VERSION 5.8 ;
BUSBITCHARS "[]" ;
DIVIDERCHAR "/" ;
UNITS
    DATABASE MICRONS 1000 ;
END UNITS

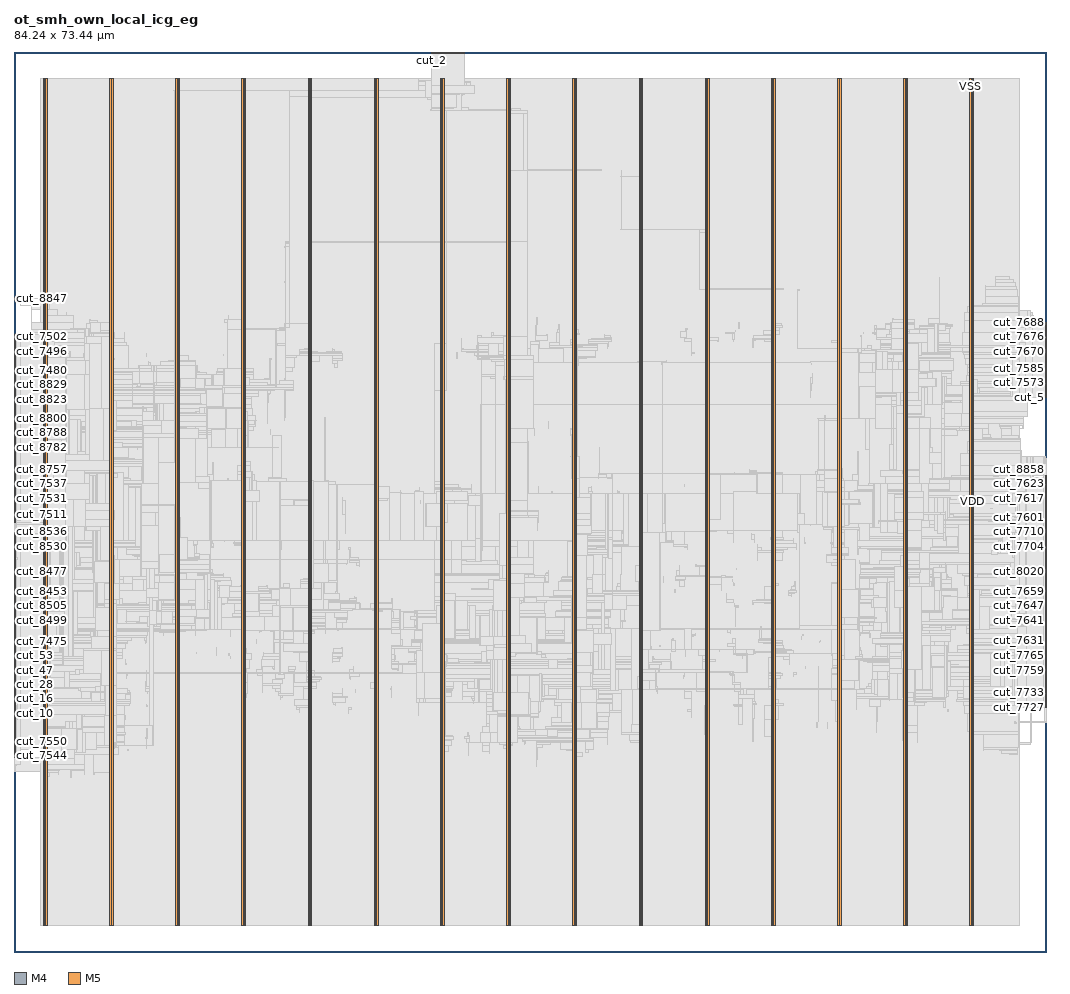
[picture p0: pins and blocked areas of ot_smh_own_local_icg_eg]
MACRO ot_smh_own_local_icg_eg
  FOREIGN ot_smh_own_local_icg_eg 0 0 ;
  CLASS BLOCK ;
  SIZE 84.24 BY 73.44 ;
  PIN cut_10
    DIRECTION INPUT ;
    USE SIGNAL ;
    PORT
      LAYER M4 ;
        RECT  0 19.44 0.084 19.464 ;
    END
  END cut_10
  PIN cut_11
    DIRECTION INPUT ;
    USE SIGNAL ;
    PORT
      LAYER M4 ;
        RECT  0 19.536 0.084 19.56 ;
    END
  END cut_11
  PIN cut_12
    DIRECTION INPUT ;
    USE SIGNAL ;
    PORT
      LAYER M4 ;
        RECT  0 19.632 0.084 19.656 ;
    END
  END cut_12
  PIN cut_13
    DIRECTION INPUT ;
    USE SIGNAL ;
    PORT
      LAYER M4 ;
        RECT  0 19.728 0.084 19.752 ;
    END
  END cut_13
  PIN cut_14
    DIRECTION INPUT ;
    USE SIGNAL ;
    PORT
      LAYER M4 ;
        RECT  0 19.824 0.084 19.848 ;
    END
  END cut_14
  PIN cut_15
    DIRECTION INPUT ;
    USE SIGNAL ;
    PORT
      LAYER M4 ;
        RECT  0 19.92 0.084 19.944 ;
    END
  END cut_15
  PIN cut_16
    DIRECTION INPUT ;
    USE SIGNAL ;
    PORT
      LAYER M4 ;
        RECT  0 20.016 0.084 20.04 ;
    END
  END cut_16
  PIN cut_17
    DIRECTION INPUT ;
    USE SIGNAL ;
    PORT
      LAYER M4 ;
        RECT  0 20.112 0.084 20.136 ;
    END
  END cut_17
  PIN cut_18
    DIRECTION INPUT ;
    USE SIGNAL ;
    PORT
      LAYER M4 ;
        RECT  0 20.208 0.084 20.232 ;
    END
  END cut_18
  PIN cut_19
    DIRECTION INPUT ;
    USE SIGNAL ;
    PORT
      LAYER M4 ;
        RECT  0 20.304 0.084 20.328 ;
    END
  END cut_19
  PIN cut_2
    DIRECTION INPUT ;
    USE SIGNAL ;
    PORT
      LAYER M5 ;
        RECT  34.032 73.356 34.056 73.44 ;
    END
  END cut_2
  PIN cut_20
    DIRECTION INPUT ;
    USE SIGNAL ;
    PORT
      LAYER M4 ;
        RECT  0 20.4 0.084 20.424 ;
    END
  END cut_20
  PIN cut_21
    DIRECTION INPUT ;
    USE SIGNAL ;
    PORT
      LAYER M4 ;
        RECT  0 20.496 0.084 20.52 ;
    END
  END cut_21
  PIN cut_22
    DIRECTION INPUT ;
    USE SIGNAL ;
    PORT
      LAYER M4 ;
        RECT  0 20.592 0.084 20.616 ;
    END
  END cut_22
  PIN cut_23
    DIRECTION INPUT ;
    USE SIGNAL ;
    PORT
      LAYER M4 ;
        RECT  0 20.688 0.084 20.712 ;
    END
  END cut_23
  PIN cut_24
    DIRECTION INPUT ;
    USE SIGNAL ;
    PORT
      LAYER M4 ;
        RECT  0 20.784 0.084 20.808 ;
    END
  END cut_24
  PIN cut_25
    DIRECTION INPUT ;
    USE SIGNAL ;
    PORT
      LAYER M4 ;
        RECT  0 20.88 0.084 20.904 ;
    END
  END cut_25
  PIN cut_26
    DIRECTION INPUT ;
    USE SIGNAL ;
    PORT
      LAYER M4 ;
        RECT  0 20.976 0.084 21 ;
    END
  END cut_26
  PIN cut_27
    DIRECTION INPUT ;
    USE SIGNAL ;
    PORT
      LAYER M4 ;
        RECT  0 21.072 0.084 21.096 ;
    END
  END cut_27
  PIN cut_28
    DIRECTION INPUT ;
    USE SIGNAL ;
    PORT
      LAYER M4 ;
        RECT  0 21.168 0.084 21.192 ;
    END
  END cut_28
  PIN cut_29
    DIRECTION INPUT ;
    USE SIGNAL ;
    PORT
      LAYER M4 ;
        RECT  0 21.264 0.084 21.288 ;
    END
  END cut_29
  PIN cut_3
    DIRECTION INPUT ;
    USE SIGNAL ;
    PORT
      LAYER M5 ;
        RECT  34.128 73.356 34.152 73.44 ;
    END
  END cut_3
  PIN cut_30
    DIRECTION INPUT ;
    USE SIGNAL ;
    PORT
      LAYER M4 ;
        RECT  0 21.36 0.084 21.384 ;
    END
  END cut_30
  PIN cut_31
    DIRECTION INPUT ;
    USE SIGNAL ;
    PORT
      LAYER M4 ;
        RECT  0 21.456 0.084 21.48 ;
    END
  END cut_31
  PIN cut_32
    DIRECTION INPUT ;
    USE SIGNAL ;
    PORT
      LAYER M4 ;
        RECT  0 21.552 0.084 21.576 ;
    END
  END cut_32
  PIN cut_33
    DIRECTION INPUT ;
    USE SIGNAL ;
    PORT
      LAYER M4 ;
        RECT  0 21.648 0.084 21.672 ;
    END
  END cut_33
  PIN cut_34
    DIRECTION INPUT ;
    USE SIGNAL ;
    PORT
      LAYER M4 ;
        RECT  0 21.744 0.084 21.768 ;
    END
  END cut_34
  PIN cut_35
    DIRECTION INPUT ;
    USE SIGNAL ;
    PORT
      LAYER M4 ;
        RECT  0 21.84 0.084 21.864 ;
    END
  END cut_35
  PIN cut_36
    DIRECTION INPUT ;
    USE SIGNAL ;
    PORT
      LAYER M4 ;
        RECT  0 21.936 0.084 21.96 ;
    END
  END cut_36
  PIN cut_37
    DIRECTION INPUT ;
    USE SIGNAL ;
    PORT
      LAYER M4 ;
        RECT  0 22.032 0.084 22.056 ;
    END
  END cut_37
  PIN cut_38
    DIRECTION INPUT ;
    USE SIGNAL ;
    PORT
      LAYER M4 ;
        RECT  0 22.128 0.084 22.152 ;
    END
  END cut_38
  PIN cut_39
    DIRECTION INPUT ;
    USE SIGNAL ;
    PORT
      LAYER M4 ;
        RECT  0 22.224 0.084 22.248 ;
    END
  END cut_39
  PIN cut_4
    DIRECTION INPUT ;
    USE SIGNAL ;
    PORT
      LAYER M4 ;
        RECT  0 18.96 0.084 18.984 ;
    END
  END cut_4
  PIN cut_40
    DIRECTION INPUT ;
    USE SIGNAL ;
    PORT
      LAYER M4 ;
        RECT  0 22.32 0.084 22.344 ;
    END
  END cut_40
  PIN cut_41
    DIRECTION INPUT ;
    USE SIGNAL ;
    PORT
      LAYER M4 ;
        RECT  0 22.416 0.084 22.44 ;
    END
  END cut_41
  PIN cut_42
    DIRECTION INPUT ;
    USE SIGNAL ;
    PORT
      LAYER M4 ;
        RECT  0 22.512 0.084 22.536 ;
    END
  END cut_42
  PIN cut_43
    DIRECTION INPUT ;
    USE SIGNAL ;
    PORT
      LAYER M4 ;
        RECT  0 22.608 0.084 22.632 ;
    END
  END cut_43
  PIN cut_44
    DIRECTION INPUT ;
    USE SIGNAL ;
    PORT
      LAYER M4 ;
        RECT  0 22.704 0.084 22.728 ;
    END
  END cut_44
  PIN cut_45
    DIRECTION INPUT ;
    USE SIGNAL ;
    PORT
      LAYER M4 ;
        RECT  0 22.8 0.084 22.824 ;
    END
  END cut_45
  PIN cut_46
    DIRECTION INPUT ;
    USE SIGNAL ;
    PORT
      LAYER M4 ;
        RECT  0 22.896 0.084 22.92 ;
    END
  END cut_46
  PIN cut_47
    DIRECTION INPUT ;
    USE SIGNAL ;
    PORT
      LAYER M4 ;
        RECT  0 22.992 0.084 23.016 ;
    END
  END cut_47
  PIN cut_48
    DIRECTION INPUT ;
    USE SIGNAL ;
    PORT
      LAYER M4 ;
        RECT  0 23.088 0.084 23.112 ;
    END
  END cut_48
  PIN cut_49
    DIRECTION INPUT ;
    USE SIGNAL ;
    PORT
      LAYER M4 ;
        RECT  0 23.184 0.084 23.208 ;
    END
  END cut_49
  PIN cut_5
    DIRECTION OUTPUT ;
    USE SIGNAL ;
    PORT
      LAYER M4 ;
        RECT  84.156 45.264 84.24 45.288 ;
    END
  END cut_5
  PIN cut_50
    DIRECTION INPUT ;
    USE SIGNAL ;
    PORT
      LAYER M4 ;
        RECT  0 23.28 0.084 23.304 ;
    END
  END cut_50
  PIN cut_51
    DIRECTION INPUT ;
    USE SIGNAL ;
    PORT
      LAYER M4 ;
        RECT  0 23.376 0.084 23.4 ;
    END
  END cut_51
  PIN cut_52
    DIRECTION INPUT ;
    USE SIGNAL ;
    PORT
      LAYER M4 ;
        RECT  0 23.472 0.084 23.496 ;
    END
  END cut_52
  PIN cut_53
    DIRECTION INPUT ;
    USE SIGNAL ;
    PORT
      LAYER M4 ;
        RECT  0 23.568 0.084 23.592 ;
    END
  END cut_53
  PIN cut_54
    DIRECTION INPUT ;
    USE SIGNAL ;
    PORT
      LAYER M4 ;
        RECT  0 23.664 0.084 23.688 ;
    END
  END cut_54
  PIN cut_55
    DIRECTION INPUT ;
    USE SIGNAL ;
    PORT
      LAYER M4 ;
        RECT  0 23.76 0.084 23.784 ;
    END
  END cut_55
  PIN cut_56
    DIRECTION INPUT ;
    USE SIGNAL ;
    PORT
      LAYER M4 ;
        RECT  0 23.856 0.084 23.88 ;
    END
  END cut_56
  PIN cut_57
    DIRECTION INPUT ;
    USE SIGNAL ;
    PORT
      LAYER M4 ;
        RECT  0 23.952 0.084 23.976 ;
    END
  END cut_57
  PIN cut_6
    DIRECTION INPUT ;
    USE SIGNAL ;
    PORT
      LAYER M4 ;
        RECT  0 19.056 0.084 19.08 ;
    END
  END cut_6
  PIN cut_7
    DIRECTION INPUT ;
    USE SIGNAL ;
    PORT
      LAYER M4 ;
        RECT  0 19.152 0.084 19.176 ;
    END
  END cut_7
  PIN cut_7468
    DIRECTION INPUT ;
    USE SIGNAL ;
    PORT
      LAYER M4 ;
        RECT  0 24.048 0.084 24.072 ;
    END
  END cut_7468
  PIN cut_7469
    DIRECTION INPUT ;
    USE SIGNAL ;
    PORT
      LAYER M4 ;
        RECT  0 24.144 0.084 24.168 ;
    END
  END cut_7469
  PIN cut_7470
    DIRECTION INPUT ;
    USE SIGNAL ;
    PORT
      LAYER M4 ;
        RECT  0 24.24 0.084 24.264 ;
    END
  END cut_7470
  PIN cut_7471
    DIRECTION INPUT ;
    USE SIGNAL ;
    PORT
      LAYER M4 ;
        RECT  0 24.336 0.084 24.36 ;
    END
  END cut_7471
  PIN cut_7472
    DIRECTION INPUT ;
    USE SIGNAL ;
    PORT
      LAYER M4 ;
        RECT  0 24.432 0.084 24.456 ;
    END
  END cut_7472
  PIN cut_7473
    DIRECTION INPUT ;
    USE SIGNAL ;
    PORT
      LAYER M4 ;
        RECT  0 24.528 0.084 24.552 ;
    END
  END cut_7473
  PIN cut_7474
    DIRECTION INPUT ;
    USE SIGNAL ;
    PORT
      LAYER M4 ;
        RECT  0 24.624 0.084 24.648 ;
    END
  END cut_7474
  PIN cut_7475
    DIRECTION INPUT ;
    USE SIGNAL ;
    PORT
      LAYER M4 ;
        RECT  0 24.72 0.084 24.744 ;
    END
  END cut_7475
  PIN cut_7476
    DIRECTION INPUT ;
    USE SIGNAL ;
    PORT
      LAYER M4 ;
        RECT  0 24.816 0.084 24.84 ;
    END
  END cut_7476
  PIN cut_7477
    DIRECTION INPUT ;
    USE SIGNAL ;
    PORT
      LAYER M4 ;
        RECT  0 24.912 0.084 24.936 ;
    END
  END cut_7477
  PIN cut_7478
    DIRECTION INPUT ;
    USE SIGNAL ;
    PORT
      LAYER M4 ;
        RECT  0 25.008 0.084 25.032 ;
    END
  END cut_7478
  PIN cut_7479
    DIRECTION INPUT ;
    USE SIGNAL ;
    PORT
      LAYER M4 ;
        RECT  0 47.376 0.084 47.4 ;
    END
  END cut_7479
  PIN cut_7480
    DIRECTION INPUT ;
    USE SIGNAL ;
    PORT
      LAYER M4 ;
        RECT  0 47.472 0.084 47.496 ;
    END
  END cut_7480
  PIN cut_7481
    DIRECTION INPUT ;
    USE SIGNAL ;
    PORT
      LAYER M4 ;
        RECT  0 47.568 0.084 47.592 ;
    END
  END cut_7481
  PIN cut_7482
    DIRECTION INPUT ;
    USE SIGNAL ;
    PORT
      LAYER M4 ;
        RECT  0 47.664 0.084 47.688 ;
    END
  END cut_7482
  PIN cut_7483
    DIRECTION INPUT ;
    USE SIGNAL ;
    PORT
      LAYER M4 ;
        RECT  0 47.76 0.084 47.784 ;
    END
  END cut_7483
  PIN cut_7484
    DIRECTION INPUT ;
    USE SIGNAL ;
    PORT
      LAYER M4 ;
        RECT  0 47.856 0.084 47.88 ;
    END
  END cut_7484
  PIN cut_7485
    DIRECTION INPUT ;
    USE SIGNAL ;
    PORT
      LAYER M4 ;
        RECT  0 47.952 0.084 47.976 ;
    END
  END cut_7485
  PIN cut_7486
    DIRECTION INPUT ;
    USE SIGNAL ;
    PORT
      LAYER M4 ;
        RECT  0 48.048 0.084 48.072 ;
    END
  END cut_7486
  PIN cut_7487
    DIRECTION INPUT ;
    USE SIGNAL ;
    PORT
      LAYER M4 ;
        RECT  0 48.144 0.084 48.168 ;
    END
  END cut_7487
  PIN cut_7488
    DIRECTION INPUT ;
    USE SIGNAL ;
    PORT
      LAYER M4 ;
        RECT  0 48.24 0.084 48.264 ;
    END
  END cut_7488
  PIN cut_7489
    DIRECTION INPUT ;
    USE SIGNAL ;
    PORT
      LAYER M4 ;
        RECT  0 48.336 0.084 48.36 ;
    END
  END cut_7489
  PIN cut_7490
    DIRECTION INPUT ;
    USE SIGNAL ;
    PORT
      LAYER M4 ;
        RECT  0 48.432 0.084 48.456 ;
    END
  END cut_7490
  PIN cut_7491
    DIRECTION INPUT ;
    USE SIGNAL ;
    PORT
      LAYER M4 ;
        RECT  0 48.528 0.084 48.552 ;
    END
  END cut_7491
  PIN cut_7492
    DIRECTION INPUT ;
    USE SIGNAL ;
    PORT
      LAYER M4 ;
        RECT  0 48.624 0.084 48.648 ;
    END
  END cut_7492
  PIN cut_7493
    DIRECTION INPUT ;
    USE SIGNAL ;
    PORT
      LAYER M4 ;
        RECT  0 48.72 0.084 48.744 ;
    END
  END cut_7493
  PIN cut_7494
    DIRECTION INPUT ;
    USE SIGNAL ;
    PORT
      LAYER M4 ;
        RECT  0 48.816 0.084 48.84 ;
    END
  END cut_7494
  PIN cut_7495
    DIRECTION INPUT ;
    USE SIGNAL ;
    PORT
      LAYER M4 ;
        RECT  0 48.912 0.084 48.936 ;
    END
  END cut_7495
  PIN cut_7496
    DIRECTION INPUT ;
    USE SIGNAL ;
    PORT
      LAYER M4 ;
        RECT  0 49.008 0.084 49.032 ;
    END
  END cut_7496
  PIN cut_7497
    DIRECTION INPUT ;
    USE SIGNAL ;
    PORT
      LAYER M4 ;
        RECT  0 49.104 0.084 49.128 ;
    END
  END cut_7497
  PIN cut_7498
    DIRECTION INPUT ;
    USE SIGNAL ;
    PORT
      LAYER M4 ;
        RECT  0 49.2 0.084 49.224 ;
    END
  END cut_7498
  PIN cut_7499
    DIRECTION INPUT ;
    USE SIGNAL ;
    PORT
      LAYER M4 ;
        RECT  0 49.296 0.084 49.32 ;
    END
  END cut_7499
  PIN cut_7500
    DIRECTION INPUT ;
    USE SIGNAL ;
    PORT
      LAYER M4 ;
        RECT  0 49.392 0.084 49.416 ;
    END
  END cut_7500
  PIN cut_7501
    DIRECTION INPUT ;
    USE SIGNAL ;
    PORT
      LAYER M4 ;
        RECT  0 49.488 0.084 49.512 ;
    END
  END cut_7501
  PIN cut_7502
    DIRECTION INPUT ;
    USE SIGNAL ;
    PORT
      LAYER M4 ;
        RECT  0 49.584 0.084 49.608 ;
    END
  END cut_7502
  PIN cut_7503
    DIRECTION INPUT ;
    USE SIGNAL ;
    PORT
      LAYER M4 ;
        RECT  0 49.68 0.084 49.704 ;
    END
  END cut_7503
  PIN cut_7504
    DIRECTION INPUT ;
    USE SIGNAL ;
    PORT
      LAYER M4 ;
        RECT  0 49.776 0.084 49.8 ;
    END
  END cut_7504
  PIN cut_7505
    DIRECTION INPUT ;
    USE SIGNAL ;
    PORT
      LAYER M4 ;
        RECT  0 49.872 0.084 49.896 ;
    END
  END cut_7505
  PIN cut_7506
    DIRECTION INPUT ;
    USE SIGNAL ;
    PORT
      LAYER M4 ;
        RECT  0 49.968 0.084 49.992 ;
    END
  END cut_7506
  PIN cut_7507
    DIRECTION INPUT ;
    USE SIGNAL ;
    PORT
      LAYER M4 ;
        RECT  0 50.064 0.084 50.088 ;
    END
  END cut_7507
  PIN cut_7508
    DIRECTION INPUT ;
    USE SIGNAL ;
    PORT
      LAYER M4 ;
        RECT  0 50.16 0.084 50.184 ;
    END
  END cut_7508
  PIN cut_7509
    DIRECTION INPUT ;
    USE SIGNAL ;
    PORT
      LAYER M4 ;
        RECT  0 50.256 0.084 50.28 ;
    END
  END cut_7509
  PIN cut_7510
    DIRECTION INPUT ;
    USE SIGNAL ;
    PORT
      LAYER M4 ;
        RECT  0 50.352 0.084 50.376 ;
    END
  END cut_7510
  PIN cut_7511
    DIRECTION INPUT ;
    USE SIGNAL ;
    PORT
      LAYER M4 ;
        RECT  0 35.088 0.084 35.112 ;
    END
  END cut_7511
  PIN cut_7512
    DIRECTION INPUT ;
    USE SIGNAL ;
    PORT
      LAYER M4 ;
        RECT  0 35.184 0.084 35.208 ;
    END
  END cut_7512
  PIN cut_7513
    DIRECTION INPUT ;
    USE SIGNAL ;
    PORT
      LAYER M4 ;
        RECT  0 35.28 0.084 35.304 ;
    END
  END cut_7513
  PIN cut_7514
    DIRECTION INPUT ;
    USE SIGNAL ;
    PORT
      LAYER M4 ;
        RECT  0 35.376 0.084 35.4 ;
    END
  END cut_7514
  PIN cut_7515
    DIRECTION INPUT ;
    USE SIGNAL ;
    PORT
      LAYER M4 ;
        RECT  0 35.472 0.084 35.496 ;
    END
  END cut_7515
  PIN cut_7516
    DIRECTION INPUT ;
    USE SIGNAL ;
    PORT
      LAYER M4 ;
        RECT  0 35.568 0.084 35.592 ;
    END
  END cut_7516
  PIN cut_7517
    DIRECTION INPUT ;
    USE SIGNAL ;
    PORT
      LAYER M4 ;
        RECT  0 35.664 0.084 35.688 ;
    END
  END cut_7517
  PIN cut_7518
    DIRECTION INPUT ;
    USE SIGNAL ;
    PORT
      LAYER M4 ;
        RECT  0 35.76 0.084 35.784 ;
    END
  END cut_7518
  PIN cut_7519
    DIRECTION INPUT ;
    USE SIGNAL ;
    PORT
      LAYER M4 ;
        RECT  0 35.856 0.084 35.88 ;
    END
  END cut_7519
  PIN cut_7520
    DIRECTION INPUT ;
    USE SIGNAL ;
    PORT
      LAYER M4 ;
        RECT  0 35.952 0.084 35.976 ;
    END
  END cut_7520
  PIN cut_7521
    DIRECTION INPUT ;
    USE SIGNAL ;
    PORT
      LAYER M4 ;
        RECT  0 36.048 0.084 36.072 ;
    END
  END cut_7521
  PIN cut_7522
    DIRECTION INPUT ;
    USE SIGNAL ;
    PORT
      LAYER M4 ;
        RECT  0 36.144 0.084 36.168 ;
    END
  END cut_7522
  PIN cut_7523
    DIRECTION INPUT ;
    USE SIGNAL ;
    PORT
      LAYER M4 ;
        RECT  0 36.24 0.084 36.264 ;
    END
  END cut_7523
  PIN cut_7524
    DIRECTION INPUT ;
    USE SIGNAL ;
    PORT
      LAYER M4 ;
        RECT  0 36.336 0.084 36.36 ;
    END
  END cut_7524
  PIN cut_7525
    DIRECTION INPUT ;
    USE SIGNAL ;
    PORT
      LAYER M4 ;
        RECT  0 36.432 0.084 36.456 ;
    END
  END cut_7525
  PIN cut_7526
    DIRECTION INPUT ;
    USE SIGNAL ;
    PORT
      LAYER M4 ;
        RECT  0 36.528 0.084 36.552 ;
    END
  END cut_7526
  PIN cut_7527
    DIRECTION INPUT ;
    USE SIGNAL ;
    PORT
      LAYER M4 ;
        RECT  0 36.624 0.084 36.648 ;
    END
  END cut_7527
  PIN cut_7528
    DIRECTION INPUT ;
    USE SIGNAL ;
    PORT
      LAYER M4 ;
        RECT  0 36.72 0.084 36.744 ;
    END
  END cut_7528
  PIN cut_7529
    DIRECTION INPUT ;
    USE SIGNAL ;
    PORT
      LAYER M4 ;
        RECT  0 36.816 0.084 36.84 ;
    END
  END cut_7529
  PIN cut_7530
    DIRECTION INPUT ;
    USE SIGNAL ;
    PORT
      LAYER M4 ;
        RECT  0 36.912 0.084 36.936 ;
    END
  END cut_7530
  PIN cut_7531
    DIRECTION INPUT ;
    USE SIGNAL ;
    PORT
      LAYER M4 ;
        RECT  0 37.008 0.084 37.032 ;
    END
  END cut_7531
  PIN cut_7532
    DIRECTION INPUT ;
    USE SIGNAL ;
    PORT
      LAYER M4 ;
        RECT  0 37.104 0.084 37.128 ;
    END
  END cut_7532
  PIN cut_7533
    DIRECTION INPUT ;
    USE SIGNAL ;
    PORT
      LAYER M4 ;
        RECT  0 37.2 0.084 37.224 ;
    END
  END cut_7533
  PIN cut_7534
    DIRECTION INPUT ;
    USE SIGNAL ;
    PORT
      LAYER M4 ;
        RECT  0 37.296 0.084 37.32 ;
    END
  END cut_7534
  PIN cut_7535
    DIRECTION INPUT ;
    USE SIGNAL ;
    PORT
      LAYER M4 ;
        RECT  0 37.392 0.084 37.416 ;
    END
  END cut_7535
  PIN cut_7536
    DIRECTION INPUT ;
    USE SIGNAL ;
    PORT
      LAYER M4 ;
        RECT  0 37.488 0.084 37.512 ;
    END
  END cut_7536
  PIN cut_7537
    DIRECTION INPUT ;
    USE SIGNAL ;
    PORT
      LAYER M4 ;
        RECT  0 37.584 0.084 37.608 ;
    END
  END cut_7537
  PIN cut_7538
    DIRECTION INPUT ;
    USE SIGNAL ;
    PORT
      LAYER M4 ;
        RECT  0 37.68 0.084 37.704 ;
    END
  END cut_7538
  PIN cut_7539
    DIRECTION INPUT ;
    USE SIGNAL ;
    PORT
      LAYER M4 ;
        RECT  0 37.776 0.084 37.8 ;
    END
  END cut_7539
  PIN cut_7540
    DIRECTION INPUT ;
    USE SIGNAL ;
    PORT
      LAYER M4 ;
        RECT  0 37.872 0.084 37.896 ;
    END
  END cut_7540
  PIN cut_7541
    DIRECTION INPUT ;
    USE SIGNAL ;
    PORT
      LAYER M4 ;
        RECT  0 37.968 0.084 37.992 ;
    END
  END cut_7541
  PIN cut_7542
    DIRECTION INPUT ;
    USE SIGNAL ;
    PORT
      LAYER M4 ;
        RECT  0 38.064 0.084 38.088 ;
    END
  END cut_7542
  PIN cut_7543
    DIRECTION INPUT ;
    USE SIGNAL ;
    PORT
      LAYER M4 ;
        RECT  0 15.888 0.084 15.912 ;
    END
  END cut_7543
  PIN cut_7544
    DIRECTION INPUT ;
    USE SIGNAL ;
    PORT
      LAYER M4 ;
        RECT  0 15.984 0.084 16.008 ;
    END
  END cut_7544
  PIN cut_7545
    DIRECTION INPUT ;
    USE SIGNAL ;
    PORT
      LAYER M4 ;
        RECT  0 16.08 0.084 16.104 ;
    END
  END cut_7545
  PIN cut_7546
    DIRECTION INPUT ;
    USE SIGNAL ;
    PORT
      LAYER M4 ;
        RECT  0 16.176 0.084 16.2 ;
    END
  END cut_7546
  PIN cut_7547
    DIRECTION INPUT ;
    USE SIGNAL ;
    PORT
      LAYER M4 ;
        RECT  0 16.272 0.084 16.296 ;
    END
  END cut_7547
  PIN cut_7548
    DIRECTION INPUT ;
    USE SIGNAL ;
    PORT
      LAYER M4 ;
        RECT  0 16.368 0.084 16.392 ;
    END
  END cut_7548
  PIN cut_7549
    DIRECTION INPUT ;
    USE SIGNAL ;
    PORT
      LAYER M4 ;
        RECT  0 16.464 0.084 16.488 ;
    END
  END cut_7549
  PIN cut_7550
    DIRECTION INPUT ;
    USE SIGNAL ;
    PORT
      LAYER M4 ;
        RECT  0 16.56 0.084 16.584 ;
    END
  END cut_7550
  PIN cut_7551
    DIRECTION INPUT ;
    USE SIGNAL ;
    PORT
      LAYER M4 ;
        RECT  0 16.656 0.084 16.68 ;
    END
  END cut_7551
  PIN cut_7552
    DIRECTION INPUT ;
    USE SIGNAL ;
    PORT
      LAYER M4 ;
        RECT  0 16.752 0.084 16.776 ;
    END
  END cut_7552
  PIN cut_7553
    DIRECTION INPUT ;
    USE SIGNAL ;
    PORT
      LAYER M4 ;
        RECT  0 16.848 0.084 16.872 ;
    END
  END cut_7553
  PIN cut_7554
    DIRECTION INPUT ;
    USE SIGNAL ;
    PORT
      LAYER M4 ;
        RECT  0 16.944 0.084 16.968 ;
    END
  END cut_7554
  PIN cut_7555
    DIRECTION INPUT ;
    USE SIGNAL ;
    PORT
      LAYER M4 ;
        RECT  0 17.04 0.084 17.064 ;
    END
  END cut_7555
  PIN cut_7556
    DIRECTION INPUT ;
    USE SIGNAL ;
    PORT
      LAYER M4 ;
        RECT  0 17.136 0.084 17.16 ;
    END
  END cut_7556
  PIN cut_7557
    DIRECTION INPUT ;
    USE SIGNAL ;
    PORT
      LAYER M4 ;
        RECT  0 17.232 0.084 17.256 ;
    END
  END cut_7557
  PIN cut_7558
    DIRECTION INPUT ;
    USE SIGNAL ;
    PORT
      LAYER M4 ;
        RECT  0 17.328 0.084 17.352 ;
    END
  END cut_7558
  PIN cut_7559
    DIRECTION INPUT ;
    USE SIGNAL ;
    PORT
      LAYER M4 ;
        RECT  0 17.424 0.084 17.448 ;
    END
  END cut_7559
  PIN cut_7560
    DIRECTION INPUT ;
    USE SIGNAL ;
    PORT
      LAYER M4 ;
        RECT  0 17.52 0.084 17.544 ;
    END
  END cut_7560
  PIN cut_7561
    DIRECTION INPUT ;
    USE SIGNAL ;
    PORT
      LAYER M4 ;
        RECT  0 17.616 0.084 17.64 ;
    END
  END cut_7561
  PIN cut_7562
    DIRECTION INPUT ;
    USE SIGNAL ;
    PORT
      LAYER M4 ;
        RECT  0 17.712 0.084 17.736 ;
    END
  END cut_7562
  PIN cut_7563
    DIRECTION INPUT ;
    USE SIGNAL ;
    PORT
      LAYER M4 ;
        RECT  0 17.808 0.084 17.832 ;
    END
  END cut_7563
  PIN cut_7564
    DIRECTION INPUT ;
    USE SIGNAL ;
    PORT
      LAYER M4 ;
        RECT  0 17.904 0.084 17.928 ;
    END
  END cut_7564
  PIN cut_7565
    DIRECTION INPUT ;
    USE SIGNAL ;
    PORT
      LAYER M4 ;
        RECT  0 18 0.084 18.024 ;
    END
  END cut_7565
  PIN cut_7566
    DIRECTION INPUT ;
    USE SIGNAL ;
    PORT
      LAYER M4 ;
        RECT  0 18.096 0.084 18.12 ;
    END
  END cut_7566
  PIN cut_7567
    DIRECTION INPUT ;
    USE SIGNAL ;
    PORT
      LAYER M4 ;
        RECT  0 18.192 0.084 18.216 ;
    END
  END cut_7567
  PIN cut_7568
    DIRECTION OUTPUT ;
    USE SIGNAL ;
    PORT
      LAYER M4 ;
        RECT  84.156 45.36 84.24 45.384 ;
    END
  END cut_7568
  PIN cut_7569
    DIRECTION OUTPUT ;
    USE SIGNAL ;
    PORT
      LAYER M4 ;
        RECT  84.156 45.456 84.24 45.48 ;
    END
  END cut_7569
  PIN cut_7570
    DIRECTION OUTPUT ;
    USE SIGNAL ;
    PORT
      LAYER M4 ;
        RECT  84.156 45.552 84.24 45.576 ;
    END
  END cut_7570
  PIN cut_7571
    DIRECTION OUTPUT ;
    USE SIGNAL ;
    PORT
      LAYER M4 ;
        RECT  84.156 45.648 84.24 45.672 ;
    END
  END cut_7571
  PIN cut_7572
    DIRECTION OUTPUT ;
    USE SIGNAL ;
    PORT
      LAYER M4 ;
        RECT  84.156 45.744 84.24 45.768 ;
    END
  END cut_7572
  PIN cut_7573
    DIRECTION OUTPUT ;
    USE SIGNAL ;
    PORT
      LAYER M4 ;
        RECT  84.156 45.84 84.24 45.864 ;
    END
  END cut_7573
  PIN cut_7574
    DIRECTION OUTPUT ;
    USE SIGNAL ;
    PORT
      LAYER M4 ;
        RECT  84.156 45.936 84.24 45.96 ;
    END
  END cut_7574
  PIN cut_7575
    DIRECTION OUTPUT ;
    USE SIGNAL ;
    PORT
      LAYER M4 ;
        RECT  84.156 46.032 84.24 46.056 ;
    END
  END cut_7575
  PIN cut_7576
    DIRECTION OUTPUT ;
    USE SIGNAL ;
    PORT
      LAYER M4 ;
        RECT  84.156 46.128 84.24 46.152 ;
    END
  END cut_7576
  PIN cut_7577
    DIRECTION OUTPUT ;
    USE SIGNAL ;
    PORT
      LAYER M4 ;
        RECT  84.156 46.224 84.24 46.248 ;
    END
  END cut_7577
  PIN cut_7578
    DIRECTION OUTPUT ;
    USE SIGNAL ;
    PORT
      LAYER M4 ;
        RECT  84.156 46.32 84.24 46.344 ;
    END
  END cut_7578
  PIN cut_7579
    DIRECTION OUTPUT ;
    USE SIGNAL ;
    PORT
      LAYER M4 ;
        RECT  84.156 46.416 84.24 46.44 ;
    END
  END cut_7579
  PIN cut_7580
    DIRECTION OUTPUT ;
    USE SIGNAL ;
    PORT
      LAYER M4 ;
        RECT  84.156 46.512 84.24 46.536 ;
    END
  END cut_7580
  PIN cut_7581
    DIRECTION OUTPUT ;
    USE SIGNAL ;
    PORT
      LAYER M4 ;
        RECT  84.156 46.608 84.24 46.632 ;
    END
  END cut_7581
  PIN cut_7582
    DIRECTION OUTPUT ;
    USE SIGNAL ;
    PORT
      LAYER M4 ;
        RECT  84.156 46.704 84.24 46.728 ;
    END
  END cut_7582
  PIN cut_7583
    DIRECTION OUTPUT ;
    USE SIGNAL ;
    PORT
      LAYER M4 ;
        RECT  84.156 46.8 84.24 46.824 ;
    END
  END cut_7583
  PIN cut_7584
    DIRECTION OUTPUT ;
    USE SIGNAL ;
    PORT
      LAYER M4 ;
        RECT  84.156 46.896 84.24 46.92 ;
    END
  END cut_7584
  PIN cut_7585
    DIRECTION OUTPUT ;
    USE SIGNAL ;
    PORT
      LAYER M4 ;
        RECT  84.156 46.992 84.24 47.016 ;
    END
  END cut_7585
  PIN cut_7586
    DIRECTION OUTPUT ;
    USE SIGNAL ;
    PORT
      LAYER M4 ;
        RECT  84.156 47.088 84.24 47.112 ;
    END
  END cut_7586
  PIN cut_7587
    DIRECTION OUTPUT ;
    USE SIGNAL ;
    PORT
      LAYER M4 ;
        RECT  84.156 47.184 84.24 47.208 ;
    END
  END cut_7587
  PIN cut_7588
    DIRECTION OUTPUT ;
    USE SIGNAL ;
    PORT
      LAYER M4 ;
        RECT  84.156 47.28 84.24 47.304 ;
    END
  END cut_7588
  PIN cut_7589
    DIRECTION OUTPUT ;
    USE SIGNAL ;
    PORT
      LAYER M4 ;
        RECT  84.156 47.376 84.24 47.4 ;
    END
  END cut_7589
  PIN cut_7590
    DIRECTION OUTPUT ;
    USE SIGNAL ;
    PORT
      LAYER M4 ;
        RECT  84.156 47.472 84.24 47.496 ;
    END
  END cut_7590
  PIN cut_7591
    DIRECTION OUTPUT ;
    USE SIGNAL ;
    PORT
      LAYER M4 ;
        RECT  84.156 47.568 84.24 47.592 ;
    END
  END cut_7591
  PIN cut_7592
    DIRECTION OUTPUT ;
    USE SIGNAL ;
    PORT
      LAYER M4 ;
        RECT  84.156 47.664 84.24 47.688 ;
    END
  END cut_7592
  PIN cut_7593
    DIRECTION OUTPUT ;
    USE SIGNAL ;
    PORT
      LAYER M4 ;
        RECT  84.156 47.76 84.24 47.784 ;
    END
  END cut_7593
  PIN cut_7594
    DIRECTION OUTPUT ;
    USE SIGNAL ;
    PORT
      LAYER M4 ;
        RECT  84.156 47.856 84.24 47.88 ;
    END
  END cut_7594
  PIN cut_7595
    DIRECTION OUTPUT ;
    USE SIGNAL ;
    PORT
      LAYER M4 ;
        RECT  84.156 47.952 84.24 47.976 ;
    END
  END cut_7595
  PIN cut_7596
    DIRECTION OUTPUT ;
    USE SIGNAL ;
    PORT
      LAYER M4 ;
        RECT  84.156 48.048 84.24 48.072 ;
    END
  END cut_7596
  PIN cut_7597
    DIRECTION OUTPUT ;
    USE SIGNAL ;
    PORT
      LAYER M4 ;
        RECT  84.156 48.144 84.24 48.168 ;
    END
  END cut_7597
  PIN cut_7598
    DIRECTION OUTPUT ;
    USE SIGNAL ;
    PORT
      LAYER M4 ;
        RECT  84.156 48.24 84.24 48.264 ;
    END
  END cut_7598
  PIN cut_7599
    DIRECTION OUTPUT ;
    USE SIGNAL ;
    PORT
      LAYER M4 ;
        RECT  84.156 35.28 84.24 35.304 ;
    END
  END cut_7599
  PIN cut_7600
    DIRECTION OUTPUT ;
    USE SIGNAL ;
    PORT
      LAYER M4 ;
        RECT  84.156 35.376 84.24 35.4 ;
    END
  END cut_7600
  PIN cut_7601
    DIRECTION OUTPUT ;
    USE SIGNAL ;
    PORT
      LAYER M4 ;
        RECT  84.156 35.472 84.24 35.496 ;
    END
  END cut_7601
  PIN cut_7602
    DIRECTION OUTPUT ;
    USE SIGNAL ;
    PORT
      LAYER M4 ;
        RECT  84.156 35.568 84.24 35.592 ;
    END
  END cut_7602
  PIN cut_7603
    DIRECTION OUTPUT ;
    USE SIGNAL ;
    PORT
      LAYER M4 ;
        RECT  84.156 35.664 84.24 35.688 ;
    END
  END cut_7603
  PIN cut_7604
    DIRECTION OUTPUT ;
    USE SIGNAL ;
    PORT
      LAYER M4 ;
        RECT  84.156 35.76 84.24 35.784 ;
    END
  END cut_7604
  PIN cut_7605
    DIRECTION OUTPUT ;
    USE SIGNAL ;
    PORT
      LAYER M4 ;
        RECT  84.156 35.856 84.24 35.88 ;
    END
  END cut_7605
  PIN cut_7606
    DIRECTION OUTPUT ;
    USE SIGNAL ;
    PORT
      LAYER M4 ;
        RECT  84.156 35.952 84.24 35.976 ;
    END
  END cut_7606
  PIN cut_7607
    DIRECTION OUTPUT ;
    USE SIGNAL ;
    PORT
      LAYER M4 ;
        RECT  84.156 36.048 84.24 36.072 ;
    END
  END cut_7607
  PIN cut_7608
    DIRECTION OUTPUT ;
    USE SIGNAL ;
    PORT
      LAYER M4 ;
        RECT  84.156 36.144 84.24 36.168 ;
    END
  END cut_7608
  PIN cut_7609
    DIRECTION OUTPUT ;
    USE SIGNAL ;
    PORT
      LAYER M4 ;
        RECT  84.156 36.24 84.24 36.264 ;
    END
  END cut_7609
  PIN cut_7610
    DIRECTION OUTPUT ;
    USE SIGNAL ;
    PORT
      LAYER M4 ;
        RECT  84.156 36.336 84.24 36.36 ;
    END
  END cut_7610
  PIN cut_7611
    DIRECTION OUTPUT ;
    USE SIGNAL ;
    PORT
      LAYER M4 ;
        RECT  84.156 36.432 84.24 36.456 ;
    END
  END cut_7611
  PIN cut_7612
    DIRECTION OUTPUT ;
    USE SIGNAL ;
    PORT
      LAYER M4 ;
        RECT  84.156 36.528 84.24 36.552 ;
    END
  END cut_7612
  PIN cut_7613
    DIRECTION OUTPUT ;
    USE SIGNAL ;
    PORT
      LAYER M4 ;
        RECT  84.156 36.624 84.24 36.648 ;
    END
  END cut_7613
  PIN cut_7614
    DIRECTION OUTPUT ;
    USE SIGNAL ;
    PORT
      LAYER M4 ;
        RECT  84.156 36.72 84.24 36.744 ;
    END
  END cut_7614
  PIN cut_7615
    DIRECTION OUTPUT ;
    USE SIGNAL ;
    PORT
      LAYER M4 ;
        RECT  84.156 36.816 84.24 36.84 ;
    END
  END cut_7615
  PIN cut_7616
    DIRECTION OUTPUT ;
    USE SIGNAL ;
    PORT
      LAYER M4 ;
        RECT  84.156 36.912 84.24 36.936 ;
    END
  END cut_7616
  PIN cut_7617
    DIRECTION OUTPUT ;
    USE SIGNAL ;
    PORT
      LAYER M4 ;
        RECT  84.156 37.008 84.24 37.032 ;
    END
  END cut_7617
  PIN cut_7618
    DIRECTION OUTPUT ;
    USE SIGNAL ;
    PORT
      LAYER M4 ;
        RECT  84.156 37.104 84.24 37.128 ;
    END
  END cut_7618
  PIN cut_7619
    DIRECTION OUTPUT ;
    USE SIGNAL ;
    PORT
      LAYER M4 ;
        RECT  84.156 37.2 84.24 37.224 ;
    END
  END cut_7619
  PIN cut_7620
    DIRECTION OUTPUT ;
    USE SIGNAL ;
    PORT
      LAYER M4 ;
        RECT  84.156 37.296 84.24 37.32 ;
    END
  END cut_7620
  PIN cut_7621
    DIRECTION OUTPUT ;
    USE SIGNAL ;
    PORT
      LAYER M4 ;
        RECT  84.156 37.392 84.24 37.416 ;
    END
  END cut_7621
  PIN cut_7622
    DIRECTION OUTPUT ;
    USE SIGNAL ;
    PORT
      LAYER M4 ;
        RECT  84.156 37.488 84.24 37.512 ;
    END
  END cut_7622
  PIN cut_7623
    DIRECTION OUTPUT ;
    USE SIGNAL ;
    PORT
      LAYER M4 ;
        RECT  84.156 37.584 84.24 37.608 ;
    END
  END cut_7623
  PIN cut_7624
    DIRECTION OUTPUT ;
    USE SIGNAL ;
    PORT
      LAYER M4 ;
        RECT  84.156 37.68 84.24 37.704 ;
    END
  END cut_7624
  PIN cut_7625
    DIRECTION OUTPUT ;
    USE SIGNAL ;
    PORT
      LAYER M4 ;
        RECT  84.156 37.776 84.24 37.8 ;
    END
  END cut_7625
  PIN cut_7626
    DIRECTION OUTPUT ;
    USE SIGNAL ;
    PORT
      LAYER M4 ;
        RECT  84.156 37.872 84.24 37.896 ;
    END
  END cut_7626
  PIN cut_7627
    DIRECTION OUTPUT ;
    USE SIGNAL ;
    PORT
      LAYER M4 ;
        RECT  84.156 37.968 84.24 37.992 ;
    END
  END cut_7627
  PIN cut_7628
    DIRECTION OUTPUT ;
    USE SIGNAL ;
    PORT
      LAYER M4 ;
        RECT  84.156 38.064 84.24 38.088 ;
    END
  END cut_7628
  PIN cut_7629
    DIRECTION OUTPUT ;
    USE SIGNAL ;
    PORT
      LAYER M4 ;
        RECT  84.156 38.16 84.24 38.184 ;
    END
  END cut_7629
  PIN cut_7630
    DIRECTION OUTPUT ;
    USE SIGNAL ;
    PORT
      LAYER M4 ;
        RECT  84.156 38.256 84.24 38.28 ;
    END
  END cut_7630
  PIN cut_7631
    DIRECTION OUTPUT ;
    USE SIGNAL ;
    PORT
      LAYER M4 ;
        RECT  84.156 26.064 84.24 26.088 ;
    END
  END cut_7631
  PIN cut_7632
    DIRECTION OUTPUT ;
    USE SIGNAL ;
    PORT
      LAYER M4 ;
        RECT  84.156 26.16 84.24 26.184 ;
    END
  END cut_7632
  PIN cut_7633
    DIRECTION OUTPUT ;
    USE SIGNAL ;
    PORT
      LAYER M4 ;
        RECT  84.156 26.256 84.24 26.28 ;
    END
  END cut_7633
  PIN cut_7634
    DIRECTION OUTPUT ;
    USE SIGNAL ;
    PORT
      LAYER M4 ;
        RECT  84.156 26.352 84.24 26.376 ;
    END
  END cut_7634
  PIN cut_7635
    DIRECTION OUTPUT ;
    USE SIGNAL ;
    PORT
      LAYER M4 ;
        RECT  84.156 26.448 84.24 26.472 ;
    END
  END cut_7635
  PIN cut_7636
    DIRECTION OUTPUT ;
    USE SIGNAL ;
    PORT
      LAYER M4 ;
        RECT  84.156 26.544 84.24 26.568 ;
    END
  END cut_7636
  PIN cut_7637
    DIRECTION OUTPUT ;
    USE SIGNAL ;
    PORT
      LAYER M4 ;
        RECT  84.156 26.64 84.24 26.664 ;
    END
  END cut_7637
  PIN cut_7638
    DIRECTION OUTPUT ;
    USE SIGNAL ;
    PORT
      LAYER M4 ;
        RECT  84.156 26.736 84.24 26.76 ;
    END
  END cut_7638
  PIN cut_7639
    DIRECTION OUTPUT ;
    USE SIGNAL ;
    PORT
      LAYER M4 ;
        RECT  84.156 26.832 84.24 26.856 ;
    END
  END cut_7639
  PIN cut_7640
    DIRECTION OUTPUT ;
    USE SIGNAL ;
    PORT
      LAYER M4 ;
        RECT  84.156 26.928 84.24 26.952 ;
    END
  END cut_7640
  PIN cut_7641
    DIRECTION OUTPUT ;
    USE SIGNAL ;
    PORT
      LAYER M4 ;
        RECT  84.156 27.024 84.24 27.048 ;
    END
  END cut_7641
  PIN cut_7642
    DIRECTION OUTPUT ;
    USE SIGNAL ;
    PORT
      LAYER M4 ;
        RECT  84.156 27.12 84.24 27.144 ;
    END
  END cut_7642
  PIN cut_7643
    DIRECTION OUTPUT ;
    USE SIGNAL ;
    PORT
      LAYER M4 ;
        RECT  84.156 27.216 84.24 27.24 ;
    END
  END cut_7643
  PIN cut_7644
    DIRECTION OUTPUT ;
    USE SIGNAL ;
    PORT
      LAYER M4 ;
        RECT  84.156 27.312 84.24 27.336 ;
    END
  END cut_7644
  PIN cut_7645
    DIRECTION OUTPUT ;
    USE SIGNAL ;
    PORT
      LAYER M4 ;
        RECT  84.156 27.408 84.24 27.432 ;
    END
  END cut_7645
  PIN cut_7646
    DIRECTION OUTPUT ;
    USE SIGNAL ;
    PORT
      LAYER M4 ;
        RECT  84.156 27.504 84.24 27.528 ;
    END
  END cut_7646
  PIN cut_7647
    DIRECTION OUTPUT ;
    USE SIGNAL ;
    PORT
      LAYER M4 ;
        RECT  84.156 27.6 84.24 27.624 ;
    END
  END cut_7647
  PIN cut_7648
    DIRECTION OUTPUT ;
    USE SIGNAL ;
    PORT
      LAYER M4 ;
        RECT  84.156 27.696 84.24 27.72 ;
    END
  END cut_7648
  PIN cut_7649
    DIRECTION OUTPUT ;
    USE SIGNAL ;
    PORT
      LAYER M4 ;
        RECT  84.156 27.792 84.24 27.816 ;
    END
  END cut_7649
  PIN cut_7650
    DIRECTION OUTPUT ;
    USE SIGNAL ;
    PORT
      LAYER M4 ;
        RECT  84.156 27.888 84.24 27.912 ;
    END
  END cut_7650
  PIN cut_7651
    DIRECTION OUTPUT ;
    USE SIGNAL ;
    PORT
      LAYER M4 ;
        RECT  84.156 27.984 84.24 28.008 ;
    END
  END cut_7651
  PIN cut_7652
    DIRECTION OUTPUT ;
    USE SIGNAL ;
    PORT
      LAYER M4 ;
        RECT  84.156 28.08 84.24 28.104 ;
    END
  END cut_7652
  PIN cut_7653
    DIRECTION OUTPUT ;
    USE SIGNAL ;
    PORT
      LAYER M4 ;
        RECT  84.156 28.176 84.24 28.2 ;
    END
  END cut_7653
  PIN cut_7654
    DIRECTION OUTPUT ;
    USE SIGNAL ;
    PORT
      LAYER M4 ;
        RECT  84.156 28.272 84.24 28.296 ;
    END
  END cut_7654
  PIN cut_7655
    DIRECTION OUTPUT ;
    USE SIGNAL ;
    PORT
      LAYER M4 ;
        RECT  84.156 28.368 84.24 28.392 ;
    END
  END cut_7655
  PIN cut_7656
    DIRECTION OUTPUT ;
    USE SIGNAL ;
    PORT
      LAYER M4 ;
        RECT  84.156 28.464 84.24 28.488 ;
    END
  END cut_7656
  PIN cut_7657
    DIRECTION OUTPUT ;
    USE SIGNAL ;
    PORT
      LAYER M4 ;
        RECT  84.156 28.56 84.24 28.584 ;
    END
  END cut_7657
  PIN cut_7658
    DIRECTION OUTPUT ;
    USE SIGNAL ;
    PORT
      LAYER M4 ;
        RECT  84.156 28.656 84.24 28.68 ;
    END
  END cut_7658
  PIN cut_7659
    DIRECTION OUTPUT ;
    USE SIGNAL ;
    PORT
      LAYER M4 ;
        RECT  84.156 28.752 84.24 28.776 ;
    END
  END cut_7659
  PIN cut_7660
    DIRECTION OUTPUT ;
    USE SIGNAL ;
    PORT
      LAYER M4 ;
        RECT  84.156 28.848 84.24 28.872 ;
    END
  END cut_7660
  PIN cut_7661
    DIRECTION OUTPUT ;
    USE SIGNAL ;
    PORT
      LAYER M4 ;
        RECT  84.156 28.944 84.24 28.968 ;
    END
  END cut_7661
  PIN cut_7662
    DIRECTION OUTPUT ;
    USE SIGNAL ;
    PORT
      LAYER M4 ;
        RECT  84.156 29.04 84.24 29.064 ;
    END
  END cut_7662
  PIN cut_7663
    DIRECTION OUTPUT ;
    USE SIGNAL ;
    PORT
      LAYER M4 ;
        RECT  84.156 48.336 84.24 48.36 ;
    END
  END cut_7663
  PIN cut_7664
    DIRECTION OUTPUT ;
    USE SIGNAL ;
    PORT
      LAYER M4 ;
        RECT  84.156 48.432 84.24 48.456 ;
    END
  END cut_7664
  PIN cut_7665
    DIRECTION OUTPUT ;
    USE SIGNAL ;
    PORT
      LAYER M4 ;
        RECT  84.156 48.528 84.24 48.552 ;
    END
  END cut_7665
  PIN cut_7666
    DIRECTION OUTPUT ;
    USE SIGNAL ;
    PORT
      LAYER M4 ;
        RECT  84.156 48.624 84.24 48.648 ;
    END
  END cut_7666
  PIN cut_7667
    DIRECTION OUTPUT ;
    USE SIGNAL ;
    PORT
      LAYER M4 ;
        RECT  84.156 48.72 84.24 48.744 ;
    END
  END cut_7667
  PIN cut_7668
    DIRECTION OUTPUT ;
    USE SIGNAL ;
    PORT
      LAYER M4 ;
        RECT  84.156 48.816 84.24 48.84 ;
    END
  END cut_7668
  PIN cut_7669
    DIRECTION OUTPUT ;
    USE SIGNAL ;
    PORT
      LAYER M4 ;
        RECT  84.156 48.912 84.24 48.936 ;
    END
  END cut_7669
  PIN cut_7670
    DIRECTION OUTPUT ;
    USE SIGNAL ;
    PORT
      LAYER M4 ;
        RECT  84.156 49.008 84.24 49.032 ;
    END
  END cut_7670
  PIN cut_7671
    DIRECTION OUTPUT ;
    USE SIGNAL ;
    PORT
      LAYER M4 ;
        RECT  84.156 49.104 84.24 49.128 ;
    END
  END cut_7671
  PIN cut_7672
    DIRECTION OUTPUT ;
    USE SIGNAL ;
    PORT
      LAYER M4 ;
        RECT  84.156 49.2 84.24 49.224 ;
    END
  END cut_7672
  PIN cut_7673
    DIRECTION OUTPUT ;
    USE SIGNAL ;
    PORT
      LAYER M4 ;
        RECT  84.156 49.296 84.24 49.32 ;
    END
  END cut_7673
  PIN cut_7674
    DIRECTION OUTPUT ;
    USE SIGNAL ;
    PORT
      LAYER M4 ;
        RECT  84.156 49.392 84.24 49.416 ;
    END
  END cut_7674
  PIN cut_7675
    DIRECTION OUTPUT ;
    USE SIGNAL ;
    PORT
      LAYER M4 ;
        RECT  84.156 49.488 84.24 49.512 ;
    END
  END cut_7675
  PIN cut_7676
    DIRECTION OUTPUT ;
    USE SIGNAL ;
    PORT
      LAYER M4 ;
        RECT  84.156 49.584 84.24 49.608 ;
    END
  END cut_7676
  PIN cut_7677
    DIRECTION OUTPUT ;
    USE SIGNAL ;
    PORT
      LAYER M4 ;
        RECT  84.156 49.68 84.24 49.704 ;
    END
  END cut_7677
  PIN cut_7678
    DIRECTION OUTPUT ;
    USE SIGNAL ;
    PORT
      LAYER M4 ;
        RECT  84.156 49.776 84.24 49.8 ;
    END
  END cut_7678
  PIN cut_7679
    DIRECTION OUTPUT ;
    USE SIGNAL ;
    PORT
      LAYER M4 ;
        RECT  84.156 49.872 84.24 49.896 ;
    END
  END cut_7679
  PIN cut_7680
    DIRECTION OUTPUT ;
    USE SIGNAL ;
    PORT
      LAYER M4 ;
        RECT  84.156 49.968 84.24 49.992 ;
    END
  END cut_7680
  PIN cut_7681
    DIRECTION OUTPUT ;
    USE SIGNAL ;
    PORT
      LAYER M4 ;
        RECT  84.156 50.064 84.24 50.088 ;
    END
  END cut_7681
  PIN cut_7682
    DIRECTION OUTPUT ;
    USE SIGNAL ;
    PORT
      LAYER M4 ;
        RECT  84.156 50.16 84.24 50.184 ;
    END
  END cut_7682
  PIN cut_7683
    DIRECTION OUTPUT ;
    USE SIGNAL ;
    PORT
      LAYER M4 ;
        RECT  84.156 50.256 84.24 50.28 ;
    END
  END cut_7683
  PIN cut_7684
    DIRECTION OUTPUT ;
    USE SIGNAL ;
    PORT
      LAYER M4 ;
        RECT  84.156 50.352 84.24 50.376 ;
    END
  END cut_7684
  PIN cut_7685
    DIRECTION OUTPUT ;
    USE SIGNAL ;
    PORT
      LAYER M4 ;
        RECT  84.156 50.448 84.24 50.472 ;
    END
  END cut_7685
  PIN cut_7686
    DIRECTION OUTPUT ;
    USE SIGNAL ;
    PORT
      LAYER M4 ;
        RECT  84.156 50.544 84.24 50.568 ;
    END
  END cut_7686
  PIN cut_7687
    DIRECTION OUTPUT ;
    USE SIGNAL ;
    PORT
      LAYER M4 ;
        RECT  84.156 50.64 84.24 50.664 ;
    END
  END cut_7687
  PIN cut_7688
    DIRECTION OUTPUT ;
    USE SIGNAL ;
    PORT
      LAYER M4 ;
        RECT  84.156 50.736 84.24 50.76 ;
    END
  END cut_7688
  PIN cut_7689
    DIRECTION OUTPUT ;
    USE SIGNAL ;
    PORT
      LAYER M4 ;
        RECT  84.156 50.832 84.24 50.856 ;
    END
  END cut_7689
  PIN cut_7690
    DIRECTION OUTPUT ;
    USE SIGNAL ;
    PORT
      LAYER M4 ;
        RECT  84.156 50.928 84.24 50.952 ;
    END
  END cut_7690
  PIN cut_7691
    DIRECTION OUTPUT ;
    USE SIGNAL ;
    PORT
      LAYER M4 ;
        RECT  84.156 51.024 84.24 51.048 ;
    END
  END cut_7691
  PIN cut_7692
    DIRECTION OUTPUT ;
    USE SIGNAL ;
    PORT
      LAYER M4 ;
        RECT  84.156 51.12 84.24 51.144 ;
    END
  END cut_7692
  PIN cut_7693
    DIRECTION OUTPUT ;
    USE SIGNAL ;
    PORT
      LAYER M4 ;
        RECT  84.156 51.216 84.24 51.24 ;
    END
  END cut_7693
  PIN cut_7694
    DIRECTION OUTPUT ;
    USE SIGNAL ;
    PORT
      LAYER M4 ;
        RECT  84.156 51.312 84.24 51.336 ;
    END
  END cut_7694
  PIN cut_7695
    DIRECTION OUTPUT ;
    USE SIGNAL ;
    PORT
      LAYER M4 ;
        RECT  84.156 32.208 84.24 32.232 ;
    END
  END cut_7695
  PIN cut_7696
    DIRECTION OUTPUT ;
    USE SIGNAL ;
    PORT
      LAYER M4 ;
        RECT  84.156 32.304 84.24 32.328 ;
    END
  END cut_7696
  PIN cut_7697
    DIRECTION OUTPUT ;
    USE SIGNAL ;
    PORT
      LAYER M4 ;
        RECT  84.156 32.4 84.24 32.424 ;
    END
  END cut_7697
  PIN cut_7698
    DIRECTION OUTPUT ;
    USE SIGNAL ;
    PORT
      LAYER M4 ;
        RECT  84.156 32.496 84.24 32.52 ;
    END
  END cut_7698
  PIN cut_7699
    DIRECTION OUTPUT ;
    USE SIGNAL ;
    PORT
      LAYER M4 ;
        RECT  84.156 32.592 84.24 32.616 ;
    END
  END cut_7699
  PIN cut_7700
    DIRECTION OUTPUT ;
    USE SIGNAL ;
    PORT
      LAYER M4 ;
        RECT  84.156 32.688 84.24 32.712 ;
    END
  END cut_7700
  PIN cut_7701
    DIRECTION OUTPUT ;
    USE SIGNAL ;
    PORT
      LAYER M4 ;
        RECT  84.156 32.784 84.24 32.808 ;
    END
  END cut_7701
  PIN cut_7702
    DIRECTION OUTPUT ;
    USE SIGNAL ;
    PORT
      LAYER M4 ;
        RECT  84.156 32.88 84.24 32.904 ;
    END
  END cut_7702
  PIN cut_7703
    DIRECTION OUTPUT ;
    USE SIGNAL ;
    PORT
      LAYER M4 ;
        RECT  84.156 32.976 84.24 33 ;
    END
  END cut_7703
  PIN cut_7704
    DIRECTION OUTPUT ;
    USE SIGNAL ;
    PORT
      LAYER M4 ;
        RECT  84.156 33.072 84.24 33.096 ;
    END
  END cut_7704
  PIN cut_7705
    DIRECTION OUTPUT ;
    USE SIGNAL ;
    PORT
      LAYER M4 ;
        RECT  84.156 33.168 84.24 33.192 ;
    END
  END cut_7705
  PIN cut_7706
    DIRECTION OUTPUT ;
    USE SIGNAL ;
    PORT
      LAYER M4 ;
        RECT  84.156 33.264 84.24 33.288 ;
    END
  END cut_7706
  PIN cut_7707
    DIRECTION OUTPUT ;
    USE SIGNAL ;
    PORT
      LAYER M4 ;
        RECT  84.156 33.36 84.24 33.384 ;
    END
  END cut_7707
  PIN cut_7708
    DIRECTION OUTPUT ;
    USE SIGNAL ;
    PORT
      LAYER M4 ;
        RECT  84.156 33.456 84.24 33.48 ;
    END
  END cut_7708
  PIN cut_7709
    DIRECTION OUTPUT ;
    USE SIGNAL ;
    PORT
      LAYER M4 ;
        RECT  84.156 33.552 84.24 33.576 ;
    END
  END cut_7709
  PIN cut_7710
    DIRECTION OUTPUT ;
    USE SIGNAL ;
    PORT
      LAYER M4 ;
        RECT  84.156 33.648 84.24 33.672 ;
    END
  END cut_7710
  PIN cut_7711
    DIRECTION OUTPUT ;
    USE SIGNAL ;
    PORT
      LAYER M4 ;
        RECT  84.156 33.744 84.24 33.768 ;
    END
  END cut_7711
  PIN cut_7712
    DIRECTION OUTPUT ;
    USE SIGNAL ;
    PORT
      LAYER M4 ;
        RECT  84.156 33.84 84.24 33.864 ;
    END
  END cut_7712
  PIN cut_7713
    DIRECTION OUTPUT ;
    USE SIGNAL ;
    PORT
      LAYER M4 ;
        RECT  84.156 33.936 84.24 33.96 ;
    END
  END cut_7713
  PIN cut_7714
    DIRECTION OUTPUT ;
    USE SIGNAL ;
    PORT
      LAYER M4 ;
        RECT  84.156 34.032 84.24 34.056 ;
    END
  END cut_7714
  PIN cut_7715
    DIRECTION OUTPUT ;
    USE SIGNAL ;
    PORT
      LAYER M4 ;
        RECT  84.156 34.128 84.24 34.152 ;
    END
  END cut_7715
  PIN cut_7716
    DIRECTION OUTPUT ;
    USE SIGNAL ;
    PORT
      LAYER M4 ;
        RECT  84.156 34.224 84.24 34.248 ;
    END
  END cut_7716
  PIN cut_7717
    DIRECTION OUTPUT ;
    USE SIGNAL ;
    PORT
      LAYER M4 ;
        RECT  84.156 34.32 84.24 34.344 ;
    END
  END cut_7717
  PIN cut_7718
    DIRECTION OUTPUT ;
    USE SIGNAL ;
    PORT
      LAYER M4 ;
        RECT  84.156 34.416 84.24 34.44 ;
    END
  END cut_7718
  PIN cut_7719
    DIRECTION OUTPUT ;
    USE SIGNAL ;
    PORT
      LAYER M4 ;
        RECT  84.156 34.512 84.24 34.536 ;
    END
  END cut_7719
  PIN cut_7720
    DIRECTION OUTPUT ;
    USE SIGNAL ;
    PORT
      LAYER M4 ;
        RECT  84.156 34.608 84.24 34.632 ;
    END
  END cut_7720
  PIN cut_7721
    DIRECTION OUTPUT ;
    USE SIGNAL ;
    PORT
      LAYER M4 ;
        RECT  84.156 34.704 84.24 34.728 ;
    END
  END cut_7721
  PIN cut_7722
    DIRECTION OUTPUT ;
    USE SIGNAL ;
    PORT
      LAYER M4 ;
        RECT  84.156 34.8 84.24 34.824 ;
    END
  END cut_7722
  PIN cut_7723
    DIRECTION OUTPUT ;
    USE SIGNAL ;
    PORT
      LAYER M4 ;
        RECT  84.156 34.896 84.24 34.92 ;
    END
  END cut_7723
  PIN cut_7724
    DIRECTION OUTPUT ;
    USE SIGNAL ;
    PORT
      LAYER M4 ;
        RECT  84.156 34.992 84.24 35.016 ;
    END
  END cut_7724
  PIN cut_7725
    DIRECTION OUTPUT ;
    USE SIGNAL ;
    PORT
      LAYER M4 ;
        RECT  84.156 35.088 84.24 35.112 ;
    END
  END cut_7725
  PIN cut_7726
    DIRECTION OUTPUT ;
    USE SIGNAL ;
    PORT
      LAYER M4 ;
        RECT  84.156 35.184 84.24 35.208 ;
    END
  END cut_7726
  PIN cut_7727
    DIRECTION OUTPUT ;
    USE SIGNAL ;
    PORT
      LAYER M4 ;
        RECT  84.156 19.92 84.24 19.944 ;
    END
  END cut_7727
  PIN cut_7728
    DIRECTION OUTPUT ;
    USE SIGNAL ;
    PORT
      LAYER M4 ;
        RECT  84.156 20.016 84.24 20.04 ;
    END
  END cut_7728
  PIN cut_7729
    DIRECTION OUTPUT ;
    USE SIGNAL ;
    PORT
      LAYER M4 ;
        RECT  84.156 20.112 84.24 20.136 ;
    END
  END cut_7729
  PIN cut_7730
    DIRECTION OUTPUT ;
    USE SIGNAL ;
    PORT
      LAYER M4 ;
        RECT  84.156 20.208 84.24 20.232 ;
    END
  END cut_7730
  PIN cut_7731
    DIRECTION OUTPUT ;
    USE SIGNAL ;
    PORT
      LAYER M4 ;
        RECT  84.156 20.304 84.24 20.328 ;
    END
  END cut_7731
  PIN cut_7732
    DIRECTION OUTPUT ;
    USE SIGNAL ;
    PORT
      LAYER M4 ;
        RECT  84.156 20.4 84.24 20.424 ;
    END
  END cut_7732
  PIN cut_7733
    DIRECTION OUTPUT ;
    USE SIGNAL ;
    PORT
      LAYER M4 ;
        RECT  84.156 20.496 84.24 20.52 ;
    END
  END cut_7733
  PIN cut_7734
    DIRECTION OUTPUT ;
    USE SIGNAL ;
    PORT
      LAYER M4 ;
        RECT  84.156 20.592 84.24 20.616 ;
    END
  END cut_7734
  PIN cut_7735
    DIRECTION OUTPUT ;
    USE SIGNAL ;
    PORT
      LAYER M4 ;
        RECT  84.156 20.688 84.24 20.712 ;
    END
  END cut_7735
  PIN cut_7736
    DIRECTION OUTPUT ;
    USE SIGNAL ;
    PORT
      LAYER M4 ;
        RECT  84.156 20.784 84.24 20.808 ;
    END
  END cut_7736
  PIN cut_7737
    DIRECTION OUTPUT ;
    USE SIGNAL ;
    PORT
      LAYER M4 ;
        RECT  84.156 20.88 84.24 20.904 ;
    END
  END cut_7737
  PIN cut_7738
    DIRECTION OUTPUT ;
    USE SIGNAL ;
    PORT
      LAYER M4 ;
        RECT  84.156 20.976 84.24 21 ;
    END
  END cut_7738
  PIN cut_7739
    DIRECTION OUTPUT ;
    USE SIGNAL ;
    PORT
      LAYER M4 ;
        RECT  84.156 21.072 84.24 21.096 ;
    END
  END cut_7739
  PIN cut_7740
    DIRECTION OUTPUT ;
    USE SIGNAL ;
    PORT
      LAYER M4 ;
        RECT  84.156 21.168 84.24 21.192 ;
    END
  END cut_7740
  PIN cut_7741
    DIRECTION OUTPUT ;
    USE SIGNAL ;
    PORT
      LAYER M4 ;
        RECT  84.156 21.264 84.24 21.288 ;
    END
  END cut_7741
  PIN cut_7742
    DIRECTION OUTPUT ;
    USE SIGNAL ;
    PORT
      LAYER M4 ;
        RECT  84.156 21.36 84.24 21.384 ;
    END
  END cut_7742
  PIN cut_7743
    DIRECTION OUTPUT ;
    USE SIGNAL ;
    PORT
      LAYER M4 ;
        RECT  84.156 21.456 84.24 21.48 ;
    END
  END cut_7743
  PIN cut_7744
    DIRECTION OUTPUT ;
    USE SIGNAL ;
    PORT
      LAYER M4 ;
        RECT  84.156 21.552 84.24 21.576 ;
    END
  END cut_7744
  PIN cut_7745
    DIRECTION OUTPUT ;
    USE SIGNAL ;
    PORT
      LAYER M4 ;
        RECT  84.156 21.648 84.24 21.672 ;
    END
  END cut_7745
  PIN cut_7746
    DIRECTION OUTPUT ;
    USE SIGNAL ;
    PORT
      LAYER M4 ;
        RECT  84.156 21.744 84.24 21.768 ;
    END
  END cut_7746
  PIN cut_7747
    DIRECTION OUTPUT ;
    USE SIGNAL ;
    PORT
      LAYER M4 ;
        RECT  84.156 21.84 84.24 21.864 ;
    END
  END cut_7747
  PIN cut_7748
    DIRECTION OUTPUT ;
    USE SIGNAL ;
    PORT
      LAYER M4 ;
        RECT  84.156 21.936 84.24 21.96 ;
    END
  END cut_7748
  PIN cut_7749
    DIRECTION OUTPUT ;
    USE SIGNAL ;
    PORT
      LAYER M4 ;
        RECT  84.156 22.032 84.24 22.056 ;
    END
  END cut_7749
  PIN cut_7750
    DIRECTION OUTPUT ;
    USE SIGNAL ;
    PORT
      LAYER M4 ;
        RECT  84.156 22.128 84.24 22.152 ;
    END
  END cut_7750
  PIN cut_7751
    DIRECTION OUTPUT ;
    USE SIGNAL ;
    PORT
      LAYER M4 ;
        RECT  84.156 22.224 84.24 22.248 ;
    END
  END cut_7751
  PIN cut_7752
    DIRECTION OUTPUT ;
    USE SIGNAL ;
    PORT
      LAYER M4 ;
        RECT  84.156 22.32 84.24 22.344 ;
    END
  END cut_7752
  PIN cut_7753
    DIRECTION OUTPUT ;
    USE SIGNAL ;
    PORT
      LAYER M4 ;
        RECT  84.156 22.416 84.24 22.44 ;
    END
  END cut_7753
  PIN cut_7754
    DIRECTION OUTPUT ;
    USE SIGNAL ;
    PORT
      LAYER M4 ;
        RECT  84.156 22.512 84.24 22.536 ;
    END
  END cut_7754
  PIN cut_7755
    DIRECTION OUTPUT ;
    USE SIGNAL ;
    PORT
      LAYER M4 ;
        RECT  84.156 22.608 84.24 22.632 ;
    END
  END cut_7755
  PIN cut_7756
    DIRECTION OUTPUT ;
    USE SIGNAL ;
    PORT
      LAYER M4 ;
        RECT  84.156 22.704 84.24 22.728 ;
    END
  END cut_7756
  PIN cut_7757
    DIRECTION OUTPUT ;
    USE SIGNAL ;
    PORT
      LAYER M4 ;
        RECT  84.156 22.8 84.24 22.824 ;
    END
  END cut_7757
  PIN cut_7758
    DIRECTION OUTPUT ;
    USE SIGNAL ;
    PORT
      LAYER M4 ;
        RECT  84.156 22.896 84.24 22.92 ;
    END
  END cut_7758
  PIN cut_7759
    DIRECTION OUTPUT ;
    USE SIGNAL ;
    PORT
      LAYER M4 ;
        RECT  84.156 22.992 84.24 23.016 ;
    END
  END cut_7759
  PIN cut_7760
    DIRECTION OUTPUT ;
    USE SIGNAL ;
    PORT
      LAYER M4 ;
        RECT  84.156 23.088 84.24 23.112 ;
    END
  END cut_7760
  PIN cut_7761
    DIRECTION OUTPUT ;
    USE SIGNAL ;
    PORT
      LAYER M4 ;
        RECT  84.156 23.184 84.24 23.208 ;
    END
  END cut_7761
  PIN cut_7762
    DIRECTION OUTPUT ;
    USE SIGNAL ;
    PORT
      LAYER M4 ;
        RECT  84.156 23.28 84.24 23.304 ;
    END
  END cut_7762
  PIN cut_7763
    DIRECTION OUTPUT ;
    USE SIGNAL ;
    PORT
      LAYER M4 ;
        RECT  84.156 23.376 84.24 23.4 ;
    END
  END cut_7763
  PIN cut_7764
    DIRECTION OUTPUT ;
    USE SIGNAL ;
    PORT
      LAYER M4 ;
        RECT  84.156 23.472 84.24 23.496 ;
    END
  END cut_7764
  PIN cut_7765
    DIRECTION OUTPUT ;
    USE SIGNAL ;
    PORT
      LAYER M4 ;
        RECT  84.156 23.568 84.24 23.592 ;
    END
  END cut_7765
  PIN cut_7766
    DIRECTION OUTPUT ;
    USE SIGNAL ;
    PORT
      LAYER M4 ;
        RECT  84.156 23.664 84.24 23.688 ;
    END
  END cut_7766
  PIN cut_7767
    DIRECTION OUTPUT ;
    USE SIGNAL ;
    PORT
      LAYER M4 ;
        RECT  84.156 23.76 84.24 23.784 ;
    END
  END cut_7767
  PIN cut_7768
    DIRECTION OUTPUT ;
    USE SIGNAL ;
    PORT
      LAYER M5 ;
        RECT  34.224 73.356 34.248 73.44 ;
    END
  END cut_7768
  PIN cut_7873
    DIRECTION OUTPUT ;
    USE SIGNAL ;
    PORT
      LAYER M4 ;
        RECT  84.156 23.856 84.24 23.88 ;
    END
  END cut_7873
  PIN cut_7874
    DIRECTION OUTPUT ;
    USE SIGNAL ;
    PORT
      LAYER M4 ;
        RECT  84.156 23.952 84.24 23.976 ;
    END
  END cut_7874
  PIN cut_7875
    DIRECTION OUTPUT ;
    USE SIGNAL ;
    PORT
      LAYER M4 ;
        RECT  84.156 24.048 84.24 24.072 ;
    END
  END cut_7875
  PIN cut_7876
    DIRECTION OUTPUT ;
    USE SIGNAL ;
    PORT
      LAYER M4 ;
        RECT  84.156 24.144 84.24 24.168 ;
    END
  END cut_7876
  PIN cut_7877
    DIRECTION OUTPUT ;
    USE SIGNAL ;
    PORT
      LAYER M4 ;
        RECT  84.156 24.24 84.24 24.264 ;
    END
  END cut_7877
  PIN cut_7878
    DIRECTION OUTPUT ;
    USE SIGNAL ;
    PORT
      LAYER M4 ;
        RECT  84.156 24.336 84.24 24.36 ;
    END
  END cut_7878
  PIN cut_7879
    DIRECTION OUTPUT ;
    USE SIGNAL ;
    PORT
      LAYER M4 ;
        RECT  84.156 24.432 84.24 24.456 ;
    END
  END cut_7879
  PIN cut_7880
    DIRECTION OUTPUT ;
    USE SIGNAL ;
    PORT
      LAYER M4 ;
        RECT  84.156 24.528 84.24 24.552 ;
    END
  END cut_7880
  PIN cut_7881
    DIRECTION OUTPUT ;
    USE SIGNAL ;
    PORT
      LAYER M4 ;
        RECT  84.156 24.624 84.24 24.648 ;
    END
  END cut_7881
  PIN cut_7882
    DIRECTION OUTPUT ;
    USE SIGNAL ;
    PORT
      LAYER M4 ;
        RECT  84.156 24.72 84.24 24.744 ;
    END
  END cut_7882
  PIN cut_7883
    DIRECTION OUTPUT ;
    USE SIGNAL ;
    PORT
      LAYER M4 ;
        RECT  84.156 24.816 84.24 24.84 ;
    END
  END cut_7883
  PIN cut_7884
    DIRECTION OUTPUT ;
    USE SIGNAL ;
    PORT
      LAYER M4 ;
        RECT  84.156 24.912 84.24 24.936 ;
    END
  END cut_7884
  PIN cut_7885
    DIRECTION OUTPUT ;
    USE SIGNAL ;
    PORT
      LAYER M4 ;
        RECT  84.156 25.008 84.24 25.032 ;
    END
  END cut_7885
  PIN cut_7886
    DIRECTION OUTPUT ;
    USE SIGNAL ;
    PORT
      LAYER M4 ;
        RECT  84.156 25.104 84.24 25.128 ;
    END
  END cut_7886
  PIN cut_7887
    DIRECTION OUTPUT ;
    USE SIGNAL ;
    PORT
      LAYER M4 ;
        RECT  84.156 25.2 84.24 25.224 ;
    END
  END cut_7887
  PIN cut_7888
    DIRECTION OUTPUT ;
    USE SIGNAL ;
    PORT
      LAYER M4 ;
        RECT  84.156 25.296 84.24 25.32 ;
    END
  END cut_7888
  PIN cut_7889
    DIRECTION OUTPUT ;
    USE SIGNAL ;
    PORT
      LAYER M4 ;
        RECT  84.156 25.392 84.24 25.416 ;
    END
  END cut_7889
  PIN cut_7890
    DIRECTION OUTPUT ;
    USE SIGNAL ;
    PORT
      LAYER M4 ;
        RECT  84.156 25.488 84.24 25.512 ;
    END
  END cut_7890
  PIN cut_7891
    DIRECTION OUTPUT ;
    USE SIGNAL ;
    PORT
      LAYER M4 ;
        RECT  84.156 25.584 84.24 25.608 ;
    END
  END cut_7891
  PIN cut_7892
    DIRECTION OUTPUT ;
    USE SIGNAL ;
    PORT
      LAYER M4 ;
        RECT  84.156 25.68 84.24 25.704 ;
    END
  END cut_7892
  PIN cut_7893
    DIRECTION OUTPUT ;
    USE SIGNAL ;
    PORT
      LAYER M4 ;
        RECT  84.156 25.776 84.24 25.8 ;
    END
  END cut_7893
  PIN cut_7894
    DIRECTION OUTPUT ;
    USE SIGNAL ;
    PORT
      LAYER M4 ;
        RECT  84.156 25.872 84.24 25.896 ;
    END
  END cut_7894
  PIN cut_7895
    DIRECTION OUTPUT ;
    USE SIGNAL ;
    PORT
      LAYER M4 ;
        RECT  84.156 25.968 84.24 25.992 ;
    END
  END cut_7895
  PIN cut_7896
    DIRECTION OUTPUT ;
    USE SIGNAL ;
    PORT
      LAYER M4 ;
        RECT  84.156 29.136 84.24 29.16 ;
    END
  END cut_7896
  PIN cut_7897
    DIRECTION OUTPUT ;
    USE SIGNAL ;
    PORT
      LAYER M4 ;
        RECT  84.156 29.232 84.24 29.256 ;
    END
  END cut_7897
  PIN cut_7898
    DIRECTION OUTPUT ;
    USE SIGNAL ;
    PORT
      LAYER M4 ;
        RECT  84.156 29.328 84.24 29.352 ;
    END
  END cut_7898
  PIN cut_8
    DIRECTION INPUT ;
    USE SIGNAL ;
    PORT
      LAYER M4 ;
        RECT  0 19.248 0.084 19.272 ;
    END
  END cut_8
  PIN cut_8003
    DIRECTION OUTPUT ;
    USE SIGNAL ;
    PORT
      LAYER M4 ;
        RECT  84.156 29.424 84.24 29.448 ;
    END
  END cut_8003
  PIN cut_8004
    DIRECTION OUTPUT ;
    USE SIGNAL ;
    PORT
      LAYER M4 ;
        RECT  84.156 29.52 84.24 29.544 ;
    END
  END cut_8004
  PIN cut_8005
    DIRECTION OUTPUT ;
    USE SIGNAL ;
    PORT
      LAYER M4 ;
        RECT  84.156 29.616 84.24 29.64 ;
    END
  END cut_8005
  PIN cut_8006
    DIRECTION OUTPUT ;
    USE SIGNAL ;
    PORT
      LAYER M4 ;
        RECT  84.156 29.712 84.24 29.736 ;
    END
  END cut_8006
  PIN cut_8007
    DIRECTION OUTPUT ;
    USE SIGNAL ;
    PORT
      LAYER M4 ;
        RECT  84.156 29.808 84.24 29.832 ;
    END
  END cut_8007
  PIN cut_8008
    DIRECTION OUTPUT ;
    USE SIGNAL ;
    PORT
      LAYER M4 ;
        RECT  84.156 29.904 84.24 29.928 ;
    END
  END cut_8008
  PIN cut_8009
    DIRECTION OUTPUT ;
    USE SIGNAL ;
    PORT
      LAYER M4 ;
        RECT  84.156 30 84.24 30.024 ;
    END
  END cut_8009
  PIN cut_8010
    DIRECTION OUTPUT ;
    USE SIGNAL ;
    PORT
      LAYER M4 ;
        RECT  84.156 30.096 84.24 30.12 ;
    END
  END cut_8010
  PIN cut_8011
    DIRECTION OUTPUT ;
    USE SIGNAL ;
    PORT
      LAYER M4 ;
        RECT  84.156 30.192 84.24 30.216 ;
    END
  END cut_8011
  PIN cut_8012
    DIRECTION OUTPUT ;
    USE SIGNAL ;
    PORT
      LAYER M4 ;
        RECT  84.156 30.288 84.24 30.312 ;
    END
  END cut_8012
  PIN cut_8013
    DIRECTION OUTPUT ;
    USE SIGNAL ;
    PORT
      LAYER M4 ;
        RECT  84.156 30.384 84.24 30.408 ;
    END
  END cut_8013
  PIN cut_8014
    DIRECTION OUTPUT ;
    USE SIGNAL ;
    PORT
      LAYER M4 ;
        RECT  84.156 30.48 84.24 30.504 ;
    END
  END cut_8014
  PIN cut_8015
    DIRECTION OUTPUT ;
    USE SIGNAL ;
    PORT
      LAYER M4 ;
        RECT  84.156 30.576 84.24 30.6 ;
    END
  END cut_8015
  PIN cut_8016
    DIRECTION OUTPUT ;
    USE SIGNAL ;
    PORT
      LAYER M4 ;
        RECT  84.156 30.672 84.24 30.696 ;
    END
  END cut_8016
  PIN cut_8017
    DIRECTION OUTPUT ;
    USE SIGNAL ;
    PORT
      LAYER M4 ;
        RECT  84.156 30.768 84.24 30.792 ;
    END
  END cut_8017
  PIN cut_8018
    DIRECTION OUTPUT ;
    USE SIGNAL ;
    PORT
      LAYER M4 ;
        RECT  84.156 30.864 84.24 30.888 ;
    END
  END cut_8018
  PIN cut_8019
    DIRECTION OUTPUT ;
    USE SIGNAL ;
    PORT
      LAYER M4 ;
        RECT  84.156 30.96 84.24 30.984 ;
    END
  END cut_8019
  PIN cut_8020
    DIRECTION OUTPUT ;
    USE SIGNAL ;
    PORT
      LAYER M4 ;
        RECT  84.156 31.056 84.24 31.08 ;
    END
  END cut_8020
  PIN cut_8021
    DIRECTION OUTPUT ;
    USE SIGNAL ;
    PORT
      LAYER M4 ;
        RECT  84.156 31.152 84.24 31.176 ;
    END
  END cut_8021
  PIN cut_8022
    DIRECTION OUTPUT ;
    USE SIGNAL ;
    PORT
      LAYER M4 ;
        RECT  84.156 31.248 84.24 31.272 ;
    END
  END cut_8022
  PIN cut_8023
    DIRECTION OUTPUT ;
    USE SIGNAL ;
    PORT
      LAYER M4 ;
        RECT  84.156 31.344 84.24 31.368 ;
    END
  END cut_8023
  PIN cut_8024
    DIRECTION OUTPUT ;
    USE SIGNAL ;
    PORT
      LAYER M4 ;
        RECT  84.156 31.44 84.24 31.464 ;
    END
  END cut_8024
  PIN cut_8025
    DIRECTION OUTPUT ;
    USE SIGNAL ;
    PORT
      LAYER M4 ;
        RECT  84.156 31.536 84.24 31.56 ;
    END
  END cut_8025
  PIN cut_8026
    DIRECTION OUTPUT ;
    USE SIGNAL ;
    PORT
      LAYER M4 ;
        RECT  84.156 31.632 84.24 31.656 ;
    END
  END cut_8026
  PIN cut_8027
    DIRECTION OUTPUT ;
    USE SIGNAL ;
    PORT
      LAYER M4 ;
        RECT  84.156 31.728 84.24 31.752 ;
    END
  END cut_8027
  PIN cut_8028
    DIRECTION OUTPUT ;
    USE SIGNAL ;
    PORT
      LAYER M4 ;
        RECT  84.156 31.824 84.24 31.848 ;
    END
  END cut_8028
  PIN cut_8382
    DIRECTION INPUT ;
    USE SIGNAL ;
    PORT
      LAYER M4 ;
        RECT  0 18.288 0.084 18.312 ;
    END
  END cut_8382
  PIN cut_8383
    DIRECTION INPUT ;
    USE SIGNAL ;
    PORT
      LAYER M4 ;
        RECT  0 18.384 0.084 18.408 ;
    END
  END cut_8383
  PIN cut_8386
    DIRECTION INPUT ;
    USE SIGNAL ;
    PORT
      LAYER M4 ;
        RECT  0 18.48 0.084 18.504 ;
    END
  END cut_8386
  PIN cut_8387
    DIRECTION INPUT ;
    USE SIGNAL ;
    PORT
      LAYER M4 ;
        RECT  0 18.576 0.084 18.6 ;
    END
  END cut_8387
  PIN cut_8440
    DIRECTION OUTPUT ;
    USE SIGNAL ;
    PORT
      LAYER M4 ;
        RECT  84.156 31.92 84.24 31.944 ;
    END
  END cut_8440
  PIN cut_8441
    DIRECTION OUTPUT ;
    USE SIGNAL ;
    PORT
      LAYER M4 ;
        RECT  84.156 32.016 84.24 32.04 ;
    END
  END cut_8441
  PIN cut_8442
    DIRECTION OUTPUT ;
    USE SIGNAL ;
    PORT
      LAYER M4 ;
        RECT  84.156 32.112 84.24 32.136 ;
    END
  END cut_8442
  PIN cut_8444
    DIRECTION INPUT ;
    USE SIGNAL ;
    PORT
      LAYER M4 ;
        RECT  0 18.672 0.084 18.696 ;
    END
  END cut_8444
  PIN cut_8445
    DIRECTION INPUT ;
    USE SIGNAL ;
    PORT
      LAYER M4 ;
        RECT  0 18.768 0.084 18.792 ;
    END
  END cut_8445
  PIN cut_8446
    DIRECTION INPUT ;
    USE SIGNAL ;
    PORT
      LAYER M4 ;
        RECT  0 18.864 0.084 18.888 ;
    END
  END cut_8446
  PIN cut_8447
    DIRECTION INPUT ;
    USE SIGNAL ;
    PORT
      LAYER M4 ;
        RECT  0 28.176 0.084 28.2 ;
    END
  END cut_8447
  PIN cut_8448
    DIRECTION INPUT ;
    USE SIGNAL ;
    PORT
      LAYER M4 ;
        RECT  0 28.272 0.084 28.296 ;
    END
  END cut_8448
  PIN cut_8449
    DIRECTION INPUT ;
    USE SIGNAL ;
    PORT
      LAYER M4 ;
        RECT  0 28.368 0.084 28.392 ;
    END
  END cut_8449
  PIN cut_8450
    DIRECTION INPUT ;
    USE SIGNAL ;
    PORT
      LAYER M4 ;
        RECT  0 28.464 0.084 28.488 ;
    END
  END cut_8450
  PIN cut_8451
    DIRECTION INPUT ;
    USE SIGNAL ;
    PORT
      LAYER M4 ;
        RECT  0 28.56 0.084 28.584 ;
    END
  END cut_8451
  PIN cut_8452
    DIRECTION INPUT ;
    USE SIGNAL ;
    PORT
      LAYER M4 ;
        RECT  0 28.656 0.084 28.68 ;
    END
  END cut_8452
  PIN cut_8453
    DIRECTION INPUT ;
    USE SIGNAL ;
    PORT
      LAYER M4 ;
        RECT  0 28.752 0.084 28.776 ;
    END
  END cut_8453
  PIN cut_8454
    DIRECTION INPUT ;
    USE SIGNAL ;
    PORT
      LAYER M4 ;
        RECT  0 28.848 0.084 28.872 ;
    END
  END cut_8454
  PIN cut_8455
    DIRECTION INPUT ;
    USE SIGNAL ;
    PORT
      LAYER M4 ;
        RECT  0 28.944 0.084 28.968 ;
    END
  END cut_8455
  PIN cut_8456
    DIRECTION INPUT ;
    USE SIGNAL ;
    PORT
      LAYER M4 ;
        RECT  0 29.04 0.084 29.064 ;
    END
  END cut_8456
  PIN cut_8457
    DIRECTION INPUT ;
    USE SIGNAL ;
    PORT
      LAYER M4 ;
        RECT  0 29.136 0.084 29.16 ;
    END
  END cut_8457
  PIN cut_8458
    DIRECTION INPUT ;
    USE SIGNAL ;
    PORT
      LAYER M4 ;
        RECT  0 29.232 0.084 29.256 ;
    END
  END cut_8458
  PIN cut_8459
    DIRECTION INPUT ;
    USE SIGNAL ;
    PORT
      LAYER M4 ;
        RECT  0 29.328 0.084 29.352 ;
    END
  END cut_8459
  PIN cut_8460
    DIRECTION INPUT ;
    USE SIGNAL ;
    PORT
      LAYER M4 ;
        RECT  0 29.424 0.084 29.448 ;
    END
  END cut_8460
  PIN cut_8461
    DIRECTION INPUT ;
    USE SIGNAL ;
    PORT
      LAYER M4 ;
        RECT  0 29.52 0.084 29.544 ;
    END
  END cut_8461
  PIN cut_8462
    DIRECTION INPUT ;
    USE SIGNAL ;
    PORT
      LAYER M4 ;
        RECT  0 29.616 0.084 29.64 ;
    END
  END cut_8462
  PIN cut_8463
    DIRECTION INPUT ;
    USE SIGNAL ;
    PORT
      LAYER M4 ;
        RECT  0 29.712 0.084 29.736 ;
    END
  END cut_8463
  PIN cut_8464
    DIRECTION INPUT ;
    USE SIGNAL ;
    PORT
      LAYER M4 ;
        RECT  0 29.808 0.084 29.832 ;
    END
  END cut_8464
  PIN cut_8465
    DIRECTION INPUT ;
    USE SIGNAL ;
    PORT
      LAYER M4 ;
        RECT  0 29.904 0.084 29.928 ;
    END
  END cut_8465
  PIN cut_8466
    DIRECTION INPUT ;
    USE SIGNAL ;
    PORT
      LAYER M4 ;
        RECT  0 30 0.084 30.024 ;
    END
  END cut_8466
  PIN cut_8467
    DIRECTION INPUT ;
    USE SIGNAL ;
    PORT
      LAYER M4 ;
        RECT  0 30.096 0.084 30.12 ;
    END
  END cut_8467
  PIN cut_8468
    DIRECTION INPUT ;
    USE SIGNAL ;
    PORT
      LAYER M4 ;
        RECT  0 30.192 0.084 30.216 ;
    END
  END cut_8468
  PIN cut_8469
    DIRECTION INPUT ;
    USE SIGNAL ;
    PORT
      LAYER M4 ;
        RECT  0 30.288 0.084 30.312 ;
    END
  END cut_8469
  PIN cut_8470
    DIRECTION INPUT ;
    USE SIGNAL ;
    PORT
      LAYER M4 ;
        RECT  0 30.384 0.084 30.408 ;
    END
  END cut_8470
  PIN cut_8471
    DIRECTION INPUT ;
    USE SIGNAL ;
    PORT
      LAYER M4 ;
        RECT  0 30.48 0.084 30.504 ;
    END
  END cut_8471
  PIN cut_8472
    DIRECTION INPUT ;
    USE SIGNAL ;
    PORT
      LAYER M4 ;
        RECT  0 30.576 0.084 30.6 ;
    END
  END cut_8472
  PIN cut_8473
    DIRECTION INPUT ;
    USE SIGNAL ;
    PORT
      LAYER M4 ;
        RECT  0 30.672 0.084 30.696 ;
    END
  END cut_8473
  PIN cut_8474
    DIRECTION INPUT ;
    USE SIGNAL ;
    PORT
      LAYER M4 ;
        RECT  0 30.768 0.084 30.792 ;
    END
  END cut_8474
  PIN cut_8475
    DIRECTION INPUT ;
    USE SIGNAL ;
    PORT
      LAYER M4 ;
        RECT  0 30.864 0.084 30.888 ;
    END
  END cut_8475
  PIN cut_8476
    DIRECTION INPUT ;
    USE SIGNAL ;
    PORT
      LAYER M4 ;
        RECT  0 30.96 0.084 30.984 ;
    END
  END cut_8476
  PIN cut_8477
    DIRECTION INPUT ;
    USE SIGNAL ;
    PORT
      LAYER M4 ;
        RECT  0 31.056 0.084 31.08 ;
    END
  END cut_8477
  PIN cut_8478
    DIRECTION INPUT ;
    USE SIGNAL ;
    PORT
      LAYER M4 ;
        RECT  0 31.152 0.084 31.176 ;
    END
  END cut_8478
  PIN cut_8479
    DIRECTION INPUT ;
    USE SIGNAL ;
    PORT
      LAYER M4 ;
        RECT  0 25.104 0.084 25.128 ;
    END
  END cut_8479
  PIN cut_8480
    DIRECTION INPUT ;
    USE SIGNAL ;
    PORT
      LAYER M4 ;
        RECT  0 25.2 0.084 25.224 ;
    END
  END cut_8480
  PIN cut_8481
    DIRECTION INPUT ;
    USE SIGNAL ;
    PORT
      LAYER M4 ;
        RECT  0 25.296 0.084 25.32 ;
    END
  END cut_8481
  PIN cut_8482
    DIRECTION INPUT ;
    USE SIGNAL ;
    PORT
      LAYER M4 ;
        RECT  0 25.392 0.084 25.416 ;
    END
  END cut_8482
  PIN cut_8483
    DIRECTION INPUT ;
    USE SIGNAL ;
    PORT
      LAYER M4 ;
        RECT  0 25.488 0.084 25.512 ;
    END
  END cut_8483
  PIN cut_8484
    DIRECTION INPUT ;
    USE SIGNAL ;
    PORT
      LAYER M4 ;
        RECT  0 25.584 0.084 25.608 ;
    END
  END cut_8484
  PIN cut_8485
    DIRECTION INPUT ;
    USE SIGNAL ;
    PORT
      LAYER M4 ;
        RECT  0 25.68 0.084 25.704 ;
    END
  END cut_8485
  PIN cut_8486
    DIRECTION INPUT ;
    USE SIGNAL ;
    PORT
      LAYER M4 ;
        RECT  0 25.776 0.084 25.8 ;
    END
  END cut_8486
  PIN cut_8487
    DIRECTION INPUT ;
    USE SIGNAL ;
    PORT
      LAYER M4 ;
        RECT  0 25.872 0.084 25.896 ;
    END
  END cut_8487
  PIN cut_8488
    DIRECTION INPUT ;
    USE SIGNAL ;
    PORT
      LAYER M4 ;
        RECT  0 25.968 0.084 25.992 ;
    END
  END cut_8488
  PIN cut_8489
    DIRECTION INPUT ;
    USE SIGNAL ;
    PORT
      LAYER M4 ;
        RECT  0 26.064 0.084 26.088 ;
    END
  END cut_8489
  PIN cut_8490
    DIRECTION INPUT ;
    USE SIGNAL ;
    PORT
      LAYER M4 ;
        RECT  0 26.16 0.084 26.184 ;
    END
  END cut_8490
  PIN cut_8491
    DIRECTION INPUT ;
    USE SIGNAL ;
    PORT
      LAYER M4 ;
        RECT  0 26.256 0.084 26.28 ;
    END
  END cut_8491
  PIN cut_8492
    DIRECTION INPUT ;
    USE SIGNAL ;
    PORT
      LAYER M4 ;
        RECT  0 26.352 0.084 26.376 ;
    END
  END cut_8492
  PIN cut_8493
    DIRECTION INPUT ;
    USE SIGNAL ;
    PORT
      LAYER M4 ;
        RECT  0 26.448 0.084 26.472 ;
    END
  END cut_8493
  PIN cut_8494
    DIRECTION INPUT ;
    USE SIGNAL ;
    PORT
      LAYER M4 ;
        RECT  0 26.544 0.084 26.568 ;
    END
  END cut_8494
  PIN cut_8495
    DIRECTION INPUT ;
    USE SIGNAL ;
    PORT
      LAYER M4 ;
        RECT  0 26.64 0.084 26.664 ;
    END
  END cut_8495
  PIN cut_8496
    DIRECTION INPUT ;
    USE SIGNAL ;
    PORT
      LAYER M4 ;
        RECT  0 26.736 0.084 26.76 ;
    END
  END cut_8496
  PIN cut_8497
    DIRECTION INPUT ;
    USE SIGNAL ;
    PORT
      LAYER M4 ;
        RECT  0 26.832 0.084 26.856 ;
    END
  END cut_8497
  PIN cut_8498
    DIRECTION INPUT ;
    USE SIGNAL ;
    PORT
      LAYER M4 ;
        RECT  0 26.928 0.084 26.952 ;
    END
  END cut_8498
  PIN cut_8499
    DIRECTION INPUT ;
    USE SIGNAL ;
    PORT
      LAYER M4 ;
        RECT  0 27.024 0.084 27.048 ;
    END
  END cut_8499
  PIN cut_8500
    DIRECTION INPUT ;
    USE SIGNAL ;
    PORT
      LAYER M4 ;
        RECT  0 27.12 0.084 27.144 ;
    END
  END cut_8500
  PIN cut_8501
    DIRECTION INPUT ;
    USE SIGNAL ;
    PORT
      LAYER M4 ;
        RECT  0 27.216 0.084 27.24 ;
    END
  END cut_8501
  PIN cut_8502
    DIRECTION INPUT ;
    USE SIGNAL ;
    PORT
      LAYER M4 ;
        RECT  0 27.312 0.084 27.336 ;
    END
  END cut_8502
  PIN cut_8503
    DIRECTION INPUT ;
    USE SIGNAL ;
    PORT
      LAYER M4 ;
        RECT  0 27.408 0.084 27.432 ;
    END
  END cut_8503
  PIN cut_8504
    DIRECTION INPUT ;
    USE SIGNAL ;
    PORT
      LAYER M4 ;
        RECT  0 27.504 0.084 27.528 ;
    END
  END cut_8504
  PIN cut_8505
    DIRECTION INPUT ;
    USE SIGNAL ;
    PORT
      LAYER M4 ;
        RECT  0 27.6 0.084 27.624 ;
    END
  END cut_8505
  PIN cut_8506
    DIRECTION INPUT ;
    USE SIGNAL ;
    PORT
      LAYER M4 ;
        RECT  0 27.696 0.084 27.72 ;
    END
  END cut_8506
  PIN cut_8507
    DIRECTION INPUT ;
    USE SIGNAL ;
    PORT
      LAYER M4 ;
        RECT  0 27.792 0.084 27.816 ;
    END
  END cut_8507
  PIN cut_8508
    DIRECTION INPUT ;
    USE SIGNAL ;
    PORT
      LAYER M4 ;
        RECT  0 27.888 0.084 27.912 ;
    END
  END cut_8508
  PIN cut_8509
    DIRECTION INPUT ;
    USE SIGNAL ;
    PORT
      LAYER M4 ;
        RECT  0 27.984 0.084 28.008 ;
    END
  END cut_8509
  PIN cut_8510
    DIRECTION INPUT ;
    USE SIGNAL ;
    PORT
      LAYER M4 ;
        RECT  0 28.08 0.084 28.104 ;
    END
  END cut_8510
  PIN cut_8511
    DIRECTION INPUT ;
    USE SIGNAL ;
    PORT
      LAYER M4 ;
        RECT  0 31.248 0.084 31.272 ;
    END
  END cut_8511
  PIN cut_8512
    DIRECTION INPUT ;
    USE SIGNAL ;
    PORT
      LAYER M4 ;
        RECT  0 31.344 0.084 31.368 ;
    END
  END cut_8512
  PIN cut_8513
    DIRECTION INPUT ;
    USE SIGNAL ;
    PORT
      LAYER M4 ;
        RECT  0 31.44 0.084 31.464 ;
    END
  END cut_8513
  PIN cut_8514
    DIRECTION INPUT ;
    USE SIGNAL ;
    PORT
      LAYER M4 ;
        RECT  0 31.536 0.084 31.56 ;
    END
  END cut_8514
  PIN cut_8515
    DIRECTION INPUT ;
    USE SIGNAL ;
    PORT
      LAYER M4 ;
        RECT  0 31.632 0.084 31.656 ;
    END
  END cut_8515
  PIN cut_8516
    DIRECTION INPUT ;
    USE SIGNAL ;
    PORT
      LAYER M4 ;
        RECT  0 31.728 0.084 31.752 ;
    END
  END cut_8516
  PIN cut_8517
    DIRECTION INPUT ;
    USE SIGNAL ;
    PORT
      LAYER M4 ;
        RECT  0 31.824 0.084 31.848 ;
    END
  END cut_8517
  PIN cut_8518
    DIRECTION INPUT ;
    USE SIGNAL ;
    PORT
      LAYER M4 ;
        RECT  0 31.92 0.084 31.944 ;
    END
  END cut_8518
  PIN cut_8519
    DIRECTION INPUT ;
    USE SIGNAL ;
    PORT
      LAYER M4 ;
        RECT  0 32.016 0.084 32.04 ;
    END
  END cut_8519
  PIN cut_8520
    DIRECTION INPUT ;
    USE SIGNAL ;
    PORT
      LAYER M4 ;
        RECT  0 32.112 0.084 32.136 ;
    END
  END cut_8520
  PIN cut_8521
    DIRECTION INPUT ;
    USE SIGNAL ;
    PORT
      LAYER M4 ;
        RECT  0 32.208 0.084 32.232 ;
    END
  END cut_8521
  PIN cut_8522
    DIRECTION INPUT ;
    USE SIGNAL ;
    PORT
      LAYER M4 ;
        RECT  0 32.304 0.084 32.328 ;
    END
  END cut_8522
  PIN cut_8523
    DIRECTION INPUT ;
    USE SIGNAL ;
    PORT
      LAYER M4 ;
        RECT  0 32.4 0.084 32.424 ;
    END
  END cut_8523
  PIN cut_8524
    DIRECTION INPUT ;
    USE SIGNAL ;
    PORT
      LAYER M4 ;
        RECT  0 32.496 0.084 32.52 ;
    END
  END cut_8524
  PIN cut_8525
    DIRECTION INPUT ;
    USE SIGNAL ;
    PORT
      LAYER M4 ;
        RECT  0 32.592 0.084 32.616 ;
    END
  END cut_8525
  PIN cut_8526
    DIRECTION INPUT ;
    USE SIGNAL ;
    PORT
      LAYER M4 ;
        RECT  0 32.688 0.084 32.712 ;
    END
  END cut_8526
  PIN cut_8527
    DIRECTION INPUT ;
    USE SIGNAL ;
    PORT
      LAYER M4 ;
        RECT  0 32.784 0.084 32.808 ;
    END
  END cut_8527
  PIN cut_8528
    DIRECTION INPUT ;
    USE SIGNAL ;
    PORT
      LAYER M4 ;
        RECT  0 32.88 0.084 32.904 ;
    END
  END cut_8528
  PIN cut_8529
    DIRECTION INPUT ;
    USE SIGNAL ;
    PORT
      LAYER M4 ;
        RECT  0 32.976 0.084 33 ;
    END
  END cut_8529
  PIN cut_8530
    DIRECTION INPUT ;
    USE SIGNAL ;
    PORT
      LAYER M4 ;
        RECT  0 33.072 0.084 33.096 ;
    END
  END cut_8530
  PIN cut_8531
    DIRECTION INPUT ;
    USE SIGNAL ;
    PORT
      LAYER M4 ;
        RECT  0 33.168 0.084 33.192 ;
    END
  END cut_8531
  PIN cut_8532
    DIRECTION INPUT ;
    USE SIGNAL ;
    PORT
      LAYER M4 ;
        RECT  0 33.264 0.084 33.288 ;
    END
  END cut_8532
  PIN cut_8533
    DIRECTION INPUT ;
    USE SIGNAL ;
    PORT
      LAYER M4 ;
        RECT  0 33.36 0.084 33.384 ;
    END
  END cut_8533
  PIN cut_8534
    DIRECTION INPUT ;
    USE SIGNAL ;
    PORT
      LAYER M4 ;
        RECT  0 33.456 0.084 33.48 ;
    END
  END cut_8534
  PIN cut_8535
    DIRECTION INPUT ;
    USE SIGNAL ;
    PORT
      LAYER M4 ;
        RECT  0 33.552 0.084 33.576 ;
    END
  END cut_8535
  PIN cut_8536
    DIRECTION INPUT ;
    USE SIGNAL ;
    PORT
      LAYER M4 ;
        RECT  0 33.648 0.084 33.672 ;
    END
  END cut_8536
  PIN cut_8537
    DIRECTION INPUT ;
    USE SIGNAL ;
    PORT
      LAYER M4 ;
        RECT  0 33.744 0.084 33.768 ;
    END
  END cut_8537
  PIN cut_8538
    DIRECTION INPUT ;
    USE SIGNAL ;
    PORT
      LAYER M4 ;
        RECT  0 33.84 0.084 33.864 ;
    END
  END cut_8538
  PIN cut_8539
    DIRECTION INPUT ;
    USE SIGNAL ;
    PORT
      LAYER M4 ;
        RECT  0 33.936 0.084 33.96 ;
    END
  END cut_8539
  PIN cut_8690
    DIRECTION INPUT ;
    USE SIGNAL ;
    PORT
      LAYER M4 ;
        RECT  0 34.032 0.084 34.056 ;
    END
  END cut_8690
  PIN cut_8691
    DIRECTION INPUT ;
    USE SIGNAL ;
    PORT
      LAYER M4 ;
        RECT  0 34.128 0.084 34.152 ;
    END
  END cut_8691
  PIN cut_8694
    DIRECTION INPUT ;
    USE SIGNAL ;
    PORT
      LAYER M4 ;
        RECT  0 34.224 0.084 34.248 ;
    END
  END cut_8694
  PIN cut_8695
    DIRECTION INPUT ;
    USE SIGNAL ;
    PORT
      LAYER M4 ;
        RECT  0 38.16 0.084 38.184 ;
    END
  END cut_8695
  PIN cut_8748
    DIRECTION OUTPUT ;
    USE SIGNAL ;
    PORT
      LAYER M4 ;
        RECT  84.156 38.352 84.24 38.376 ;
    END
  END cut_8748
  PIN cut_8749
    DIRECTION OUTPUT ;
    USE SIGNAL ;
    PORT
      LAYER M4 ;
        RECT  84.156 38.448 84.24 38.472 ;
    END
  END cut_8749
  PIN cut_8750
    DIRECTION OUTPUT ;
    USE SIGNAL ;
    PORT
      LAYER M4 ;
        RECT  84.156 38.544 84.24 38.568 ;
    END
  END cut_8750
  PIN cut_8752
    DIRECTION INPUT ;
    USE SIGNAL ;
    PORT
      LAYER M4 ;
        RECT  0 38.256 0.084 38.28 ;
    END
  END cut_8752
  PIN cut_8753
    DIRECTION INPUT ;
    USE SIGNAL ;
    PORT
      LAYER M4 ;
        RECT  0 38.352 0.084 38.376 ;
    END
  END cut_8753
  PIN cut_8754
    DIRECTION INPUT ;
    USE SIGNAL ;
    PORT
      LAYER M4 ;
        RECT  0 38.448 0.084 38.472 ;
    END
  END cut_8754
  PIN cut_8755
    DIRECTION INPUT ;
    USE SIGNAL ;
    PORT
      LAYER M4 ;
        RECT  0 38.544 0.084 38.568 ;
    END
  END cut_8755
  PIN cut_8756
    DIRECTION INPUT ;
    USE SIGNAL ;
    PORT
      LAYER M4 ;
        RECT  0 38.64 0.084 38.664 ;
    END
  END cut_8756
  PIN cut_8757
    DIRECTION INPUT ;
    USE SIGNAL ;
    PORT
      LAYER M4 ;
        RECT  0 38.736 0.084 38.76 ;
    END
  END cut_8757
  PIN cut_8758
    DIRECTION INPUT ;
    USE SIGNAL ;
    PORT
      LAYER M4 ;
        RECT  0 38.832 0.084 38.856 ;
    END
  END cut_8758
  PIN cut_8759
    DIRECTION INPUT ;
    USE SIGNAL ;
    PORT
      LAYER M4 ;
        RECT  0 38.928 0.084 38.952 ;
    END
  END cut_8759
  PIN cut_8760
    DIRECTION INPUT ;
    USE SIGNAL ;
    PORT
      LAYER M4 ;
        RECT  0 39.024 0.084 39.048 ;
    END
  END cut_8760
  PIN cut_8761
    DIRECTION INPUT ;
    USE SIGNAL ;
    PORT
      LAYER M4 ;
        RECT  0 39.12 0.084 39.144 ;
    END
  END cut_8761
  PIN cut_8762
    DIRECTION INPUT ;
    USE SIGNAL ;
    PORT
      LAYER M4 ;
        RECT  0 39.216 0.084 39.24 ;
    END
  END cut_8762
  PIN cut_8763
    DIRECTION INPUT ;
    USE SIGNAL ;
    PORT
      LAYER M4 ;
        RECT  0 39.312 0.084 39.336 ;
    END
  END cut_8763
  PIN cut_8764
    DIRECTION INPUT ;
    USE SIGNAL ;
    PORT
      LAYER M4 ;
        RECT  0 39.408 0.084 39.432 ;
    END
  END cut_8764
  PIN cut_8765
    DIRECTION INPUT ;
    USE SIGNAL ;
    PORT
      LAYER M4 ;
        RECT  0 39.504 0.084 39.528 ;
    END
  END cut_8765
  PIN cut_8766
    DIRECTION INPUT ;
    USE SIGNAL ;
    PORT
      LAYER M4 ;
        RECT  0 39.6 0.084 39.624 ;
    END
  END cut_8766
  PIN cut_8767
    DIRECTION INPUT ;
    USE SIGNAL ;
    PORT
      LAYER M4 ;
        RECT  0 39.696 0.084 39.72 ;
    END
  END cut_8767
  PIN cut_8768
    DIRECTION INPUT ;
    USE SIGNAL ;
    PORT
      LAYER M4 ;
        RECT  0 39.792 0.084 39.816 ;
    END
  END cut_8768
  PIN cut_8769
    DIRECTION INPUT ;
    USE SIGNAL ;
    PORT
      LAYER M4 ;
        RECT  0 39.888 0.084 39.912 ;
    END
  END cut_8769
  PIN cut_8770
    DIRECTION INPUT ;
    USE SIGNAL ;
    PORT
      LAYER M4 ;
        RECT  0 39.984 0.084 40.008 ;
    END
  END cut_8770
  PIN cut_8771
    DIRECTION INPUT ;
    USE SIGNAL ;
    PORT
      LAYER M4 ;
        RECT  0 40.08 0.084 40.104 ;
    END
  END cut_8771
  PIN cut_8772
    DIRECTION INPUT ;
    USE SIGNAL ;
    PORT
      LAYER M4 ;
        RECT  0 40.176 0.084 40.2 ;
    END
  END cut_8772
  PIN cut_8773
    DIRECTION INPUT ;
    USE SIGNAL ;
    PORT
      LAYER M4 ;
        RECT  0 40.272 0.084 40.296 ;
    END
  END cut_8773
  PIN cut_8774
    DIRECTION INPUT ;
    USE SIGNAL ;
    PORT
      LAYER M4 ;
        RECT  0 40.368 0.084 40.392 ;
    END
  END cut_8774
  PIN cut_8775
    DIRECTION INPUT ;
    USE SIGNAL ;
    PORT
      LAYER M4 ;
        RECT  0 40.464 0.084 40.488 ;
    END
  END cut_8775
  PIN cut_8776
    DIRECTION INPUT ;
    USE SIGNAL ;
    PORT
      LAYER M4 ;
        RECT  0 40.56 0.084 40.584 ;
    END
  END cut_8776
  PIN cut_8777
    DIRECTION INPUT ;
    USE SIGNAL ;
    PORT
      LAYER M4 ;
        RECT  0 40.656 0.084 40.68 ;
    END
  END cut_8777
  PIN cut_8778
    DIRECTION INPUT ;
    USE SIGNAL ;
    PORT
      LAYER M4 ;
        RECT  0 40.752 0.084 40.776 ;
    END
  END cut_8778
  PIN cut_8779
    DIRECTION INPUT ;
    USE SIGNAL ;
    PORT
      LAYER M4 ;
        RECT  0 40.848 0.084 40.872 ;
    END
  END cut_8779
  PIN cut_8780
    DIRECTION INPUT ;
    USE SIGNAL ;
    PORT
      LAYER M4 ;
        RECT  0 40.944 0.084 40.968 ;
    END
  END cut_8780
  PIN cut_8781
    DIRECTION INPUT ;
    USE SIGNAL ;
    PORT
      LAYER M4 ;
        RECT  0 41.04 0.084 41.064 ;
    END
  END cut_8781
  PIN cut_8782
    DIRECTION INPUT ;
    USE SIGNAL ;
    PORT
      LAYER M4 ;
        RECT  0 41.136 0.084 41.16 ;
    END
  END cut_8782
  PIN cut_8783
    DIRECTION INPUT ;
    USE SIGNAL ;
    PORT
      LAYER M4 ;
        RECT  0 41.232 0.084 41.256 ;
    END
  END cut_8783
  PIN cut_8784
    DIRECTION INPUT ;
    USE SIGNAL ;
    PORT
      LAYER M4 ;
        RECT  0 41.328 0.084 41.352 ;
    END
  END cut_8784
  PIN cut_8785
    DIRECTION INPUT ;
    USE SIGNAL ;
    PORT
      LAYER M4 ;
        RECT  0 41.424 0.084 41.448 ;
    END
  END cut_8785
  PIN cut_8786
    DIRECTION INPUT ;
    USE SIGNAL ;
    PORT
      LAYER M4 ;
        RECT  0 41.52 0.084 41.544 ;
    END
  END cut_8786
  PIN cut_8787
    DIRECTION INPUT ;
    USE SIGNAL ;
    PORT
      LAYER M4 ;
        RECT  0 41.616 0.084 41.64 ;
    END
  END cut_8787
  PIN cut_8788
    DIRECTION INPUT ;
    USE SIGNAL ;
    PORT
      LAYER M4 ;
        RECT  0 41.712 0.084 41.736 ;
    END
  END cut_8788
  PIN cut_8789
    DIRECTION INPUT ;
    USE SIGNAL ;
    PORT
      LAYER M4 ;
        RECT  0 41.808 0.084 41.832 ;
    END
  END cut_8789
  PIN cut_8790
    DIRECTION INPUT ;
    USE SIGNAL ;
    PORT
      LAYER M4 ;
        RECT  0 41.904 0.084 41.928 ;
    END
  END cut_8790
  PIN cut_8791
    DIRECTION INPUT ;
    USE SIGNAL ;
    PORT
      LAYER M4 ;
        RECT  0 42 0.084 42.024 ;
    END
  END cut_8791
  PIN cut_8792
    DIRECTION INPUT ;
    USE SIGNAL ;
    PORT
      LAYER M4 ;
        RECT  0 42.096 0.084 42.12 ;
    END
  END cut_8792
  PIN cut_8793
    DIRECTION INPUT ;
    USE SIGNAL ;
    PORT
      LAYER M4 ;
        RECT  0 42.192 0.084 42.216 ;
    END
  END cut_8793
  PIN cut_8794
    DIRECTION INPUT ;
    USE SIGNAL ;
    PORT
      LAYER M4 ;
        RECT  0 42.288 0.084 42.312 ;
    END
  END cut_8794
  PIN cut_8795
    DIRECTION INPUT ;
    USE SIGNAL ;
    PORT
      LAYER M4 ;
        RECT  0 42.384 0.084 42.408 ;
    END
  END cut_8795
  PIN cut_8796
    DIRECTION INPUT ;
    USE SIGNAL ;
    PORT
      LAYER M4 ;
        RECT  0 42.48 0.084 42.504 ;
    END
  END cut_8796
  PIN cut_8797
    DIRECTION INPUT ;
    USE SIGNAL ;
    PORT
      LAYER M4 ;
        RECT  0 42.576 0.084 42.6 ;
    END
  END cut_8797
  PIN cut_8798
    DIRECTION INPUT ;
    USE SIGNAL ;
    PORT
      LAYER M4 ;
        RECT  0 42.672 0.084 42.696 ;
    END
  END cut_8798
  PIN cut_8799
    DIRECTION INPUT ;
    USE SIGNAL ;
    PORT
      LAYER M4 ;
        RECT  0 42.768 0.084 42.792 ;
    END
  END cut_8799
  PIN cut_8800
    DIRECTION INPUT ;
    USE SIGNAL ;
    PORT
      LAYER M4 ;
        RECT  0 42.864 0.084 42.888 ;
    END
  END cut_8800
  PIN cut_8801
    DIRECTION INPUT ;
    USE SIGNAL ;
    PORT
      LAYER M4 ;
        RECT  0 42.96 0.084 42.984 ;
    END
  END cut_8801
  PIN cut_8802
    DIRECTION INPUT ;
    USE SIGNAL ;
    PORT
      LAYER M4 ;
        RECT  0 43.056 0.084 43.08 ;
    END
  END cut_8802
  PIN cut_8803
    DIRECTION INPUT ;
    USE SIGNAL ;
    PORT
      LAYER M4 ;
        RECT  0 43.152 0.084 43.176 ;
    END
  END cut_8803
  PIN cut_8804
    DIRECTION INPUT ;
    USE SIGNAL ;
    PORT
      LAYER M4 ;
        RECT  0 43.248 0.084 43.272 ;
    END
  END cut_8804
  PIN cut_8805
    DIRECTION INPUT ;
    USE SIGNAL ;
    PORT
      LAYER M4 ;
        RECT  0 43.344 0.084 43.368 ;
    END
  END cut_8805
  PIN cut_8806
    DIRECTION INPUT ;
    USE SIGNAL ;
    PORT
      LAYER M4 ;
        RECT  0 43.44 0.084 43.464 ;
    END
  END cut_8806
  PIN cut_8807
    DIRECTION INPUT ;
    USE SIGNAL ;
    PORT
      LAYER M4 ;
        RECT  0 43.536 0.084 43.56 ;
    END
  END cut_8807
  PIN cut_8808
    DIRECTION INPUT ;
    USE SIGNAL ;
    PORT
      LAYER M4 ;
        RECT  0 43.632 0.084 43.656 ;
    END
  END cut_8808
  PIN cut_8809
    DIRECTION INPUT ;
    USE SIGNAL ;
    PORT
      LAYER M4 ;
        RECT  0 43.728 0.084 43.752 ;
    END
  END cut_8809
  PIN cut_8810
    DIRECTION INPUT ;
    USE SIGNAL ;
    PORT
      LAYER M4 ;
        RECT  0 43.824 0.084 43.848 ;
    END
  END cut_8810
  PIN cut_8811
    DIRECTION INPUT ;
    USE SIGNAL ;
    PORT
      LAYER M4 ;
        RECT  0 43.92 0.084 43.944 ;
    END
  END cut_8811
  PIN cut_8812
    DIRECTION INPUT ;
    USE SIGNAL ;
    PORT
      LAYER M4 ;
        RECT  0 44.016 0.084 44.04 ;
    END
  END cut_8812
  PIN cut_8813
    DIRECTION INPUT ;
    USE SIGNAL ;
    PORT
      LAYER M4 ;
        RECT  0 44.112 0.084 44.136 ;
    END
  END cut_8813
  PIN cut_8814
    DIRECTION INPUT ;
    USE SIGNAL ;
    PORT
      LAYER M4 ;
        RECT  0 44.208 0.084 44.232 ;
    END
  END cut_8814
  PIN cut_8815
    DIRECTION INPUT ;
    USE SIGNAL ;
    PORT
      LAYER M4 ;
        RECT  0 44.304 0.084 44.328 ;
    END
  END cut_8815
  PIN cut_8816
    DIRECTION INPUT ;
    USE SIGNAL ;
    PORT
      LAYER M4 ;
        RECT  0 44.4 0.084 44.424 ;
    END
  END cut_8816
  PIN cut_8817
    DIRECTION INPUT ;
    USE SIGNAL ;
    PORT
      LAYER M4 ;
        RECT  0 44.496 0.084 44.52 ;
    END
  END cut_8817
  PIN cut_8818
    DIRECTION INPUT ;
    USE SIGNAL ;
    PORT
      LAYER M4 ;
        RECT  0 44.592 0.084 44.616 ;
    END
  END cut_8818
  PIN cut_8819
    DIRECTION INPUT ;
    USE SIGNAL ;
    PORT
      LAYER M4 ;
        RECT  0 44.688 0.084 44.712 ;
    END
  END cut_8819
  PIN cut_8820
    DIRECTION INPUT ;
    USE SIGNAL ;
    PORT
      LAYER M4 ;
        RECT  0 44.784 0.084 44.808 ;
    END
  END cut_8820
  PIN cut_8821
    DIRECTION INPUT ;
    USE SIGNAL ;
    PORT
      LAYER M4 ;
        RECT  0 44.88 0.084 44.904 ;
    END
  END cut_8821
  PIN cut_8822
    DIRECTION INPUT ;
    USE SIGNAL ;
    PORT
      LAYER M4 ;
        RECT  0 44.976 0.084 45 ;
    END
  END cut_8822
  PIN cut_8823
    DIRECTION INPUT ;
    USE SIGNAL ;
    PORT
      LAYER M4 ;
        RECT  0 45.072 0.084 45.096 ;
    END
  END cut_8823
  PIN cut_8824
    DIRECTION INPUT ;
    USE SIGNAL ;
    PORT
      LAYER M4 ;
        RECT  0 45.168 0.084 45.192 ;
    END
  END cut_8824
  PIN cut_8825
    DIRECTION INPUT ;
    USE SIGNAL ;
    PORT
      LAYER M4 ;
        RECT  0 45.264 0.084 45.288 ;
    END
  END cut_8825
  PIN cut_8826
    DIRECTION INPUT ;
    USE SIGNAL ;
    PORT
      LAYER M4 ;
        RECT  0 45.36 0.084 45.384 ;
    END
  END cut_8826
  PIN cut_8827
    DIRECTION INPUT ;
    USE SIGNAL ;
    PORT
      LAYER M4 ;
        RECT  0 45.456 0.084 45.48 ;
    END
  END cut_8827
  PIN cut_8828
    DIRECTION INPUT ;
    USE SIGNAL ;
    PORT
      LAYER M4 ;
        RECT  0 45.552 0.084 45.576 ;
    END
  END cut_8828
  PIN cut_8829
    DIRECTION INPUT ;
    USE SIGNAL ;
    PORT
      LAYER M4 ;
        RECT  0 45.648 0.084 45.672 ;
    END
  END cut_8829
  PIN cut_8830
    DIRECTION INPUT ;
    USE SIGNAL ;
    PORT
      LAYER M4 ;
        RECT  0 45.744 0.084 45.768 ;
    END
  END cut_8830
  PIN cut_8831
    DIRECTION INPUT ;
    USE SIGNAL ;
    PORT
      LAYER M4 ;
        RECT  0 45.84 0.084 45.864 ;
    END
  END cut_8831
  PIN cut_8832
    DIRECTION INPUT ;
    USE SIGNAL ;
    PORT
      LAYER M4 ;
        RECT  0 45.936 0.084 45.96 ;
    END
  END cut_8832
  PIN cut_8833
    DIRECTION INPUT ;
    USE SIGNAL ;
    PORT
      LAYER M4 ;
        RECT  0 46.032 0.084 46.056 ;
    END
  END cut_8833
  PIN cut_8834
    DIRECTION INPUT ;
    USE SIGNAL ;
    PORT
      LAYER M4 ;
        RECT  0 46.128 0.084 46.152 ;
    END
  END cut_8834
  PIN cut_8835
    DIRECTION INPUT ;
    USE SIGNAL ;
    PORT
      LAYER M4 ;
        RECT  0 46.224 0.084 46.248 ;
    END
  END cut_8835
  PIN cut_8836
    DIRECTION INPUT ;
    USE SIGNAL ;
    PORT
      LAYER M4 ;
        RECT  0 46.32 0.084 46.344 ;
    END
  END cut_8836
  PIN cut_8837
    DIRECTION INPUT ;
    USE SIGNAL ;
    PORT
      LAYER M4 ;
        RECT  0 46.416 0.084 46.44 ;
    END
  END cut_8837
  PIN cut_8838
    DIRECTION INPUT ;
    USE SIGNAL ;
    PORT
      LAYER M4 ;
        RECT  0 46.512 0.084 46.536 ;
    END
  END cut_8838
  PIN cut_8839
    DIRECTION INPUT ;
    USE SIGNAL ;
    PORT
      LAYER M4 ;
        RECT  0 46.608 0.084 46.632 ;
    END
  END cut_8839
  PIN cut_8840
    DIRECTION INPUT ;
    USE SIGNAL ;
    PORT
      LAYER M4 ;
        RECT  0 46.704 0.084 46.728 ;
    END
  END cut_8840
  PIN cut_8841
    DIRECTION INPUT ;
    USE SIGNAL ;
    PORT
      LAYER M4 ;
        RECT  0 46.8 0.084 46.824 ;
    END
  END cut_8841
  PIN cut_8842
    DIRECTION INPUT ;
    USE SIGNAL ;
    PORT
      LAYER M4 ;
        RECT  0 46.896 0.084 46.92 ;
    END
  END cut_8842
  PIN cut_8843
    DIRECTION INPUT ;
    USE SIGNAL ;
    PORT
      LAYER M4 ;
        RECT  0 46.992 0.084 47.016 ;
    END
  END cut_8843
  PIN cut_8844
    DIRECTION INPUT ;
    USE SIGNAL ;
    PORT
      LAYER M4 ;
        RECT  0 47.088 0.084 47.112 ;
    END
  END cut_8844
  PIN cut_8845
    DIRECTION INPUT ;
    USE SIGNAL ;
    PORT
      LAYER M4 ;
        RECT  0 47.184 0.084 47.208 ;
    END
  END cut_8845
  PIN cut_8846
    DIRECTION INPUT ;
    USE SIGNAL ;
    PORT
      LAYER M4 ;
        RECT  0 47.28 0.084 47.304 ;
    END
  END cut_8846
  PIN cut_8847
    DIRECTION INPUT ;
    USE SIGNAL ;
    PORT
      LAYER M4 ;
        RECT  0 53.328 0.084 53.352 ;
    END
  END cut_8847
  PIN cut_8857
    DIRECTION OUTPUT ;
    USE SIGNAL ;
    PORT
      LAYER M4 ;
        RECT  84.156 38.64 84.24 38.664 ;
    END
  END cut_8857
  PIN cut_8858
    DIRECTION OUTPUT ;
    USE SIGNAL ;
    PORT
      LAYER M4 ;
        RECT  84.156 38.736 84.24 38.76 ;
    END
  END cut_8858
  PIN cut_8870
    DIRECTION OUTPUT ;
    USE SIGNAL ;
    PORT
      LAYER M4 ;
        RECT  84.156 38.832 84.24 38.856 ;
    END
  END cut_8870
  PIN cut_9
    DIRECTION INPUT ;
    USE SIGNAL ;
    PORT
      LAYER M4 ;
        RECT  0 19.344 0.084 19.368 ;
    END
  END cut_9
  PIN local_cgi
    DIRECTION INPUT ;
    USE SIGNAL ;
    PORT
      LAYER M4 ;
        RECT  0 53.424 0.084 53.448 ;
    END
  END local_cgi
  PIN local_enable_commit
    DIRECTION INPUT ;
    USE SIGNAL ;
    PORT
      LAYER M5 ;
        RECT  34.32 73.356 34.344 73.44 ;
    END
  END local_enable_commit
  PIN local_enable_commit_aux
    DIRECTION INPUT ;
    USE SIGNAL ;
    PORT
      LAYER M5 ;
        RECT  34.416 73.356 34.44 73.44 ;
    END
  END local_enable_commit_aux
  PIN local_gclk_0
    DIRECTION OUTPUT ;
    USE SIGNAL ;
    PORT
      LAYER M5 ;
        RECT  34.512 73.356 34.536 73.44 ;
    END
  END local_gclk_0
  PIN local_gclk_1
    DIRECTION OUTPUT ;
    USE SIGNAL ;
    PORT
      LAYER M5 ;
        RECT  34.608 73.356 34.632 73.44 ;
    END
  END local_gclk_1
  PIN local_gclk_10
    DIRECTION OUTPUT ;
    USE SIGNAL ;
    PORT
      LAYER M5 ;
        RECT  35.472 73.356 35.496 73.44 ;
    END
  END local_gclk_10
  PIN local_gclk_11
    DIRECTION OUTPUT ;
    USE SIGNAL ;
    PORT
      LAYER M5 ;
        RECT  35.568 73.356 35.592 73.44 ;
    END
  END local_gclk_11
  PIN local_gclk_2
    DIRECTION OUTPUT ;
    USE SIGNAL ;
    PORT
      LAYER M5 ;
        RECT  34.704 73.356 34.728 73.44 ;
    END
  END local_gclk_2
  PIN local_gclk_3
    DIRECTION OUTPUT ;
    USE SIGNAL ;
    PORT
      LAYER M5 ;
        RECT  34.8 73.356 34.824 73.44 ;
    END
  END local_gclk_3
  PIN local_gclk_4
    DIRECTION OUTPUT ;
    USE SIGNAL ;
    PORT
      LAYER M5 ;
        RECT  34.896 73.356 34.92 73.44 ;
    END
  END local_gclk_4
  PIN local_gclk_5
    DIRECTION OUTPUT ;
    USE SIGNAL ;
    PORT
      LAYER M5 ;
        RECT  34.992 73.356 35.016 73.44 ;
    END
  END local_gclk_5
  PIN local_gclk_6
    DIRECTION OUTPUT ;
    USE SIGNAL ;
    PORT
      LAYER M5 ;
        RECT  35.088 73.356 35.112 73.44 ;
    END
  END local_gclk_6
  PIN local_gclk_7
    DIRECTION OUTPUT ;
    USE SIGNAL ;
    PORT
      LAYER M5 ;
        RECT  35.184 73.356 35.208 73.44 ;
    END
  END local_gclk_7
  PIN local_gclk_8
    DIRECTION OUTPUT ;
    USE SIGNAL ;
    PORT
      LAYER M5 ;
        RECT  35.28 73.356 35.304 73.44 ;
    END
  END local_gclk_8
  PIN local_gclk_9
    DIRECTION OUTPUT ;
    USE SIGNAL ;
    PORT
      LAYER M5 ;
        RECT  35.376 73.356 35.4 73.44 ;
    END
  END local_gclk_9
  PIN local_raw_0
    DIRECTION INPUT ;
    USE SIGNAL ;
    PORT
      LAYER M5 ;
        RECT  35.664 73.356 35.688 73.44 ;
    END
  END local_raw_0
  PIN local_raw_1
    DIRECTION INPUT ;
    USE SIGNAL ;
    PORT
      LAYER M5 ;
        RECT  35.76 73.356 35.784 73.44 ;
    END
  END local_raw_1
  PIN local_raw_10
    DIRECTION INPUT ;
    USE SIGNAL ;
    PORT
      LAYER M5 ;
        RECT  36.624 73.356 36.648 73.44 ;
    END
  END local_raw_10
  PIN local_raw_11
    DIRECTION INPUT ;
    USE SIGNAL ;
    PORT
      LAYER M5 ;
        RECT  36.72 73.356 36.744 73.44 ;
    END
  END local_raw_11
  PIN local_raw_2
    DIRECTION INPUT ;
    USE SIGNAL ;
    PORT
      LAYER M5 ;
        RECT  35.856 73.356 35.88 73.44 ;
    END
  END local_raw_2
  PIN local_raw_3
    DIRECTION INPUT ;
    USE SIGNAL ;
    PORT
      LAYER M5 ;
        RECT  35.952 73.356 35.976 73.44 ;
    END
  END local_raw_3
  PIN local_raw_4
    DIRECTION INPUT ;
    USE SIGNAL ;
    PORT
      LAYER M5 ;
        RECT  36.048 73.356 36.072 73.44 ;
    END
  END local_raw_4
  PIN local_raw_5
    DIRECTION INPUT ;
    USE SIGNAL ;
    PORT
      LAYER M5 ;
        RECT  36.144 73.356 36.168 73.44 ;
    END
  END local_raw_5
  PIN local_raw_6
    DIRECTION INPUT ;
    USE SIGNAL ;
    PORT
      LAYER M5 ;
        RECT  36.24 73.356 36.264 73.44 ;
    END
  END local_raw_6
  PIN local_raw_7
    DIRECTION INPUT ;
    USE SIGNAL ;
    PORT
      LAYER M5 ;
        RECT  36.336 73.356 36.36 73.44 ;
    END
  END local_raw_7
  PIN local_raw_8
    DIRECTION INPUT ;
    USE SIGNAL ;
    PORT
      LAYER M5 ;
        RECT  36.432 73.356 36.456 73.44 ;
    END
  END local_raw_8
  PIN local_raw_9
    DIRECTION INPUT ;
    USE SIGNAL ;
    PORT
      LAYER M5 ;
        RECT  36.528 73.356 36.552 73.44 ;
    END
  END local_raw_9
  PIN VDD
    DIRECTION INOUT ;
    USE POWER ;
    PORT
      LAYER M5 ;
        RECT  78.192 2.151 78.312 71.289 ;
        RECT  72.792 2.151 72.912 71.289 ;
        RECT  67.392 2.151 67.512 71.289 ;
        RECT  61.992 2.151 62.112 71.289 ;
        RECT  56.592 2.151 56.712 71.289 ;
        RECT  51.192 2.151 51.312 71.289 ;
        RECT  45.792 2.151 45.912 71.289 ;
        RECT  40.392 2.151 40.512 71.289 ;
        RECT  34.992 2.151 35.112 71.289 ;
        RECT  29.592 2.151 29.712 71.289 ;
        RECT  24.192 2.151 24.312 71.289 ;
        RECT  18.792 2.151 18.912 71.289 ;
        RECT  13.392 2.151 13.512 71.289 ;
        RECT  7.992 2.151 8.112 71.289 ;
        RECT  2.592 2.151 2.712 71.289 ;
    END
  END VDD
  PIN VSS
    DIRECTION INOUT ;
    USE GROUND ;
    PORT
      LAYER M5 ;
        RECT  78 2.137 78.12 71.303 ;
        RECT  72.6 2.137 72.72 71.303 ;
        RECT  67.2 2.137 67.32 71.303 ;
        RECT  61.8 2.137 61.92 71.303 ;
        RECT  56.4 2.137 56.52 71.303 ;
        RECT  51 2.137 51.12 71.303 ;
        RECT  45.6 2.137 45.72 71.303 ;
        RECT  40.2 2.137 40.32 71.303 ;
        RECT  34.8 2.137 34.92 71.303 ;
        RECT  29.4 2.137 29.52 71.303 ;
        RECT  24 2.137 24.12 71.303 ;
        RECT  18.6 2.137 18.72 71.303 ;
        RECT  13.2 2.137 13.32 71.303 ;
        RECT  7.8 2.137 7.92 71.303 ;
        RECT  2.4 2.137 2.52 71.303 ;
    END
  END VSS
  # OT_OBS_CLOSED layer=M5 d_um=1.536 added=158
  OBS
    LAYER RVTN ;
     RECT  2.16 2.16 82.08 2.295 ;
     RECT  2.16 2.565 82.08 2.835 ;
     RECT  2.16 3.105 82.08 3.375 ;
     RECT  2.16 3.645 82.08 3.915 ;
     RECT  2.16 4.185 82.08 4.455 ;
     RECT  2.16 4.725 82.08 4.995 ;
     RECT  2.16 5.265 82.08 5.535 ;
     RECT  2.16 5.805 82.08 6.075 ;
     RECT  2.16 6.345 82.08 6.615 ;
     RECT  2.16 6.885 82.08 7.155 ;
     RECT  2.16 7.425 82.08 7.695 ;
     RECT  2.16 7.965 82.08 8.235 ;
     RECT  2.16 8.505 82.08 8.775 ;
     RECT  2.16 9.045 82.08 9.315 ;
     RECT  2.16 9.585 82.08 9.855 ;
     RECT  2.16 10.125 82.08 10.395 ;
     RECT  2.16 10.665 82.08 10.935 ;
     RECT  2.16 11.205 82.08 11.475 ;
     RECT  2.16 11.745 82.08 12.015 ;
     RECT  2.16 12.285 82.08 12.555 ;
     RECT  2.16 12.825 82.08 13.095 ;
     RECT  2.16 13.365 82.08 13.635 ;
     RECT  2.16 13.905 82.08 14.175 ;
     RECT  2.16 14.445 82.08 14.715 ;
     RECT  2.16 14.985 82.08 15.255 ;
     RECT  2.16 15.525 82.08 15.795 ;
     RECT  2.16 16.065 82.08 16.335 ;
     RECT  2.16 16.605 82.08 16.875 ;
     RECT  2.16 17.145 82.08 17.415 ;
     RECT  2.16 17.685 82.08 17.955 ;
     RECT  2.16 18.225 82.08 18.495 ;
     RECT  2.16 18.765 82.08 19.035 ;
     RECT  2.16 19.305 82.08 19.575 ;
     RECT  2.16 19.845 82.08 20.115 ;
     RECT  2.16 20.385 82.08 20.655 ;
     RECT  2.16 20.925 82.08 21.195 ;
     RECT  2.16 21.465 82.08 21.735 ;
     RECT  2.16 22.005 82.08 22.275 ;
     RECT  2.16 22.545 82.08 22.815 ;
     RECT  2.16 23.085 82.08 23.355 ;
     RECT  2.16 23.625 82.08 23.895 ;
     RECT  2.16 24.165 82.08 24.435 ;
     RECT  2.16 24.705 82.08 24.975 ;
     RECT  2.16 25.245 82.08 25.515 ;
     RECT  2.16 25.785 82.08 26.055 ;
     RECT  2.16 26.325 82.08 26.595 ;
     RECT  2.16 26.865 82.08 27.135 ;
     RECT  2.16 27.405 82.08 27.675 ;
     RECT  2.16 27.945 82.08 28.215 ;
     RECT  2.16 28.485 82.08 28.755 ;
     RECT  2.16 29.025 82.08 29.295 ;
     RECT  2.16 29.565 82.08 29.835 ;
     RECT  2.16 30.105 82.08 30.375 ;
     RECT  2.16 30.645 82.08 30.915 ;
     RECT  2.16 31.185 82.08 31.455 ;
     RECT  2.16 31.725 82.08 31.995 ;
     RECT  2.16 32.265 82.08 32.535 ;
     RECT  2.16 32.805 82.08 33.075 ;
     RECT  2.16 33.345 82.08 33.615 ;
     RECT  2.16 33.885 82.08 34.155 ;
     RECT  2.16 34.425 82.08 34.695 ;
     RECT  2.16 34.965 82.08 35.235 ;
     RECT  2.16 35.505 82.08 35.775 ;
     RECT  2.16 36.045 82.08 36.315 ;
     RECT  2.16 36.585 82.08 36.855 ;
     RECT  2.16 37.125 82.08 37.395 ;
     RECT  2.16 37.665 82.08 37.935 ;
     RECT  2.16 38.205 82.08 38.475 ;
     RECT  2.16 38.745 82.08 39.015 ;
     RECT  2.16 39.285 82.08 39.555 ;
     RECT  2.16 39.825 82.08 40.095 ;
     RECT  2.16 40.365 82.08 40.635 ;
     RECT  2.16 40.905 82.08 41.175 ;
     RECT  2.16 41.445 82.08 41.715 ;
     RECT  2.16 41.985 82.08 42.255 ;
     RECT  2.16 42.525 82.08 42.795 ;
     RECT  2.16 43.065 82.08 43.335 ;
     RECT  2.16 43.605 82.08 43.875 ;
     RECT  2.16 44.145 82.08 44.415 ;
     RECT  2.16 44.685 82.08 44.955 ;
     RECT  2.16 45.225 82.08 45.495 ;
     RECT  2.16 45.765 82.08 46.035 ;
     RECT  2.16 46.305 82.08 46.575 ;
     RECT  2.16 46.845 82.08 47.115 ;
     RECT  2.16 47.385 82.08 47.655 ;
     RECT  2.16 47.925 82.08 48.195 ;
     RECT  2.16 48.465 82.08 48.735 ;
     RECT  2.16 49.005 82.08 49.275 ;
     RECT  2.16 49.545 82.08 49.815 ;
     RECT  2.16 50.085 82.08 50.355 ;
     RECT  2.16 50.625 82.08 50.895 ;
     RECT  2.16 51.165 82.08 51.435 ;
     RECT  2.16 51.705 82.08 51.975 ;
     RECT  2.16 52.245 82.08 52.515 ;
     RECT  2.16 52.785 82.08 53.055 ;
     RECT  2.16 53.325 82.08 53.595 ;
     RECT  2.16 53.865 82.08 54.135 ;
     RECT  2.16 54.405 82.08 54.675 ;
     RECT  2.16 54.945 82.08 55.215 ;
     RECT  2.16 55.485 82.08 55.755 ;
     RECT  2.16 56.025 82.08 56.295 ;
     RECT  2.16 56.565 82.08 56.835 ;
     RECT  2.16 57.105 82.08 57.375 ;
     RECT  2.16 57.645 82.08 57.915 ;
     RECT  2.16 58.185 82.08 58.455 ;
     RECT  2.16 58.725 82.08 58.995 ;
     RECT  2.16 59.265 82.08 59.535 ;
     RECT  2.16 59.805 82.08 60.075 ;
     RECT  2.16 60.345 82.08 60.615 ;
     RECT  2.16 60.885 82.08 61.155 ;
     RECT  2.16 61.425 82.08 61.695 ;
     RECT  2.16 61.965 82.08 62.235 ;
     RECT  2.16 62.505 82.08 62.775 ;
     RECT  2.16 63.045 82.08 63.315 ;
     RECT  2.16 63.585 82.08 63.855 ;
     RECT  2.16 64.125 82.08 64.395 ;
     RECT  2.16 64.665 82.08 64.935 ;
     RECT  2.16 65.205 82.08 65.475 ;
     RECT  2.16 65.745 82.08 66.015 ;
     RECT  2.16 66.285 82.08 66.555 ;
     RECT  2.16 66.825 82.08 67.095 ;
     RECT  2.16 67.365 82.08 67.635 ;
     RECT  2.16 67.905 82.08 68.175 ;
     RECT  2.16 68.445 82.08 68.715 ;
     RECT  2.16 68.985 82.08 69.255 ;
     RECT  2.16 69.525 82.08 69.795 ;
     RECT  2.16 70.065 82.08 70.335 ;
     RECT  2.16 70.605 82.08 70.875 ;
     RECT  2.16 71.145 82.08 71.28 ;
    LAYER RVTP ;
     RECT  2.16 2.295 82.08 2.565 ;
     RECT  2.16 2.835 82.08 3.105 ;
     RECT  2.16 3.375 82.08 3.645 ;
     RECT  2.16 3.915 82.08 4.185 ;
     RECT  2.16 4.455 82.08 4.725 ;
     RECT  2.16 4.995 82.08 5.265 ;
     RECT  2.16 5.535 82.08 5.805 ;
     RECT  2.16 6.075 82.08 6.345 ;
     RECT  2.16 6.615 82.08 6.885 ;
     RECT  2.16 7.155 82.08 7.425 ;
     RECT  2.16 7.695 82.08 7.965 ;
     RECT  2.16 8.235 82.08 8.505 ;
     RECT  2.16 8.775 82.08 9.045 ;
     RECT  2.16 9.315 82.08 9.585 ;
     RECT  2.16 9.855 82.08 10.125 ;
     RECT  2.16 10.395 82.08 10.665 ;
     RECT  2.16 10.935 82.08 11.205 ;
     RECT  2.16 11.475 82.08 11.745 ;
     RECT  2.16 12.015 82.08 12.285 ;
     RECT  2.16 12.555 82.08 12.825 ;
     RECT  2.16 13.095 82.08 13.365 ;
     RECT  2.16 13.635 82.08 13.905 ;
     RECT  2.16 14.175 82.08 14.445 ;
     RECT  2.16 14.715 82.08 14.985 ;
     RECT  2.16 15.255 82.08 15.525 ;
     RECT  2.16 15.795 82.08 16.065 ;
     RECT  2.16 16.335 82.08 16.605 ;
     RECT  2.16 16.875 82.08 17.145 ;
     RECT  2.16 17.415 82.08 17.685 ;
     RECT  2.16 17.955 82.08 18.225 ;
     RECT  2.16 18.495 82.08 18.765 ;
     RECT  2.16 19.035 82.08 19.305 ;
     RECT  2.16 19.575 82.08 19.845 ;
     RECT  2.16 20.115 82.08 20.385 ;
     RECT  2.16 20.655 82.08 20.925 ;
     RECT  2.16 21.195 82.08 21.465 ;
     RECT  2.16 21.735 82.08 22.005 ;
     RECT  2.16 22.275 82.08 22.545 ;
     RECT  2.16 22.815 82.08 23.085 ;
     RECT  2.16 23.355 82.08 23.625 ;
     RECT  2.16 23.895 82.08 24.165 ;
     RECT  2.16 24.435 82.08 24.705 ;
     RECT  2.16 24.975 82.08 25.245 ;
     RECT  2.16 25.515 82.08 25.785 ;
     RECT  2.16 26.055 82.08 26.325 ;
     RECT  2.16 26.595 82.08 26.865 ;
     RECT  2.16 27.135 82.08 27.405 ;
     RECT  2.16 27.675 82.08 27.945 ;
     RECT  2.16 28.215 82.08 28.485 ;
     RECT  2.16 28.755 82.08 29.025 ;
     RECT  2.16 29.295 82.08 29.565 ;
     RECT  2.16 29.835 82.08 30.105 ;
     RECT  2.16 30.375 82.08 30.645 ;
     RECT  2.16 30.915 82.08 31.185 ;
     RECT  2.16 31.455 82.08 31.725 ;
     RECT  2.16 31.995 82.08 32.265 ;
     RECT  2.16 32.535 82.08 32.805 ;
     RECT  2.16 33.075 82.08 33.345 ;
     RECT  2.16 33.615 82.08 33.885 ;
     RECT  2.16 34.155 82.08 34.425 ;
     RECT  2.16 34.695 82.08 34.965 ;
     RECT  2.16 35.235 82.08 35.505 ;
     RECT  2.16 35.775 82.08 36.045 ;
     RECT  2.16 36.315 82.08 36.585 ;
     RECT  2.16 36.855 82.08 37.125 ;
     RECT  2.16 37.395 82.08 37.665 ;
     RECT  2.16 37.935 82.08 38.205 ;
     RECT  2.16 38.475 82.08 38.745 ;
     RECT  2.16 39.015 82.08 39.285 ;
     RECT  2.16 39.555 82.08 39.825 ;
     RECT  2.16 40.095 82.08 40.365 ;
     RECT  2.16 40.635 82.08 40.905 ;
     RECT  2.16 41.175 82.08 41.445 ;
     RECT  2.16 41.715 82.08 41.985 ;
     RECT  2.16 42.255 82.08 42.525 ;
     RECT  2.16 42.795 82.08 43.065 ;
     RECT  2.16 43.335 82.08 43.605 ;
     RECT  2.16 43.875 82.08 44.145 ;
     RECT  2.16 44.415 82.08 44.685 ;
     RECT  2.16 44.955 82.08 45.225 ;
     RECT  2.16 45.495 82.08 45.765 ;
     RECT  2.16 46.035 82.08 46.305 ;
     RECT  2.16 46.575 82.08 46.845 ;
     RECT  2.16 47.115 82.08 47.385 ;
     RECT  2.16 47.655 82.08 47.925 ;
     RECT  2.16 48.195 82.08 48.465 ;
     RECT  2.16 48.735 82.08 49.005 ;
     RECT  2.16 49.275 82.08 49.545 ;
     RECT  2.16 49.815 82.08 50.085 ;
     RECT  2.16 50.355 82.08 50.625 ;
     RECT  2.16 50.895 82.08 51.165 ;
     RECT  2.16 51.435 82.08 51.705 ;
     RECT  2.16 51.975 82.08 52.245 ;
     RECT  2.16 52.515 82.08 52.785 ;
     RECT  2.16 53.055 82.08 53.325 ;
     RECT  2.16 53.595 82.08 53.865 ;
     RECT  2.16 54.135 82.08 54.405 ;
     RECT  2.16 54.675 82.08 54.945 ;
     RECT  2.16 55.215 82.08 55.485 ;
     RECT  2.16 55.755 82.08 56.025 ;
     RECT  2.16 56.295 82.08 56.565 ;
     RECT  2.16 56.835 82.08 57.105 ;
     RECT  2.16 57.375 82.08 57.645 ;
     RECT  2.16 57.915 82.08 58.185 ;
     RECT  2.16 58.455 82.08 58.725 ;
     RECT  2.16 58.995 82.08 59.265 ;
     RECT  2.16 59.535 82.08 59.805 ;
     RECT  2.16 60.075 82.08 60.345 ;
     RECT  2.16 60.615 82.08 60.885 ;
     RECT  2.16 61.155 82.08 61.425 ;
     RECT  2.16 61.695 82.08 61.965 ;
     RECT  2.16 62.235 82.08 62.505 ;
     RECT  2.16 62.775 82.08 63.045 ;
     RECT  2.16 63.315 82.08 63.585 ;
     RECT  2.16 63.855 82.08 64.125 ;
     RECT  2.16 64.395 82.08 64.665 ;
     RECT  2.16 64.935 82.08 65.205 ;
     RECT  2.16 65.475 82.08 65.745 ;
     RECT  2.16 66.015 82.08 66.285 ;
     RECT  2.16 66.555 82.08 66.825 ;
     RECT  2.16 67.095 82.08 67.365 ;
     RECT  2.16 67.635 82.08 67.905 ;
     RECT  2.16 68.175 82.08 68.445 ;
     RECT  2.16 68.715 82.08 68.985 ;
     RECT  2.16 69.255 82.08 69.525 ;
     RECT  2.16 69.795 82.08 70.065 ;
     RECT  2.16 70.335 82.08 70.605 ;
     RECT  2.16 70.875 82.08 71.145 ;
    LAYER M1 ;
     RECT  2.16 2.151 82.08 71.289 ;
    LAYER M2 ;
     RECT  0.031 14.76 0.103 14.778 ;
     RECT  0.031 15.966 0.131 15.984 ;
     RECT  0.103 14.76 0.139 15.048 ;
     RECT  0.103 17.622 0.139 17.64 ;
     RECT  0.103 18.774 0.139 18.792 ;
     RECT  0.103 31.536 0.139 31.554 ;
     RECT  0.103 33.93 0.139 33.948 ;
     RECT  0.103 43.812 0.139 44.37 ;
     RECT  0.103 45.81 0.139 45.828 ;
     RECT  0.103 46.818 0.139 47.88 ;
     RECT  0.139 18.774 0.175 19.098 ;
     RECT  0.103 20.322 0.175 20.988 ;
     RECT  0.139 17.082 0.211 17.64 ;
     RECT  0.175 18.54 0.211 19.098 ;
     RECT  0.175 20.052 0.211 20.988 ;
     RECT  0.139 31.23 0.211 31.554 ;
     RECT  0.139 43.812 0.211 44.982 ;
     RECT  0.211 43.308 0.247 44.982 ;
     RECT  0.175 49.086 0.247 49.104 ;
     RECT  0.139 45.81 0.275 47.88 ;
     RECT  0.103 23.832 0.347 25.002 ;
     RECT  0.211 17.082 0.499 20.988 ;
     RECT  0.347 23.904 0.499 25.002 ;
     RECT  0.139 33.93 0.499 34.488 ;
     RECT  0.103 35.28 0.499 38.736 ;
     RECT  0.499 16.686 0.535 20.988 ;
     RECT  0.103 22.05 0.535 22.068 ;
     RECT  0.103 28.458 0.535 28.476 ;
     RECT  0.499 40.14 0.535 40.158 ;
     RECT  0.103 42.3 0.535 42.318 ;
     RECT  0.247 43.272 0.535 44.982 ;
     RECT  0.103 26.37 1.147 26.928 ;
     RECT  0.211 30.69 1.147 31.554 ;
     RECT  0.247 49.086 1.147 49.23 ;
     RECT  1.147 25.992 1.175 26.928 ;
     RECT  0.499 23.904 1.183 25.236 ;
     RECT  1.183 23.706 1.219 25.236 ;
     RECT  1.219 23.328 1.283 25.236 ;
     RECT  1.283 24.48 1.291 25.236 ;
     RECT  1.175 25.992 1.291 26.856 ;
     RECT  0.535 52.722 1.399 52.74 ;
     RECT  1.147 30.456 1.723 31.554 ;
     RECT  0.275 47.16 1.723 47.88 ;
     RECT  1.147 49.086 1.723 49.5 ;
     RECT  0.535 27.684 1.759 28.476 ;
     RECT  0.103 29.502 1.759 29.52 ;
     RECT  1.723 47.088 1.759 47.88 ;
     RECT  1.723 48.672 1.759 49.5 ;
     RECT  0.535 16.686 1.975 22.068 ;
     RECT  1.759 47.088 1.975 49.5 ;
     RECT  0.139 14.76 2.16 15.858 ;
     RECT  1.975 16.686 2.16 22.104 ;
     RECT  1.283 23.328 2.16 23.724 ;
     RECT  1.291 24.48 2.16 26.856 ;
     RECT  1.759 27.684 2.16 29.52 ;
     RECT  1.723 30.348 2.16 31.554 ;
     RECT  0.103 32.472 2.16 32.49 ;
     RECT  0.499 33.426 2.16 38.736 ;
     RECT  0.535 39.6 2.16 40.158 ;
     RECT  0.103 41.49 2.16 41.508 ;
     RECT  0.535 42.3 2.16 42.354 ;
     RECT  0.535 43.236 2.16 44.982 ;
     RECT  0.275 45.81 2.16 46.098 ;
     RECT  1.975 47.088 2.16 49.842 ;
     RECT  1.723 51.372 2.16 51.39 ;
     RECT  1.399 52.452 2.16 52.74 ;
     RECT  2.16 2.151 82.08 71.289 ;
     RECT  82.08 41.886 82.103 41.904 ;
     RECT  82.08 20.196 82.175 40.896 ;
     RECT  82.08 42.696 82.355 42.714 ;
     RECT  82.175 20.196 82.643 40.464 ;
     RECT  82.643 21.51 82.679 40.464 ;
     RECT  82.08 45.702 82.679 52.344 ;
     RECT  82.679 21.546 82.715 30.87 ;
     RECT  82.08 43.686 82.715 43.704 ;
     RECT  82.715 28.656 82.787 30.87 ;
     RECT  82.08 16.956 82.931 17.1 ;
     RECT  82.679 31.734 82.931 40.464 ;
     RECT  82.679 46.044 82.931 52.344 ;
     RECT  82.931 17.082 83.003 17.1 ;
     RECT  82.931 31.734 83.111 40.392 ;
     RECT  82.931 46.044 83.147 52.164 ;
     RECT  82.787 28.656 83.183 30.744 ;
     RECT  83.111 31.734 83.183 33.804 ;
     RECT  83.111 34.596 83.183 40.392 ;
     RECT  83.147 46.476 83.183 51.894 ;
     RECT  82.715 21.546 83.219 27.864 ;
     RECT  83.183 28.656 83.219 30.6 ;
     RECT  83.183 31.734 83.219 33.714 ;
     RECT  83.183 34.596 83.219 34.992 ;
     RECT  83.183 35.784 83.219 40.392 ;
     RECT  83.183 46.746 83.219 47.844 ;
     RECT  83.183 48.636 83.219 51.624 ;
     RECT  82.643 20.196 83.255 20.754 ;
     RECT  83.219 24.48 83.255 24.498 ;
     RECT  83.219 25.254 83.255 27.234 ;
     RECT  83.219 29.106 83.255 29.124 ;
     RECT  83.219 32.544 83.255 32.562 ;
     RECT  83.219 34.974 83.255 34.992 ;
     RECT  83.255 20.736 83.291 20.754 ;
     RECT  83.255 25.254 83.291 26.694 ;
     RECT  83.219 33.354 83.291 33.714 ;
     RECT  83.219 21.546 83.327 22.734 ;
     RECT  83.291 25.686 83.327 26.694 ;
     RECT  83.291 33.354 83.363 33.678 ;
     RECT  83.219 38.916 84.047 40.392 ;
     RECT  82.08 18.702 84.055 18.792 ;
     RECT  84.047 38.916 84.083 38.934 ;
     RECT  83.327 21.546 84.091 21.609 ;
     RECT  84.091 21.321 84.119 21.609 ;
     RECT  83.327 22.482 84.119 22.734 ;
     RECT  84.047 39.726 84.119 40.392 ;
     RECT  84.055 18.702 84.155 18.828 ;
     RECT  84.119 21.321 84.155 21.564 ;
     RECT  84.119 22.482 84.155 22.5 ;
     RECT  83.327 25.686 84.155 25.704 ;
     RECT  83.327 26.676 84.155 26.694 ;
     RECT  83.363 33.354 84.155 33.372 ;
     RECT  83.219 35.784 84.155 35.802 ;
     RECT  83.219 37.404 84.155 37.422 ;
     RECT  84.119 40.266 84.155 40.392 ;
     RECT  83.219 50.436 84.155 50.454 ;
     RECT  84.155 18.702 84.227 18.72 ;
     RECT  84.155 21.321 84.227 21.339 ;
     RECT  84.091 38.178 84.227 38.196 ;
     RECT  84.155 40.266 84.227 40.284 ;
    LAYER M3 ;
     RECT  2.415 2.143 2.505 2.413 ;
     RECT  7.815 2.143 7.905 2.413 ;
     RECT  13.215 2.143 13.305 2.413 ;
     RECT  18.615 2.143 18.705 2.413 ;
     RECT  24.015 2.143 24.105 2.413 ;
     RECT  29.415 2.143 29.505 2.413 ;
     RECT  34.815 2.143 34.905 2.413 ;
     RECT  40.215 2.143 40.305 2.413 ;
     RECT  45.615 2.143 45.705 2.413 ;
     RECT  51.015 2.143 51.105 2.413 ;
     RECT  56.415 2.143 56.505 2.413 ;
     RECT  61.815 2.143 61.905 2.413 ;
     RECT  67.215 2.143 67.305 2.413 ;
     RECT  72.615 2.143 72.705 2.413 ;
     RECT  78.015 2.143 78.105 2.413 ;
     RECT  2.415 2.413 2.697 14.251 ;
     RECT  2.415 14.251 2.754 14.341 ;
     RECT  6.516 14.521 6.534 14.647 ;
     RECT  7.815 2.413 8.097 14.647 ;
     RECT  2.415 14.341 2.862 14.683 ;
     RECT  3.6 14.521 3.618 14.683 ;
     RECT  2.415 14.683 3.618 14.791 ;
     RECT  4.644 14.215 4.662 14.791 ;
     RECT  5.724 14.485 5.742 14.791 ;
     RECT  2.415 14.791 3.726 14.881 ;
     RECT  4.644 14.791 5.742 14.881 ;
     RECT  0.036 14.755 0.054 15.025 ;
     RECT  0.036 15.025 0.126 15.187 ;
     RECT  0.036 15.187 0.234 15.295 ;
     RECT  2.415 14.881 5.742 15.331 ;
     RECT  42.624 15.151 42.642 15.691 ;
     RECT  45.615 2.413 45.897 15.961 ;
     RECT  0.036 15.295 0.558 15.989 ;
     RECT  0.108 15.989 0.558 16.013 ;
     RECT  2.376 15.331 5.742 16.105 ;
     RECT  6.516 14.647 8.097 16.105 ;
     RECT  2.376 16.105 8.097 16.141 ;
     RECT  81.216 16.141 81.882 16.231 ;
     RECT  45.615 15.961 46.422 16.259 ;
     RECT  34.815 2.413 35.097 16.339 ;
     RECT  38.772 16.231 38.79 16.375 ;
     RECT  45.615 16.259 45.897 16.411 ;
     RECT  80.604 16.231 81.882 16.411 ;
     RECT  45.108 16.411 45.897 16.501 ;
     RECT  46.656 16.303 46.89 16.501 ;
     RECT  79.092 16.411 79.11 16.501 ;
     RECT  80.424 16.411 81.882 16.501 ;
     RECT  9.288 16.411 9.306 16.529 ;
     RECT  40.215 2.413 40.497 16.609 ;
     RECT  2.376 16.141 8.514 16.651 ;
     RECT  42.624 15.691 42.75 16.681 ;
     RECT  79.092 16.501 81.882 16.681 ;
     RECT  0.108 16.013 0.522 16.843 ;
     RECT  2.304 16.651 8.514 16.843 ;
     RECT  34.815 16.339 35.478 16.843 ;
     RECT  38.196 16.375 38.79 16.843 ;
     RECT  39.924 16.609 40.497 16.843 ;
     RECT  39.924 16.843 40.698 16.915 ;
     RECT  42.624 16.681 43.146 16.915 ;
     RECT  42.624 16.915 43.326 16.951 ;
     RECT  41.616 16.915 41.634 17.041 ;
     RECT  39.6 16.915 40.698 17.069 ;
     RECT  2.304 16.843 8.982 17.077 ;
     RECT  37.08 15.997 37.098 17.077 ;
     RECT  38.196 16.843 38.826 17.077 ;
     RECT  42.624 16.951 43.794 17.077 ;
     RECT  44.604 16.501 45.897 17.077 ;
     RECT  82.908 16.951 82.926 17.077 ;
     RECT  36.9 17.077 37.098 17.083 ;
     RECT  51.015 2.413 51.297 17.113 ;
     RECT  38.088 17.077 39.474 17.117 ;
     RECT  41.616 17.041 41.778 17.149 ;
     RECT  42.624 17.077 45.897 17.149 ;
     RECT  46.656 16.501 47.25 17.149 ;
     RECT  2.232 17.077 8.982 17.177 ;
     RECT  34.815 16.843 35.73 17.221 ;
     RECT  41.508 17.149 41.778 17.221 ;
     RECT  42.624 17.149 47.25 17.221 ;
     RECT  50.328 17.113 51.297 17.221 ;
     RECT  72.615 2.413 72.897 17.221 ;
     RECT  34.776 17.221 35.73 17.347 ;
     RECT  10.8 16.609 10.818 17.383 ;
     RECT  10.8 17.383 10.89 17.419 ;
     RECT  40.215 17.069 40.698 17.419 ;
     RECT  41.508 17.221 47.25 17.419 ;
     RECT  36.9 17.083 37.206 17.455 ;
     RECT  40.215 17.419 47.25 17.491 ;
     RECT  48.42 16.951 48.438 17.491 ;
     RECT  10.728 17.419 10.89 17.519 ;
     RECT  10.836 17.519 10.89 17.609 ;
     RECT  34.776 17.347 35.838 17.609 ;
     RECT  36.756 17.455 37.206 17.609 ;
     RECT  61.815 2.413 62.097 17.617 ;
     RECT  37.044 17.609 37.206 17.645 ;
     RECT  34.776 17.609 35.73 17.651 ;
     RECT  2.304 17.177 8.982 17.689 ;
     RECT  2.304 17.689 9.054 17.761 ;
     RECT  50.256 17.221 51.297 17.761 ;
     RECT  56.415 2.413 56.697 17.761 ;
     RECT  78.015 2.413 78.297 17.761 ;
     RECT  79.092 16.681 81.954 17.761 ;
     RECT  49.572 17.761 51.297 17.879 ;
     RECT  38.088 17.117 38.862 17.887 ;
     RECT  40.215 17.491 48.438 17.887 ;
     RECT  72.54 17.221 72.897 17.887 ;
     RECT  73.692 17.077 73.71 17.887 ;
     RECT  37.044 17.645 37.062 17.915 ;
     RECT  38.088 17.887 48.438 17.915 ;
     RECT  2.304 17.761 9.126 17.951 ;
     RECT  34.776 17.651 35.097 17.987 ;
     RECT  70.344 17.923 70.362 17.995 ;
     RECT  78.015 17.761 81.954 18.031 ;
     RECT  39.528 17.915 48.438 18.121 ;
     RECT  39.528 18.121 48.474 18.149 ;
     RECT  42.156 18.149 42.642 18.185 ;
     RECT  0.108 16.843 0.558 18.221 ;
     RECT  10.836 17.609 10.854 18.221 ;
     RECT  39.6 18.149 41.31 18.221 ;
     RECT  43.38 18.149 48.474 18.221 ;
     RECT  2.304 17.951 9.054 18.283 ;
     RECT  1.98 18.283 9.054 18.419 ;
     RECT  38.196 17.915 38.79 18.419 ;
     RECT  39.708 18.221 41.238 18.419 ;
     RECT  43.38 18.221 46.854 18.419 ;
     RECT  72.54 17.887 73.71 18.463 ;
     RECT  43.884 18.419 46.854 18.491 ;
     RECT  50.364 17.879 51.297 18.563 ;
     RECT  59.112 18.535 59.13 18.571 ;
     RECT  38.52 18.419 38.79 18.661 ;
     RECT  43.884 18.491 46.818 18.689 ;
     RECT  65.52 18.301 65.538 18.689 ;
     RECT  66.384 18.265 66.402 18.689 ;
     RECT  67.215 2.413 67.497 18.769 ;
     RECT  84.204 18.697 84.222 18.769 ;
     RECT  70.344 17.995 70.398 18.805 ;
     RECT  84.132 18.769 84.222 18.805 ;
     RECT  47.628 18.221 48.474 18.841 ;
     RECT  9.036 18.419 9.054 18.967 ;
     RECT  61.272 17.617 62.097 19.003 ;
     RECT  60.3 17.185 60.318 19.039 ;
     RECT  9.036 18.967 9.126 19.103 ;
     RECT  42.156 18.185 42.39 19.111 ;
     RECT  43.884 18.689 44.694 19.139 ;
     RECT  42.156 19.111 42.786 19.201 ;
     RECT  47.628 18.841 48.546 19.201 ;
     RECT  9.036 19.103 9.09 19.337 ;
     RECT  1.98 18.419 8.226 19.381 ;
     RECT  9.036 19.337 9.054 19.381 ;
     RECT  38.52 18.661 38.826 19.387 ;
     RECT  0.108 18.221 0.234 19.469 ;
     RECT  77.796 18.031 81.99 19.471 ;
     RECT  42.048 19.201 42.786 19.499 ;
     RECT  47.628 19.201 48.618 19.535 ;
     RECT  42.768 19.499 42.786 19.543 ;
     RECT  0.144 19.469 0.234 19.565 ;
     RECT  45.504 18.689 46.818 19.579 ;
     RECT  48.6 19.535 48.618 19.579 ;
     RECT  49.572 17.879 49.59 19.579 ;
     RECT  38.52 19.387 39.474 19.651 ;
     RECT  40.215 18.419 41.13 19.651 ;
     RECT  42.768 19.543 42.858 19.651 ;
     RECT  55.296 19.111 55.314 19.651 ;
     RECT  48.6 19.579 49.59 19.679 ;
     RECT  76.212 19.651 76.23 19.769 ;
     RECT  23.256 19.507 23.274 19.777 ;
     RECT  54.936 19.651 55.314 19.805 ;
     RECT  27.288 19.471 27.306 19.813 ;
     RECT  27.288 19.813 27.522 19.913 ;
     RECT  23.076 19.777 23.274 19.921 ;
     RECT  24.015 2.413 24.297 19.921 ;
     RECT  0.18 19.565 0.234 20.011 ;
     RECT  38.52 19.651 41.13 20.011 ;
     RECT  41.94 19.921 41.958 20.011 ;
     RECT  59.112 18.571 59.454 20.011 ;
     RECT  70.344 18.805 70.47 20.011 ;
     RECT  56.304 17.761 56.697 20.075 ;
     RECT  61.272 19.003 62.406 20.075 ;
     RECT  1.98 19.381 9.054 20.083 ;
     RECT  23.076 19.921 24.297 20.083 ;
     RECT  44.352 19.139 44.694 20.083 ;
     RECT  61.452 20.075 62.406 20.083 ;
     RECT  58.788 20.011 59.454 20.119 ;
     RECT  61.452 20.083 62.73 20.119 ;
     RECT  72.468 18.463 73.71 20.119 ;
     RECT  10.8 20.047 10.854 20.147 ;
     RECT  61.452 20.119 62.766 20.147 ;
     RECT  77.544 19.471 81.99 20.155 ;
     RECT  10.8 20.147 10.818 20.183 ;
     RECT  26.244 20.083 26.262 20.191 ;
     RECT  60.3 19.039 60.462 20.191 ;
     RECT  82.908 17.077 82.998 20.191 ;
     RECT  58.716 20.119 59.454 20.219 ;
     RECT  32.976 19.309 32.994 20.309 ;
     RECT  60.3 20.191 60.57 20.309 ;
     RECT  61.815 20.147 62.766 20.309 ;
     RECT  0.18 20.011 0.342 20.317 ;
     RECT  1.98 20.083 9.414 20.317 ;
     RECT  45.504 19.579 47.466 20.317 ;
     RECT  48.6 19.679 48.798 20.317 ;
     RECT  72.468 20.119 74.286 20.344 ;
     RECT  26.064 20.191 26.262 20.353 ;
     RECT  25.992 20.353 26.262 20.389 ;
     RECT  27.036 20.353 27.054 20.389 ;
     RECT  44.136 20.083 44.694 20.389 ;
     RECT  45.504 20.317 48.798 20.389 ;
     RECT  1.98 20.317 9.486 20.417 ;
     RECT  0.108 20.317 0.342 20.425 ;
     RECT  42.768 19.651 42.93 20.425 ;
     RECT  72.468 20.344 74.43 20.425 ;
     RECT  42.768 20.425 43.038 20.443 ;
     RECT  60.3 20.309 60.498 20.453 ;
     RECT  42.732 20.443 43.038 20.461 ;
     RECT  72.468 20.425 74.754 20.461 ;
     RECT  75.816 19.921 76.05 20.461 ;
     RECT  77.508 20.155 81.99 20.461 ;
     RECT  82.908 20.191 83.25 20.461 ;
     RECT  37.512 20.281 37.53 20.551 ;
     RECT  66.996 18.769 67.497 20.551 ;
     RECT  7.056 20.417 9.486 20.579 ;
     RECT  33.084 20.461 33.102 20.579 ;
     RECT  76.932 20.461 83.25 20.579 ;
     RECT  69.84 20.011 70.722 20.581 ;
     RECT  71.46 20.551 71.478 20.581 ;
     RECT  42.696 20.461 43.182 20.587 ;
     RECT  44.136 20.389 48.798 20.587 ;
     RECT  69.84 20.581 71.478 20.587 ;
     RECT  72.468 20.461 76.05 20.587 ;
     RECT  22.86 20.083 24.297 20.615 ;
     RECT  61.815 20.309 62.406 20.615 ;
     RECT  0.108 20.425 0.558 20.621 ;
     RECT  1.98 20.417 6.318 20.651 ;
     RECT  34.815 17.987 35.097 20.659 ;
     RECT  37.44 20.551 37.566 20.659 ;
     RECT  55.296 19.805 55.314 20.659 ;
     RECT  59.112 20.219 59.454 20.659 ;
     RECT  60.3 20.453 60.462 20.659 ;
     RECT  38.52 20.011 41.958 20.683 ;
     RECT  42.696 20.587 48.798 20.683 ;
     RECT  68.76 19.777 68.778 20.695 ;
     RECT  69.84 20.587 76.05 20.695 ;
     RECT  18.615 2.413 18.897 20.731 ;
     RECT  21.744 20.587 21.762 20.731 ;
     RECT  25.992 20.389 27.054 20.731 ;
     RECT  34.776 20.659 35.097 20.731 ;
     RECT  77.004 20.579 83.25 20.731 ;
     RECT  33.48 20.725 33.498 20.765 ;
     RECT  34.416 20.731 35.097 20.821 ;
     RECT  25.992 20.731 27.198 20.849 ;
     RECT  36.576 20.623 36.594 20.857 ;
     RECT  37.368 20.659 37.566 20.857 ;
     RECT  68.76 20.695 76.05 20.857 ;
     RECT  25.992 20.849 26.982 20.885 ;
     RECT  21.744 20.731 21.942 20.893 ;
     RECT  21.744 20.893 22.842 20.929 ;
     RECT  59.112 20.659 60.462 21.005 ;
     RECT  9.108 20.579 9.486 21.029 ;
     RECT  38.52 20.683 48.798 21.029 ;
     RECT  59.112 21.005 59.562 21.029 ;
     RECT  40.068 21.029 48.798 21.091 ;
     RECT  49.572 19.679 49.59 21.091 ;
     RECT  68.76 20.857 76.23 21.101 ;
     RECT  77.004 20.731 83.286 21.101 ;
     RECT  21.564 20.929 22.842 21.119 ;
     RECT  25.992 20.885 26.802 21.119 ;
     RECT  18.615 20.731 18.954 21.127 ;
     RECT  25.992 21.119 26.01 21.155 ;
     RECT  34.416 20.821 35.73 21.155 ;
     RECT  6.228 20.651 6.318 21.163 ;
     RECT  7.056 20.579 8.262 21.163 ;
     RECT  9.216 21.029 9.486 21.191 ;
     RECT  52.524 21.091 52.542 21.199 ;
     RECT  34.452 21.155 35.73 21.227 ;
     RECT  54.72 20.659 55.314 21.227 ;
     RECT  10.908 21.091 10.926 21.235 ;
     RECT  21.564 21.119 21.726 21.235 ;
     RECT  10.728 21.235 10.926 21.271 ;
     RECT  36.576 20.857 37.566 21.271 ;
     RECT  38.52 21.029 39.258 21.271 ;
     RECT  52.488 21.199 52.542 21.271 ;
     RECT  56.415 20.075 56.697 21.271 ;
     RECT  59.112 21.029 59.31 21.271 ;
     RECT  84.06 18.805 84.222 21.293 ;
     RECT  9.216 21.191 9.414 21.299 ;
     RECT  52.452 21.271 52.542 21.299 ;
     RECT  84.096 21.293 84.222 21.344 ;
     RECT  0.108 20.621 0.198 21.355 ;
     RECT  34.488 21.227 35.73 21.361 ;
     RECT  69.552 21.101 76.23 21.361 ;
     RECT  77.004 21.101 83.25 21.361 ;
     RECT  34.488 21.361 35.802 21.389 ;
     RECT  30.78 20.731 30.798 21.397 ;
     RECT  27.828 21.199 27.846 21.425 ;
     RECT  54.72 21.227 54.738 21.425 ;
     RECT  60.444 21.005 60.462 21.425 ;
     RECT  6.228 21.163 8.262 21.437 ;
     RECT  1.98 20.651 5.49 21.469 ;
     RECT  6.228 21.437 8.097 21.469 ;
     RECT  23.652 20.615 24.297 21.469 ;
     RECT  29.415 2.413 29.697 21.469 ;
     RECT  61.815 20.615 62.097 21.469 ;
     RECT  26.784 21.119 26.802 21.497 ;
     RECT  30.744 21.397 30.798 21.497 ;
     RECT  0.108 21.355 0.342 21.505 ;
     RECT  21.312 21.235 21.726 21.505 ;
     RECT  34.56 21.389 35.802 21.505 ;
     RECT  9.216 21.299 9.234 21.533 ;
     RECT  10.728 21.271 11.07 21.533 ;
     RECT  50.436 18.563 51.297 21.541 ;
     RECT  52.452 21.299 52.506 21.541 ;
     RECT  61.56 21.469 62.097 21.541 ;
     RECT  84.096 21.344 84.15 21.569 ;
     RECT  22.824 21.119 22.842 21.631 ;
     RECT  23.652 21.469 24.714 21.631 ;
     RECT  40.068 21.091 49.59 21.631 ;
     RECT  50.4 21.541 51.297 21.631 ;
     RECT  10.764 21.533 11.07 21.659 ;
     RECT  30.78 21.497 30.798 21.659 ;
     RECT  52.38 21.541 52.506 21.659 ;
     RECT  68.76 21.101 68.778 21.659 ;
     RECT  69.552 21.361 83.25 21.659 ;
     RECT  34.56 21.505 35.838 21.695 ;
     RECT  61.56 21.541 62.19 21.703 ;
     RECT  20.268 21.163 20.286 21.739 ;
     RECT  21.096 21.505 21.726 21.739 ;
     RECT  36.576 21.271 39.258 21.811 ;
     RECT  40.068 21.631 51.297 21.811 ;
     RECT  58.824 21.271 59.31 21.811 ;
     RECT  0.108 21.505 0.558 21.869 ;
     RECT  20.268 21.739 21.726 21.901 ;
     RECT  20.268 21.901 21.942 21.929 ;
     RECT  69.696 21.659 83.25 21.929 ;
     RECT  71.244 21.929 83.25 21.937 ;
     RECT  22.824 21.631 24.714 21.965 ;
     RECT  29.124 21.469 29.697 21.965 ;
     RECT  58.644 21.811 59.31 21.965 ;
     RECT  18.615 21.127 19.026 22.013 ;
     RECT  23.832 21.965 24.714 22.045 ;
     RECT  34.815 21.695 35.838 22.081 ;
     RECT  36.576 21.811 51.297 22.081 ;
     RECT  1.98 21.469 8.097 22.109 ;
     RECT  10.764 21.659 10.818 22.109 ;
     RECT  71.244 21.937 83.286 22.109 ;
     RECT  52.38 21.659 52.398 22.171 ;
     RECT  68.616 21.775 68.634 22.205 ;
     RECT  71.244 22.109 72.897 22.205 ;
     RECT  73.692 22.109 83.286 22.207 ;
     RECT  70.02 21.929 70.47 22.208 ;
     RECT  2.268 22.109 8.097 22.235 ;
     RECT  21.096 21.929 21.942 22.235 ;
     RECT  73.692 22.207 83.322 22.235 ;
     RECT  23.832 22.045 24.93 22.243 ;
     RECT  27.468 22.243 27.486 22.279 ;
     RECT  21.312 22.235 21.942 22.351 ;
     RECT  34.815 22.081 51.297 22.351 ;
     RECT  61.56 21.703 62.226 22.351 ;
     RECT  23.832 22.243 25.074 22.379 ;
     RECT  27.396 22.279 27.486 22.441 ;
     RECT  74.772 22.235 83.322 22.445 ;
     RECT  23.832 22.379 25.002 22.469 ;
     RECT  71.244 22.205 71.586 22.469 ;
     RECT  27.396 22.441 27.954 22.477 ;
     RECT  84.096 21.569 84.114 22.477 ;
     RECT  23.832 22.469 24.534 22.505 ;
     RECT  54.648 22.351 54.666 22.513 ;
     RECT  20.268 21.929 20.286 22.549 ;
     RECT  58.644 21.965 58.806 22.549 ;
     RECT  54.648 22.513 54.738 22.577 ;
     RECT  9.18 22.279 9.198 22.585 ;
     RECT  61.56 22.351 62.514 22.585 ;
     RECT  0.108 21.869 0.126 22.603 ;
     RECT  34.815 22.351 51.462 22.621 ;
     RECT  58.428 22.549 58.806 22.621 ;
     RECT  63.576 22.477 63.594 22.621 ;
     RECT  66.708 20.551 67.497 22.621 ;
     RECT  58.356 22.621 58.806 22.649 ;
     RECT  27.396 22.477 28.17 22.739 ;
     RECT  54.72 22.577 54.738 22.739 ;
     RECT  58.356 22.649 58.734 22.739 ;
     RECT  61.56 22.585 62.73 22.739 ;
     RECT  66.672 22.621 67.497 22.739 ;
     RECT  61.56 22.739 62.514 22.775 ;
     RECT  63.576 22.621 63.882 22.775 ;
     RECT  21.312 22.351 22.05 22.781 ;
     RECT  19.908 22.549 20.286 22.783 ;
     RECT  52.308 22.171 52.398 22.783 ;
     RECT  0.108 22.603 0.162 22.792 ;
     RECT  52.308 22.783 52.47 22.795 ;
     RECT  9.18 22.585 9.234 22.811 ;
     RECT  74.772 22.445 83.25 22.829 ;
     RECT  27.396 22.739 27.954 22.847 ;
     RECT  58.428 22.739 58.734 22.847 ;
     RECT  58.716 22.847 58.734 22.877 ;
     RECT  2.304 22.235 8.097 22.891 ;
     RECT  22.824 21.965 22.878 22.891 ;
     RECT  70.056 22.208 70.47 22.891 ;
     RECT  71.244 22.469 71.55 22.891 ;
     RECT  10.8 22.109 10.818 23.009 ;
     RECT  23.832 22.505 24.498 23.009 ;
     RECT  55.728 21.271 56.697 23.009 ;
     RECT  72.432 22.205 72.897 23.017 ;
     RECT  73.692 22.235 73.962 23.017 ;
     RECT  0.108 22.792 0.126 23.021 ;
     RECT  19.8 22.783 20.286 23.045 ;
     RECT  27.396 22.847 27.702 23.045 ;
     RECT  31.32 22.981 31.338 23.053 ;
     RECT  33.48 22.795 33.498 23.053 ;
     RECT  22.428 22.891 22.878 23.089 ;
     RECT  84.096 22.477 84.15 23.117 ;
     RECT  18.615 22.013 18.954 23.125 ;
     RECT  34.38 22.621 51.462 23.153 ;
     RECT  66.708 22.739 67.497 23.153 ;
     RECT  21.204 23.089 21.222 23.161 ;
     RECT  30.852 23.053 31.338 23.161 ;
     RECT  33.48 23.053 33.57 23.161 ;
     RECT  44.388 23.153 51.462 23.161 ;
     RECT  52.308 22.795 52.686 23.161 ;
     RECT  72.432 23.017 73.962 23.213 ;
     RECT  84.096 23.117 84.114 23.213 ;
     RECT  33.192 23.161 33.57 23.251 ;
     RECT  66.816 23.153 67.497 23.251 ;
     RECT  73.62 23.213 73.962 23.251 ;
     RECT  74.772 22.829 83.214 23.251 ;
     RECT  22.428 23.089 22.95 23.279 ;
     RECT  27.684 23.045 27.702 23.279 ;
     RECT  64.548 23.161 64.566 23.279 ;
     RECT  65.628 18.769 65.646 23.279 ;
     RECT  73.62 23.251 83.214 23.279 ;
     RECT  22.5 23.279 22.95 23.315 ;
     RECT  73.62 23.279 75.15 23.315 ;
     RECT  20.232 23.045 20.286 23.323 ;
     RECT  21.06 23.161 21.222 23.323 ;
     RECT  70.056 22.891 71.55 23.359 ;
     RECT  72.432 23.213 72.897 23.359 ;
     RECT  2.304 22.891 8.154 23.395 ;
     RECT  32.724 23.251 33.57 23.395 ;
     RECT  34.38 23.153 43.614 23.395 ;
     RECT  44.388 23.161 52.686 23.431 ;
     RECT  30.78 23.161 31.338 23.467 ;
     RECT  30.78 23.467 31.77 23.521 ;
     RECT  32.724 23.395 43.614 23.521 ;
     RECT  9.072 23.431 9.162 23.549 ;
     RECT  30.78 23.521 43.614 23.549 ;
     RECT  1.224 23.323 1.242 23.563 ;
     RECT  44.388 23.431 52.866 23.585 ;
     RECT  70.056 23.359 72.897 23.629 ;
     RECT  1.152 23.563 1.242 23.659 ;
     RECT  23.832 23.009 24.297 23.665 ;
     RECT  25.956 23.629 25.974 23.665 ;
     RECT  56.196 23.009 56.697 23.665 ;
     RECT  69.624 23.629 72.897 23.665 ;
     RECT  32.22 23.549 43.614 23.693 ;
     RECT  44.388 23.585 51.354 23.693 ;
     RECT  25.956 23.665 26.046 23.701 ;
     RECT  52.128 23.585 52.866 23.701 ;
     RECT  53.604 23.089 53.622 23.701 ;
     RECT  66.816 23.251 68.202 23.701 ;
     RECT  30.78 23.549 31.338 23.729 ;
     RECT  52.128 23.701 53.622 23.729 ;
     RECT  2.268 23.395 8.154 23.755 ;
     RECT  75.96 23.279 83.214 23.789 ;
     RECT  66.816 23.701 68.31 23.803 ;
     RECT  69.3 23.665 72.897 23.803 ;
     RECT  73.62 23.315 74.898 23.819 ;
     RECT  0.18 23.755 0.342 23.827 ;
     RECT  20.232 23.323 21.222 23.855 ;
     RECT  52.128 23.729 53.55 23.855 ;
     RECT  56.196 23.665 57.222 23.855 ;
     RECT  66.816 23.803 72.897 23.855 ;
     RECT  18.615 23.125 19.206 23.863 ;
     RECT  20.268 23.855 21.222 23.863 ;
     RECT  9.072 23.549 9.126 23.891 ;
     RECT  0.108 23.827 0.342 23.899 ;
     RECT  1.152 23.659 1.314 23.899 ;
     RECT  32.652 23.693 43.614 23.899 ;
     RECT  44.388 23.693 51.297 23.899 ;
     RECT  63.252 23.431 63.27 23.899 ;
     RECT  52.128 23.855 52.29 23.927 ;
     RECT  68.652 23.855 72.897 23.933 ;
     RECT  2.232 23.755 8.154 23.971 ;
     RECT  25.956 23.701 26.55 23.971 ;
     RECT  61.56 22.775 62.097 23.999 ;
     RECT  17.676 23.935 17.694 24.089 ;
     RECT  52.128 23.927 52.146 24.089 ;
     RECT  70.092 23.933 72.897 24.089 ;
     RECT  25.956 23.971 26.658 24.097 ;
     RECT  20.268 23.863 21.654 24.125 ;
     RECT  68.652 23.933 69.246 24.125 ;
     RECT  61.815 23.999 62.097 24.133 ;
     RECT  62.82 23.899 63.27 24.133 ;
     RECT  59.436 23.971 59.454 24.169 ;
     RECT  66.816 23.855 67.806 24.169 ;
     RECT  74.088 23.819 74.898 24.169 ;
     RECT  75.96 23.789 82.35 24.169 ;
     RECT  56.196 23.855 56.697 24.205 ;
     RECT  59.436 24.169 59.814 24.205 ;
     RECT  0.108 23.899 1.314 24.235 ;
     RECT  2.232 23.971 8.874 24.235 ;
     RECT  58.932 24.205 59.814 24.241 ;
     RECT  69.012 24.125 69.246 24.269 ;
     RECT  58.716 24.241 59.814 24.283 ;
     RECT  61.815 24.133 63.27 24.325 ;
     RECT  58.716 24.283 60.354 24.331 ;
     RECT  17.532 24.205 17.55 24.359 ;
     RECT  61.815 24.325 63.846 24.365 ;
     RECT  18.615 23.863 19.386 24.395 ;
     RECT  20.34 24.125 21.654 24.395 ;
     RECT  25.956 24.097 26.766 24.395 ;
     RECT  32.652 23.899 51.297 24.395 ;
     RECT  53.532 23.855 53.55 24.395 ;
     RECT  58.716 24.331 60.498 24.395 ;
     RECT  20.34 24.395 20.358 24.431 ;
     RECT  26.028 24.395 26.766 24.431 ;
     RECT  74.088 24.169 82.35 24.431 ;
     RECT  23.292 23.665 24.297 24.439 ;
     RECT  14.868 24.367 14.886 24.467 ;
     RECT  32.652 24.395 33.354 24.469 ;
     RECT  83.196 23.789 83.214 24.475 ;
     RECT  59.796 24.395 60.498 24.503 ;
     RECT  74.088 24.431 76.266 24.503 ;
     RECT  32.22 24.469 33.354 24.509 ;
     RECT  22.824 24.439 24.297 24.511 ;
     RECT  57.528 24.511 57.546 24.629 ;
     RECT  61.815 24.365 63.63 24.629 ;
     RECT  69.012 24.269 69.174 24.629 ;
     RECT  74.088 24.503 75.114 24.637 ;
     RECT  55.872 24.205 56.697 24.665 ;
     RECT  59.796 24.503 60.39 24.665 ;
     RECT  61.815 24.629 63.45 24.665 ;
     RECT  60.372 24.665 60.39 24.701 ;
     RECT  77.004 24.431 82.35 24.709 ;
     RECT  83.196 24.475 83.25 24.709 ;
     RECT  61.815 24.665 62.874 24.737 ;
     RECT  0.108 24.235 8.874 24.745 ;
     RECT  30.78 23.729 31.086 24.745 ;
     RECT  32.22 24.509 33.21 24.745 ;
     RECT  18.615 24.395 18.954 24.773 ;
     RECT  26.064 24.431 26.766 24.773 ;
     RECT  54.792 24.133 54.81 24.781 ;
     RECT  16.524 24.205 16.542 24.809 ;
     RECT  26.748 24.773 26.766 24.809 ;
     RECT  69.012 24.629 69.102 24.809 ;
     RECT  30.78 24.745 33.21 24.899 ;
     RECT  73.8 24.637 75.114 24.899 ;
     RECT  52.02 24.781 52.038 24.935 ;
     RECT  74.7 24.899 75.114 24.935 ;
     RECT  74.772 24.935 75.114 24.941 ;
     RECT  58.716 24.395 58.842 24.943 ;
     RECT  77.004 24.709 83.25 25.007 ;
     RECT  30.78 24.899 31.734 25.043 ;
     RECT  52.704 24.943 52.722 25.043 ;
     RECT  61.815 24.737 62.802 25.043 ;
     RECT  54.792 24.781 54.846 25.051 ;
     RECT  77.472 25.007 83.25 25.079 ;
     RECT  34.632 24.395 51.297 25.141 ;
     RECT  58.248 24.943 58.842 25.141 ;
     RECT  61.815 25.043 62.73 25.141 ;
     RECT  70.272 24.089 72.897 25.147 ;
     RECT  21.96 24.511 24.297 25.205 ;
     RECT  58.248 25.141 58.878 25.205 ;
     RECT  0.108 24.745 9.126 25.213 ;
     RECT  54.792 25.051 54.954 25.213 ;
     RECT  0.108 25.213 9.27 25.229 ;
     RECT  78.015 25.079 83.25 25.249 ;
     RECT  10.728 25.213 10.746 25.285 ;
     RECT  21.204 24.395 21.222 25.285 ;
     RECT  21.96 25.205 22.806 25.285 ;
     RECT  32.472 24.899 33.21 25.285 ;
     RECT  34.128 25.141 51.297 25.285 ;
     RECT  61.128 25.141 62.73 25.285 ;
     RECT  32.472 25.285 33.282 25.321 ;
     RECT  34.128 25.285 51.966 25.321 ;
     RECT  65.7 25.249 65.718 25.321 ;
     RECT  74.808 24.941 75.114 25.321 ;
     RECT  75.96 24.503 76.266 25.321 ;
     RECT  65.7 25.321 65.826 25.349 ;
     RECT  0.144 25.229 9.27 25.411 ;
     RECT  10.728 25.285 10.818 25.411 ;
     RECT  32.472 25.321 51.966 25.439 ;
     RECT  53.64 24.511 53.982 25.439 ;
     RECT  60.732 25.285 62.73 25.439 ;
     RECT  65.808 25.349 65.826 25.439 ;
     RECT  19.8 25.213 19.818 25.475 ;
     RECT  21.204 25.285 22.806 25.475 ;
     RECT  32.472 25.439 33.57 25.475 ;
     RECT  53.64 25.439 53.802 25.475 ;
     RECT  60.732 25.439 62.097 25.475 ;
     RECT  31.5 25.043 31.734 25.511 ;
     RECT  34.308 25.439 51.966 25.517 ;
     RECT  78.015 25.249 83.286 25.547 ;
     RECT  73.8 24.899 73.926 25.555 ;
     RECT  54.792 25.213 55.242 25.579 ;
     RECT  53.712 25.475 53.802 25.583 ;
     RECT  50.724 25.517 51.966 25.619 ;
     RECT  58.608 25.205 58.878 25.619 ;
     RECT  60.84 25.475 62.097 25.619 ;
     RECT  70.092 25.147 72.897 25.619 ;
     RECT  0.144 25.411 9.594 25.627 ;
     RECT  0.144 25.627 9.702 25.681 ;
     RECT  10.62 25.411 10.818 25.681 ;
     RECT  70.74 25.619 72.897 25.681 ;
     RECT  73.764 25.555 73.926 25.681 ;
     RECT  50.724 25.619 51.894 25.709 ;
     RECT  54.72 25.579 55.278 25.717 ;
     RECT  64.26 25.483 64.278 25.745 ;
     RECT  50.724 25.709 51.297 25.781 ;
     RECT  0.144 25.681 10.818 25.825 ;
     RECT  69.012 24.809 69.03 25.825 ;
     RECT  34.308 25.517 49.842 25.853 ;
     RECT  54.72 25.717 55.458 25.861 ;
     RECT  70.74 25.681 73.926 25.861 ;
     RECT  74.808 25.321 76.41 25.861 ;
     RECT  54.72 25.861 55.638 25.889 ;
     RECT  64.368 25.789 64.386 25.889 ;
     RECT  78.015 25.547 82.098 25.951 ;
     RECT  55.62 25.889 55.638 25.979 ;
     RECT  69.84 25.681 69.858 25.979 ;
     RECT  70.74 25.861 76.41 25.979 ;
     RECT  23.616 25.205 24.297 25.987 ;
     RECT  31.5 25.511 31.518 25.987 ;
     RECT  69.012 25.825 69.102 25.987 ;
     RECT  34.308 25.853 47.286 26.015 ;
     RECT  48.06 25.853 49.842 26.087 ;
     RECT  48.06 26.087 49.806 26.093 ;
     RECT  12.168 25.861 12.186 26.095 ;
     RECT  13.215 2.413 13.497 26.095 ;
     RECT  58.428 25.987 58.446 26.095 ;
     RECT  83.232 25.547 83.286 26.095 ;
     RECT  69.012 25.987 69.786 26.107 ;
     RECT  0.144 25.825 10.926 26.131 ;
     RECT  11.844 26.095 13.497 26.131 ;
     RECT  20.016 26.095 20.034 26.131 ;
     RECT  21.204 25.475 21.222 26.131 ;
     RECT  21.96 25.475 22.806 26.131 ;
     RECT  23.616 25.987 24.534 26.131 ;
     RECT  70.776 25.979 73.782 26.141 ;
     RECT  48.06 26.093 49.77 26.159 ;
     RECT  68.976 26.107 69.786 26.203 ;
     RECT  0.144 26.131 13.986 26.221 ;
     RECT  14.832 25.861 14.85 26.221 ;
     RECT  18.615 24.773 18.897 26.221 ;
     RECT  20.016 26.131 20.178 26.221 ;
     RECT  20.952 26.131 21.222 26.221 ;
     RECT  20.016 26.221 21.222 26.248 ;
     RECT  21.96 26.131 24.534 26.248 ;
     RECT  48.06 26.159 49.662 26.249 ;
     RECT  0.144 26.221 14.958 26.257 ;
     RECT  18.615 26.221 18.954 26.257 ;
     RECT  32.652 25.475 33.57 26.257 ;
     RECT  34.308 26.015 43.614 26.257 ;
     RECT  0.144 26.257 15.678 26.285 ;
     RECT  58.248 26.095 58.446 26.285 ;
     RECT  60.84 25.619 60.966 26.285 ;
     RECT  68.94 26.203 69.786 26.285 ;
     RECT  20.016 26.248 24.534 26.293 ;
     RECT  61.815 25.619 62.097 26.299 ;
     RECT  14.22 26.285 15.678 26.321 ;
     RECT  17.676 25.717 17.694 26.329 ;
     RECT  18.576 26.257 18.954 26.329 ;
     RECT  19.692 26.293 24.534 26.329 ;
     RECT  26.424 26.221 26.442 26.329 ;
     RECT  74.664 25.979 76.41 26.329 ;
     RECT  0.144 26.285 13.497 26.365 ;
     RECT  18.576 26.329 24.534 26.365 ;
     RECT  26.352 26.329 26.442 26.401 ;
     RECT  77.76 25.951 82.098 26.401 ;
     RECT  83.232 26.095 83.322 26.401 ;
     RECT  54.72 25.889 54.738 26.429 ;
     RECT  61.815 26.299 62.73 26.429 ;
     RECT  14.724 26.321 15.678 26.491 ;
     RECT  16.524 26.293 16.542 26.491 ;
     RECT  48.06 26.249 48.69 26.519 ;
     RECT  17.604 26.329 17.694 26.527 ;
     RECT  18.504 26.365 24.534 26.527 ;
     RECT  17.604 26.527 24.534 26.539 ;
     RECT  25.38 25.987 25.398 26.539 ;
     RECT  32.652 26.257 43.614 26.573 ;
     RECT  60.948 26.285 60.966 26.591 ;
     RECT  32.652 26.573 43.542 26.627 ;
     RECT  74.664 26.329 76.806 26.629 ;
     RECT  74.664 26.629 76.842 26.635 ;
     RECT  77.76 26.401 83.322 26.635 ;
     RECT  74.664 26.635 83.322 26.669 ;
     RECT  17.604 26.539 25.398 26.671 ;
     RECT  14.724 26.491 16.542 26.699 ;
     RECT  84.132 25.672 84.15 26.699 ;
     RECT  14.796 26.699 15.498 26.717 ;
     RECT  71.172 26.141 73.782 26.731 ;
     RECT  74.664 26.669 83.25 26.731 ;
     RECT  44.748 26.015 47.214 26.761 ;
     RECT  48.06 26.519 48.51 26.761 ;
     RECT  0.108 26.365 13.497 26.789 ;
     RECT  0.108 26.789 12.006 26.825 ;
     RECT  17.532 26.671 25.398 26.833 ;
     RECT  68.976 26.285 69.786 26.875 ;
     RECT  16.272 26.699 16.542 26.905 ;
     RECT  17.28 26.833 25.398 26.905 ;
     RECT  26.352 26.401 26.802 26.905 ;
     RECT  30.78 25.987 31.518 26.923 ;
     RECT  49.5 26.249 49.662 26.941 ;
     RECT  68.976 26.875 70.146 26.941 ;
     RECT  71.172 26.731 83.25 26.969 ;
     RECT  30.78 26.923 31.77 27.059 ;
     RECT  32.652 26.627 43.506 27.059 ;
     RECT  49.5 26.941 49.878 27.059 ;
     RECT  32.652 27.059 43.362 27.103 ;
     RECT  74.7 26.969 83.25 27.131 ;
     RECT  12.96 26.789 13.497 27.139 ;
     RECT  26.352 26.905 27.126 27.139 ;
     RECT  44.748 26.761 48.51 27.175 ;
     RECT  68.976 26.941 70.218 27.175 ;
     RECT  16.272 26.905 25.398 27.203 ;
     RECT  26.352 27.139 27.198 27.211 ;
     RECT  76.572 27.131 83.25 27.239 ;
     RECT  30.78 27.059 31.554 27.245 ;
     RECT  12.96 27.139 13.662 27.301 ;
     RECT  26.352 27.211 27.234 27.301 ;
     RECT  44.712 27.175 48.51 27.301 ;
     RECT  68.976 27.175 70.362 27.301 ;
     RECT  16.272 27.203 17.01 27.329 ;
     RECT  68.904 27.301 70.362 27.329 ;
     RECT  0.108 26.825 8.406 27.341 ;
     RECT  12.96 27.301 13.734 27.341 ;
     RECT  68.904 27.329 70.218 27.341 ;
     RECT  17.856 27.203 25.398 27.365 ;
     RECT  32.328 27.103 43.362 27.365 ;
     RECT  29.415 21.965 29.697 27.409 ;
     RECT  44.712 27.301 48.69 27.409 ;
     RECT  14.832 26.717 15.498 27.481 ;
     RECT  16.272 27.329 16.902 27.481 ;
     RECT  14.724 27.481 16.902 27.571 ;
     RECT  32.688 27.365 43.362 27.599 ;
     RECT  17.856 27.365 21.546 27.635 ;
     RECT  22.32 27.365 25.398 27.715 ;
     RECT  26.172 27.301 27.234 27.715 ;
     RECT  71.172 26.969 73.854 27.715 ;
     RECT  74.7 27.131 75.798 27.715 ;
     RECT  9.144 26.825 12.006 27.751 ;
     RECT  12.96 27.341 13.497 27.751 ;
     RECT  29.376 27.409 29.697 27.751 ;
     RECT  71.172 27.715 75.798 27.751 ;
     RECT  30.78 27.245 30.978 27.779 ;
     RECT  44.172 27.409 48.69 27.779 ;
     RECT  22.32 27.715 27.234 27.841 ;
     RECT  29.376 27.751 30.042 27.841 ;
     RECT  17.964 27.635 21.546 27.869 ;
     RECT  32.688 27.599 43.254 27.869 ;
     RECT  76.572 27.239 83.214 27.869 ;
     RECT  22.32 27.841 27.45 27.877 ;
     RECT  32.688 27.869 33.102 27.905 ;
     RECT  44.244 27.779 48.69 27.905 ;
     RECT  14.652 27.571 16.902 27.931 ;
     RECT  22.32 27.877 27.594 27.931 ;
     RECT  49.5 27.059 49.806 27.931 ;
     RECT  76.608 27.869 83.214 27.941 ;
     RECT  1.728 27.341 8.406 27.949 ;
     RECT  9.144 27.751 13.497 27.949 ;
     RECT  22.32 27.931 28.134 27.949 ;
     RECT  29.232 27.841 30.042 27.949 ;
     RECT  30.78 27.779 30.87 27.949 ;
     RECT  44.64 27.905 48.69 27.949 ;
     RECT  49.5 27.931 49.986 27.949 ;
     RECT  22.32 27.949 30.87 28.049 ;
     RECT  0.108 27.341 0.558 28.075 ;
     RECT  1.728 27.949 13.497 28.075 ;
     RECT  58.896 26.563 58.914 28.111 ;
     RECT  71.136 27.751 75.798 28.162 ;
     RECT  58.896 28.111 59.094 28.183 ;
     RECT  58.788 28.183 59.094 28.247 ;
     RECT  14.508 27.931 16.902 28.255 ;
     RECT  44.64 27.949 49.986 28.267 ;
     RECT  0.108 28.075 13.497 28.291 ;
     RECT  14.292 28.255 16.902 28.291 ;
     RECT  0.108 28.291 16.902 28.301 ;
     RECT  1.152 28.301 16.902 28.381 ;
     RECT  22.32 28.049 28.278 28.409 ;
     RECT  58.788 28.247 58.806 28.409 ;
     RECT  1.152 28.381 17.154 28.417 ;
     RECT  17.964 27.869 21.402 28.417 ;
     RECT  61.815 26.429 62.097 28.417 ;
     RECT  68.976 27.341 70.218 28.417 ;
     RECT  1.152 28.417 21.402 28.445 ;
     RECT  29.052 28.049 30.87 28.445 ;
     RECT  22.32 28.409 28.206 28.481 ;
     RECT  29.415 28.445 30.87 28.481 ;
     RECT  34.308 27.869 43.254 28.489 ;
     RECT  60.3 28.381 60.318 28.489 ;
     RECT  61.2 28.417 62.097 28.489 ;
     RECT  71.136 28.162 75.762 28.489 ;
     RECT  0.108 28.301 0.342 28.493 ;
     RECT  68.868 28.417 70.218 28.493 ;
     RECT  34.308 28.489 43.326 28.507 ;
     RECT  51.015 25.781 51.297 28.507 ;
     RECT  44.64 28.267 50.094 28.525 ;
     RECT  50.904 28.507 51.297 28.525 ;
     RECT  22.32 28.481 27.954 28.561 ;
     RECT  0.288 28.493 0.306 28.589 ;
     RECT  71.028 28.489 75.762 28.589 ;
     RECT  14.256 28.445 21.402 28.645 ;
     RECT  22.212 28.561 27.954 28.645 ;
     RECT  14.256 28.645 27.954 28.679 ;
     RECT  14.256 28.679 15.858 28.715 ;
     RECT  60.3 28.489 62.097 28.715 ;
     RECT  71.388 28.589 75.762 28.715 ;
     RECT  34.308 28.507 43.434 28.723 ;
     RECT  44.64 28.525 51.297 28.723 ;
     RECT  14.796 28.715 15.858 28.733 ;
     RECT  16.74 28.679 26.55 28.733 ;
     RECT  68.976 28.493 70.218 28.759 ;
     RECT  17.496 28.733 26.55 28.787 ;
     RECT  58.14 28.489 58.734 28.787 ;
     RECT  60.552 28.715 62.097 28.787 ;
     RECT  14.796 28.733 15.606 28.823 ;
     RECT  27.36 28.679 27.954 28.823 ;
     RECT  30.78 28.481 30.87 28.823 ;
     RECT  30.78 28.823 30.798 28.859 ;
     RECT  17.496 28.787 21.042 28.949 ;
     RECT  27.792 28.823 27.954 28.949 ;
     RECT  76.968 27.941 83.214 28.949 ;
     RECT  27.792 28.949 27.81 28.985 ;
     RECT  34.308 28.723 51.297 28.985 ;
     RECT  71.424 28.715 75.762 28.987 ;
     RECT  43.992 28.985 45.99 29.057 ;
     RECT  68.976 28.759 70.506 29.057 ;
     RECT  68.976 29.057 70.218 29.093 ;
     RECT  46.764 28.985 51.297 29.101 ;
     RECT  63.432 28.993 63.45 29.101 ;
     RECT  77.796 28.949 83.214 29.101 ;
     RECT  21.816 28.787 26.55 29.219 ;
     RECT  21.816 29.219 26.37 29.255 ;
     RECT  46.764 29.101 51.354 29.255 ;
     RECT  58.14 28.787 58.158 29.255 ;
     RECT  77.796 29.101 83.25 29.261 ;
     RECT  63.216 29.101 63.45 29.263 ;
     RECT  63.216 29.263 63.666 29.371 ;
     RECT  17.568 28.949 21.042 29.399 ;
     RECT  26.244 29.255 26.37 29.399 ;
     RECT  47.988 29.255 51.354 29.399 ;
     RECT  16.74 28.733 16.758 29.461 ;
     RECT  1.152 28.445 13.497 29.489 ;
     RECT  19.944 29.399 21.042 29.489 ;
     RECT  47.988 29.399 51.297 29.489 ;
     RECT  63.216 29.371 63.846 29.489 ;
     RECT  0.144 29.275 0.162 29.497 ;
     RECT  71.424 28.987 76.95 29.497 ;
     RECT  1.152 29.489 12.006 29.525 ;
     RECT  43.992 29.057 45.954 29.525 ;
     RECT  47.988 29.489 50.094 29.525 ;
     RECT  50.904 29.489 51.297 29.525 ;
     RECT  63.216 29.489 63.774 29.525 ;
     RECT  71.352 29.497 76.95 29.569 ;
     RECT  14.832 28.823 15.606 29.597 ;
     RECT  53.892 29.335 53.982 29.597 ;
     RECT  63.396 29.525 63.774 29.597 ;
     RECT  68.976 29.093 70.146 29.597 ;
     RECT  12.888 29.489 13.497 29.611 ;
     RECT  21.816 29.255 22.446 29.611 ;
     RECT  46.764 29.255 47.214 29.633 ;
     RECT  14.868 29.597 15.606 29.641 ;
     RECT  16.524 29.461 16.758 29.641 ;
     RECT  19.944 29.489 20.898 29.645 ;
     RECT  69.012 29.597 70.146 29.645 ;
     RECT  71.244 29.569 76.95 29.669 ;
     RECT  12.888 29.611 13.95 29.731 ;
     RECT  14.868 29.641 16.794 29.759 ;
     RECT  21.672 29.611 22.446 29.759 ;
     RECT  17.568 29.399 18.897 29.795 ;
     RECT  19.944 29.645 20.682 29.795 ;
     RECT  49.176 29.525 49.518 29.795 ;
     RECT  61.2 28.787 62.097 29.795 ;
     RECT  63.432 29.597 63.774 29.795 ;
     RECT  0.108 29.497 0.162 29.837 ;
     RECT  54.324 29.803 54.522 29.839 ;
     RECT  18.468 29.795 18.897 29.867 ;
     RECT  20.592 29.795 20.682 29.867 ;
     RECT  15.48 29.759 16.794 29.875 ;
     RECT  17.568 29.795 17.73 29.875 ;
     RECT  77.796 29.261 83.214 29.875 ;
     RECT  20.592 29.867 20.61 29.903 ;
     RECT  58.716 29.875 58.734 29.911 ;
     RECT  61.815 29.795 62.097 29.911 ;
     RECT  63.612 29.795 63.774 29.939 ;
     RECT  0.144 29.837 0.162 29.995 ;
     RECT  56.415 24.665 56.697 30.001 ;
     RECT  57.708 29.533 57.726 30.001 ;
     RECT  1.152 29.525 9.702 30.029 ;
     RECT  21.96 29.759 22.446 30.029 ;
     RECT  23.364 29.255 25.362 30.029 ;
     RECT  49.212 29.795 49.518 30.029 ;
     RECT  58.716 29.911 58.806 30.029 ;
     RECT  61.815 29.911 62.37 30.029 ;
     RECT  66.708 24.169 67.806 30.029 ;
     RECT  71.244 29.669 76.482 30.029 ;
     RECT  69.768 29.645 70.146 30.037 ;
     RECT  21.96 30.029 22.302 30.065 ;
     RECT  0.144 29.995 0.342 30.125 ;
     RECT  58.716 30.029 58.734 30.137 ;
     RECT  66.744 30.029 67.806 30.137 ;
     RECT  34.308 28.985 43.218 30.145 ;
     RECT  25.344 30.029 25.362 30.181 ;
     RECT  26.352 29.399 26.37 30.181 ;
     RECT  44.424 29.525 45.954 30.209 ;
     RECT  63.684 29.939 63.774 30.209 ;
     RECT  23.364 30.029 24.498 30.221 ;
     RECT  12.888 29.731 14.094 30.271 ;
     RECT  44.568 30.209 45.954 30.271 ;
     RECT  50.976 29.525 51.297 30.271 ;
     RECT  15.48 29.875 17.73 30.299 ;
     RECT  25.344 30.181 26.37 30.299 ;
     RECT  44.568 30.271 46.026 30.335 ;
     RECT  54.324 29.839 54.738 30.343 ;
     RECT  1.152 30.029 8.946 30.371 ;
     RECT  23.364 30.221 24.297 30.371 ;
     RECT  44.64 30.335 46.026 30.371 ;
     RECT  58.644 30.271 58.662 30.407 ;
     RECT  9.684 30.029 9.702 30.415 ;
     RECT  10.548 29.525 12.006 30.415 ;
     RECT  47.196 29.633 47.214 30.415 ;
     RECT  53.964 30.343 54.738 30.415 ;
     RECT  69.012 29.645 69.03 30.451 ;
     RECT  69.768 30.037 70.362 30.451 ;
     RECT  1.152 30.371 1.17 30.479 ;
     RECT  23.616 30.371 24.297 30.479 ;
     RECT  69.012 30.451 70.362 30.541 ;
     RECT  71.244 30.029 73.854 30.541 ;
     RECT  15.48 30.299 17.658 30.569 ;
     RECT  44.64 30.371 45.897 30.569 ;
     RECT  46.764 30.415 47.214 30.569 ;
     RECT  74.7 30.029 76.482 30.569 ;
     RECT  56.415 30.001 57.726 30.571 ;
     RECT  58.572 30.541 58.59 30.571 ;
     RECT  44.784 30.569 45.897 30.605 ;
     RECT  52.992 30.145 53.01 30.605 ;
     RECT  53.964 30.415 54.81 30.605 ;
     RECT  56.415 30.571 58.59 30.605 ;
     RECT  77.58 29.875 83.214 30.605 ;
     RECT  69.012 30.541 73.854 30.613 ;
     RECT  74.7 30.569 76.23 30.641 ;
     RECT  56.415 30.605 56.697 30.667 ;
     RECT  54.072 30.605 54.81 30.677 ;
     RECT  57.78 30.605 58.59 30.677 ;
     RECT  54.072 30.677 54.738 30.701 ;
     RECT  34.308 30.145 43.614 30.712 ;
     RECT  57.78 30.677 58.086 30.713 ;
     RECT  15.48 30.569 17.118 30.721 ;
     RECT  77.58 30.605 83.178 30.721 ;
     RECT  34.308 30.712 43.65 30.749 ;
     RECT  57.78 30.713 58.05 30.749 ;
     RECT  77.4 30.721 83.178 30.749 ;
     RECT  57.78 30.749 57.798 30.755 ;
     RECT  34.308 30.749 42.498 30.797 ;
     RECT  25.344 30.299 25.434 30.811 ;
     RECT  47.196 30.569 47.214 30.811 ;
     RECT  47.988 29.525 48.294 30.811 ;
     RECT  49.5 30.029 49.518 30.811 ;
     RECT  14.94 30.721 17.118 30.839 ;
     RECT  47.196 30.811 48.294 30.839 ;
     RECT  49.5 30.811 49.59 30.839 ;
     RECT  68.976 30.613 73.854 30.839 ;
     RECT  74.7 30.641 76.194 30.839 ;
     RECT  14.94 30.839 16.29 30.875 ;
     RECT  34.308 30.797 42.426 30.875 ;
     RECT  43.38 30.749 43.65 30.875 ;
     RECT  77.4 30.749 82.782 30.883 ;
     RECT  77.004 30.883 82.782 30.893 ;
     RECT  9.684 30.415 12.006 30.907 ;
     RECT  12.852 30.271 14.094 30.907 ;
     RECT  17.1 30.839 17.118 30.911 ;
     RECT  84.06 30.763 84.078 30.941 ;
     RECT  43.452 30.875 43.65 30.983 ;
     RECT  0.216 30.125 0.234 30.989 ;
     RECT  9.684 30.907 14.094 30.991 ;
     RECT  14.94 30.875 16.182 30.991 ;
     RECT  69.048 30.839 73.854 30.991 ;
     RECT  43.632 30.983 43.65 31.145 ;
     RECT  54.072 30.701 54.306 31.145 ;
     RECT  9.684 30.991 16.182 31.181 ;
     RECT  2.268 30.371 8.946 31.189 ;
     RECT  9.684 31.181 10.782 31.189 ;
     RECT  69.048 30.991 73.962 31.243 ;
     RECT  74.7 30.839 76.086 31.243 ;
     RECT  2.268 31.189 10.782 31.289 ;
     RECT  58.968 31.189 58.986 31.289 ;
     RECT  69.048 31.243 76.086 31.289 ;
     RECT  2.268 31.289 8.91 31.325 ;
     RECT  9.864 31.289 10.782 31.379 ;
     RECT  2.268 31.325 8.586 31.415 ;
     RECT  9.864 31.379 10.638 31.415 ;
     RECT  55.908 30.667 56.697 31.423 ;
     RECT  10.08 31.415 10.638 31.523 ;
     RECT  54.288 31.145 54.306 31.523 ;
     RECT  0.144 31.225 0.198 31.531 ;
     RECT  28.188 31.459 28.206 31.531 ;
     RECT  67.215 30.137 67.806 31.531 ;
     RECT  82.08 30.893 82.782 31.531 ;
     RECT  50.724 30.271 51.297 31.559 ;
     RECT  55.584 31.423 56.697 31.559 ;
     RECT  74.736 31.289 76.086 31.621 ;
     RECT  77.004 30.893 81.342 31.621 ;
     RECT  11.52 31.181 16.038 31.649 ;
     RECT  36.504 30.875 42.426 31.649 ;
     RECT  55.584 31.559 55.674 31.649 ;
     RECT  69.048 31.289 73.854 31.649 ;
     RECT  27.144 31.657 27.162 31.709 ;
     RECT  69.048 31.649 69.786 31.729 ;
     RECT  68.976 31.729 69.786 31.757 ;
     RECT  66.708 31.531 67.806 31.765 ;
     RECT  74.736 31.621 81.342 31.765 ;
     RECT  82.08 31.531 83.214 31.765 ;
     RECT  27.936 31.531 28.206 31.801 ;
     RECT  56.415 31.559 56.697 31.801 ;
     RECT  27.396 31.801 28.206 31.919 ;
     RECT  36.504 31.649 39.474 31.919 ;
     RECT  68.976 31.757 68.994 31.919 ;
     RECT  70.632 31.649 73.854 31.919 ;
     RECT  61.815 30.029 62.097 31.927 ;
     RECT  2.268 31.415 8.406 32.027 ;
     RECT  11.592 31.649 16.038 32.071 ;
     RECT  48.06 30.839 48.294 32.155 ;
     RECT  27.396 31.919 28.134 32.189 ;
     RECT  56.415 31.801 56.79 32.189 ;
     RECT  11.592 32.071 16.074 32.225 ;
     RECT  27.396 32.189 28.026 32.225 ;
     RECT  40.215 31.649 42.426 32.225 ;
     RECT  0.108 31.531 0.198 32.237 ;
     RECT  10.08 31.523 10.422 32.269 ;
     RECT  11.592 32.225 13.842 32.297 ;
     RECT  14.76 32.225 16.074 32.297 ;
     RECT  9.792 32.269 10.422 32.341 ;
     RECT  66.276 31.765 67.806 32.341 ;
     RECT  47.268 30.839 47.286 32.395 ;
     RECT  9.648 32.341 10.422 32.431 ;
     RECT  11.592 32.297 13.77 32.431 ;
     RECT  46.656 32.395 47.286 32.431 ;
     RECT  48.06 32.155 48.834 32.431 ;
     RECT  11.412 32.431 13.77 32.459 ;
     RECT  46.656 32.431 48.834 32.459 ;
     RECT  66.276 32.341 68.13 32.459 ;
     RECT  14.76 32.297 15.174 32.477 ;
     RECT  66.708 32.459 68.13 32.495 ;
     RECT  0.108 32.237 0.162 32.525 ;
     RECT  74.736 31.765 83.214 32.531 ;
     RECT  78.015 32.531 83.214 32.539 ;
     RECT  60.66 31.927 60.678 32.575 ;
     RECT  61.815 31.927 62.73 32.575 ;
     RECT  46.728 32.459 48.834 32.611 ;
     RECT  49.572 30.839 49.59 32.611 ;
     RECT  60.66 32.575 62.73 32.611 ;
     RECT  70.776 31.919 73.854 32.611 ;
     RECT  74.736 32.531 77.094 32.611 ;
     RECT  60.66 32.611 62.766 32.729 ;
     RECT  70.776 32.611 77.094 32.729 ;
     RECT  26.352 30.299 26.37 32.731 ;
     RECT  9.144 32.431 10.458 32.809 ;
     RECT  11.412 32.459 12.15 32.809 ;
     RECT  26.352 32.731 26.406 32.881 ;
     RECT  27.396 32.225 27.45 32.881 ;
     RECT  61.815 32.729 62.766 32.881 ;
     RECT  69.768 31.757 69.786 32.881 ;
     RECT  70.776 32.729 74.034 32.881 ;
     RECT  68.868 32.467 68.886 32.965 ;
     RECT  69.624 32.881 74.034 32.965 ;
     RECT  2.304 32.027 8.406 32.971 ;
     RECT  54.972 32.845 54.99 32.971 ;
     RECT  27.324 32.881 27.45 32.999 ;
     RECT  54.684 32.971 54.99 32.999 ;
     RECT  66.708 32.495 68.094 32.999 ;
     RECT  27.324 32.999 27.342 33.035 ;
     RECT  60.66 32.729 61.002 33.035 ;
     RECT  74.808 32.729 77.094 33.035 ;
     RECT  2.268 32.971 8.406 33.043 ;
     RECT  9.144 32.809 12.15 33.043 ;
     RECT  16.056 32.297 16.074 33.043 ;
     RECT  61.815 32.881 63.09 33.043 ;
     RECT  63.864 32.845 63.882 33.043 ;
     RECT  0.144 32.525 0.162 33.053 ;
     RECT  68.868 32.965 74.034 33.053 ;
     RECT  16.056 33.043 16.29 33.067 ;
     RECT  74.916 33.035 77.094 33.071 ;
     RECT  36.504 31.919 39.294 33.079 ;
     RECT  40.215 32.225 41.058 33.079 ;
     RECT  54.684 32.999 54.918 33.079 ;
     RECT  2.268 33.043 12.15 33.115 ;
     RECT  46.728 32.611 49.59 33.115 ;
     RECT  51.015 31.559 51.297 33.115 ;
     RECT  14.76 32.477 14.922 33.151 ;
     RECT  18.615 29.867 18.897 33.151 ;
     RECT  46.728 33.115 50.238 33.151 ;
     RECT  51.015 33.115 51.678 33.151 ;
     RECT  13.032 32.459 13.77 33.241 ;
     RECT  66.708 32.999 67.734 33.241 ;
     RECT  53.82 33.079 54.918 33.269 ;
     RECT  60.66 33.035 60.678 33.269 ;
     RECT  14.652 33.151 14.922 33.277 ;
     RECT  18 33.151 18.897 33.277 ;
     RECT  16.02 33.067 16.29 33.305 ;
     RECT  61.815 33.043 63.882 33.305 ;
     RECT  2.232 33.115 12.15 33.313 ;
     RECT  12.924 33.241 13.77 33.313 ;
     RECT  17.964 33.277 18.897 33.349 ;
     RECT  66.672 33.241 67.734 33.349 ;
     RECT  2.232 33.313 13.806 33.355 ;
     RECT  84.132 32.587 84.15 33.377 ;
     RECT  78.015 32.539 83.25 33.385 ;
     RECT  1.728 33.355 13.806 33.403 ;
     RECT  1.152 33.403 13.806 33.421 ;
     RECT  53.82 33.269 53.838 33.421 ;
     RECT  17.928 33.349 18.897 33.449 ;
     RECT  64.476 33.313 64.602 33.449 ;
     RECT  66.6 33.349 67.734 33.449 ;
     RECT  53.136 33.421 53.838 33.485 ;
     RECT  45.144 30.605 45.897 33.511 ;
     RECT  46.728 33.151 51.678 33.511 ;
     RECT  45.144 33.511 51.678 33.575 ;
     RECT  53.28 33.485 53.838 33.575 ;
     RECT  60.444 33.385 60.462 33.575 ;
     RECT  61.815 33.305 63.63 33.575 ;
     RECT  68.868 33.053 73.854 33.575 ;
     RECT  45.144 33.575 48.798 33.583 ;
     RECT  49.572 33.575 51.678 33.619 ;
     RECT  77.976 33.385 83.25 33.655 ;
     RECT  14.652 33.277 14.994 33.691 ;
     RECT  16.02 33.305 16.182 33.691 ;
     RECT  33.084 33.619 33.102 33.691 ;
     RECT  45.072 33.583 48.798 33.691 ;
     RECT  49.572 33.619 52.254 33.691 ;
     RECT  61.815 33.575 62.766 33.691 ;
     RECT  63.612 33.575 63.63 33.719 ;
     RECT  77.976 33.655 83.358 33.719 ;
     RECT  69.768 33.575 73.854 33.781 ;
     RECT  74.916 33.071 76.086 33.781 ;
     RECT  0.324 33.421 13.806 33.787 ;
     RECT  14.652 33.691 15.174 33.787 ;
     RECT  15.948 33.691 16.182 33.809 ;
     RECT  45 33.691 48.798 33.809 ;
     RECT  64.476 33.449 64.494 33.809 ;
     RECT  21.78 32.809 21.798 33.817 ;
     RECT  15.948 33.809 15.966 33.845 ;
     RECT  61.74 33.691 62.766 33.845 ;
     RECT  26.352 32.881 26.55 33.853 ;
     RECT  69.768 33.781 76.086 33.889 ;
     RECT  77.004 33.071 77.094 33.889 ;
     RECT  0.324 33.787 15.174 33.917 ;
     RECT  33.084 33.691 33.138 33.917 ;
     RECT  0.324 33.917 15.066 33.925 ;
     RECT  26.352 33.853 26.694 33.925 ;
     RECT  44.064 33.853 44.082 33.961 ;
     RECT  45 33.809 48.51 33.961 ;
     RECT  33.12 33.917 33.138 33.989 ;
     RECT  78.015 33.719 83.358 33.989 ;
     RECT  0.108 33.925 15.066 34.079 ;
     RECT  26.352 33.925 26.73 34.079 ;
     RECT  60.192 33.655 60.39 34.079 ;
     RECT  25.272 30.811 25.434 34.087 ;
     RECT  36.504 33.079 41.058 34.115 ;
     RECT  49.572 33.691 52.434 34.115 ;
     RECT  60.192 34.079 60.21 34.115 ;
     RECT  21.78 33.817 21.834 34.123 ;
     RECT  58.716 33.421 58.734 34.123 ;
     RECT  22.86 33.853 22.878 34.151 ;
     RECT  26.352 34.079 26.694 34.151 ;
     RECT  26.352 34.151 26.658 34.159 ;
     RECT  25.2 34.087 25.434 34.205 ;
     RECT  26.28 34.159 26.658 34.231 ;
     RECT  44.064 33.961 48.51 34.231 ;
     RECT  66.744 33.449 67.734 34.231 ;
     RECT  36.504 34.115 39.294 34.321 ;
     RECT  56.415 32.189 56.697 34.321 ;
     RECT  82.656 33.989 83.358 34.349 ;
     RECT  68.868 33.575 68.994 34.357 ;
     RECT  17.964 33.449 18.897 34.385 ;
     RECT  58.248 34.123 58.734 34.385 ;
     RECT  21.132 34.123 21.834 34.393 ;
     RECT  34.308 30.875 35.73 34.393 ;
     RECT  36.468 34.321 39.294 34.393 ;
     RECT  30.78 34.231 30.798 34.429 ;
     RECT  56.415 34.321 57.33 34.457 ;
     RECT  54.684 33.269 54.702 34.493 ;
     RECT  50.652 34.115 52.434 34.501 ;
     RECT  66.708 34.231 67.734 34.501 ;
     RECT  68.832 34.357 68.994 34.501 ;
     RECT  30.78 34.429 30.906 34.529 ;
     RECT  43.776 34.231 48.51 34.619 ;
     RECT  66.024 34.501 68.994 34.619 ;
     RECT  26.172 34.231 26.658 34.655 ;
     RECT  69.768 33.889 77.094 34.655 ;
     RECT  50.652 34.501 52.542 34.663 ;
     RECT  53.28 33.575 53.658 34.663 ;
     RECT  30.852 34.529 30.906 34.691 ;
     RECT  58.716 34.385 58.734 34.727 ;
     RECT  30.852 34.691 30.87 34.763 ;
     RECT  25.344 34.205 25.434 34.771 ;
     RECT  33.516 34.699 33.534 34.771 ;
     RECT  34.308 34.393 39.294 34.771 ;
     RECT  43.776 34.619 44.37 34.771 ;
     RECT  45.144 34.619 48.51 34.771 ;
     RECT  49.572 34.115 49.662 34.771 ;
     RECT  14.724 34.079 15.066 34.795 ;
     RECT  43.704 34.771 44.37 34.829 ;
     RECT  0.108 34.079 13.806 34.861 ;
     RECT  14.724 34.795 15.174 34.861 ;
     RECT  78.015 33.989 81.738 34.891 ;
     RECT  82.656 34.349 83.25 34.891 ;
     RECT  33.516 34.771 39.294 34.897 ;
     RECT  50.652 34.663 53.658 34.897 ;
     RECT  74.736 34.655 77.094 34.897 ;
     RECT  78.015 34.891 83.25 34.897 ;
     RECT  50.58 34.897 53.658 34.925 ;
     RECT  21.132 34.393 22.842 34.933 ;
     RECT  26.388 34.655 26.658 34.933 ;
     RECT  65.016 34.771 65.034 34.933 ;
     RECT  41.976 32.225 42.426 34.939 ;
     RECT  61.815 33.845 62.73 34.939 ;
     RECT  41.976 34.939 42.678 34.969 ;
     RECT  24.015 30.479 24.297 35.005 ;
     RECT  41.976 34.969 42.786 35.005 ;
     RECT  45.144 34.771 49.662 35.005 ;
     RECT  50.58 34.925 51.858 35.005 ;
     RECT  0.108 34.861 15.174 35.041 ;
     RECT  15.948 34.591 15.966 35.041 ;
     RECT  18.072 34.385 18.897 35.041 ;
     RECT  52.956 34.925 53.658 35.041 ;
     RECT  26.388 34.933 26.874 35.069 ;
     RECT  18.072 35.041 19.566 35.159 ;
     RECT  21.132 34.933 22.878 35.159 ;
     RECT  45.144 35.005 51.858 35.159 ;
     RECT  52.956 35.041 54.054 35.159 ;
     RECT  57.564 34.861 57.618 35.159 ;
     RECT  25.344 34.771 25.65 35.195 ;
     RECT  45.144 35.159 49.95 35.195 ;
     RECT  53.748 35.159 54.054 35.195 ;
     RECT  66.024 34.619 68.886 35.195 ;
     RECT  45.144 35.195 49.698 35.213 ;
     RECT  74.736 34.897 83.25 35.213 ;
     RECT  50.688 35.159 51.75 35.231 ;
     RECT  26.46 35.069 26.874 35.239 ;
     RECT  26.46 35.239 27.378 35.267 ;
     RECT  45.144 35.213 48.69 35.267 ;
     RECT  74.736 35.213 83.214 35.267 ;
     RECT  50.688 35.231 51.678 35.303 ;
     RECT  54 35.195 54.054 35.303 ;
     RECT  57.6 35.159 57.618 35.357 ;
     RECT  26.784 35.267 27.378 35.371 ;
     RECT  29.415 28.481 29.697 35.371 ;
     RECT  17.136 33.511 17.154 35.401 ;
     RECT  33.084 34.897 39.294 35.401 ;
     RECT  64.836 34.933 65.034 35.401 ;
     RECT  29.415 35.371 29.79 35.429 ;
     RECT  49.5 35.213 49.698 35.429 ;
     RECT  50.688 35.303 51.39 35.429 ;
     RECT  52.956 35.159 52.974 35.429 ;
     RECT  41.976 35.005 42.966 35.437 ;
     RECT  56.415 34.457 56.697 35.437 ;
     RECT  49.5 35.429 49.59 35.465 ;
     RECT  16.776 35.401 17.154 35.509 ;
     RECT  64.836 35.401 65.214 35.509 ;
     RECT  66.024 35.195 68.094 35.509 ;
     RECT  74.736 35.267 82.17 35.509 ;
     RECT  64.836 35.509 68.094 35.515 ;
     RECT  24.015 35.005 24.39 35.563 ;
     RECT  56.415 35.437 56.718 35.563 ;
     RECT  18.072 35.159 18.99 35.581 ;
     RECT  26.784 35.371 27.954 35.581 ;
     RECT  61.815 34.939 62.766 35.581 ;
     RECT  30.708 35.581 30.726 35.611 ;
     RECT  64.728 35.515 68.094 35.611 ;
     RECT  54.72 35.437 54.774 35.612 ;
     RECT  56.304 35.563 56.718 35.612 ;
     RECT  30.708 35.611 30.834 35.659 ;
     RECT  59.004 35.611 59.022 35.659 ;
     RECT  40.215 34.115 41.058 35.671 ;
     RECT  41.904 35.437 42.966 35.671 ;
     RECT  43.956 34.829 44.37 35.671 ;
     RECT  40.215 35.671 44.37 35.693 ;
     RECT  41.976 35.693 44.37 35.699 ;
     RECT  56.304 35.612 56.697 35.699 ;
     RECT  23.904 35.563 24.39 35.707 ;
     RECT  64.656 35.611 68.094 35.707 ;
     RECT  0.108 35.041 15.966 35.735 ;
     RECT  46.8 35.267 48.69 35.741 ;
     RECT  30.708 35.659 30.906 35.743 ;
     RECT  69.768 34.655 73.854 35.743 ;
     RECT  74.592 35.509 82.17 35.743 ;
     RECT  58.932 35.659 59.022 35.755 ;
     RECT  23.904 35.707 24.534 35.771 ;
     RECT  64.548 35.707 68.094 35.771 ;
     RECT  46.908 35.741 48.69 35.789 ;
     RECT  69.768 35.743 82.17 35.789 ;
     RECT  16.704 35.509 17.154 35.803 ;
     RECT  17.892 35.581 18.99 35.803 ;
     RECT  65.124 35.771 68.094 35.807 ;
     RECT  84.132 35.371 84.15 35.807 ;
     RECT  33.084 35.401 39.474 35.851 ;
     RECT  40.215 35.693 41.202 35.851 ;
     RECT  45.144 35.267 45.99 35.851 ;
     RECT  61.815 35.581 62.838 35.879 ;
     RECT  58.716 35.755 59.022 35.885 ;
     RECT  16.704 35.803 18.99 35.941 ;
     RECT  20.268 35.437 20.286 35.941 ;
     RECT  65.34 35.807 68.094 35.941 ;
     RECT  68.868 35.195 68.886 35.941 ;
     RECT  20.196 35.941 20.286 35.969 ;
     RECT  45.072 35.851 45.99 35.969 ;
     RECT  65.34 35.941 68.886 35.969 ;
     RECT  1.728 35.735 15.966 35.977 ;
     RECT  16.704 35.941 19.026 35.977 ;
     RECT  1.728 35.977 19.062 36.005 ;
     RECT  22.68 35.159 22.878 36.013 ;
     RECT  59.436 35.941 59.454 36.013 ;
     RECT  26.784 35.581 27.99 36.043 ;
     RECT  20.196 35.969 20.214 36.049 ;
     RECT  21.132 35.159 21.906 36.049 ;
     RECT  22.68 36.013 22.914 36.049 ;
     RECT  23.904 35.771 24.39 36.049 ;
     RECT  26.712 36.043 27.99 36.113 ;
     RECT  54.72 35.612 54.738 36.113 ;
     RECT  59.436 36.013 59.706 36.113 ;
     RECT  45.615 35.969 45.99 36.121 ;
     RECT  45.615 36.121 46.026 36.173 ;
     RECT  46.944 35.789 48.69 36.239 ;
     RECT  65.628 35.969 68.886 36.283 ;
     RECT  69.768 35.789 73.89 36.283 ;
     RECT  59.616 36.113 59.634 36.311 ;
     RECT  2.304 36.005 19.062 36.319 ;
     RECT  20.052 36.049 20.214 36.319 ;
     RECT  46.944 36.239 48.366 36.347 ;
     RECT  0.108 35.735 0.558 36.365 ;
     RECT  21.132 36.049 24.39 36.383 ;
     RECT  29.415 35.429 29.697 36.391 ;
     RECT  30.708 35.743 30.942 36.391 ;
     RECT  61.815 35.879 62.766 36.419 ;
     RECT  0.108 36.365 0.27 36.461 ;
     RECT  21.132 36.383 22.986 36.475 ;
     RECT  56.415 35.699 56.697 36.475 ;
     RECT  33.084 35.851 41.202 36.509 ;
     RECT  47.988 36.347 48.366 36.509 ;
     RECT  45.615 36.173 45.99 36.515 ;
     RECT  51.015 35.429 51.39 36.515 ;
     RECT  56.415 36.475 56.79 36.515 ;
     RECT  26.784 36.113 27.99 36.517 ;
     RECT  65.628 36.283 73.89 36.589 ;
     RECT  74.628 35.789 82.17 36.589 ;
     RECT  83.088 35.267 83.214 36.589 ;
     RECT  26.784 36.517 28.314 36.661 ;
     RECT  2.304 36.319 20.214 36.715 ;
     RECT  26.784 36.661 28.35 36.715 ;
     RECT  31.896 36.553 31.914 36.749 ;
     RECT  25.344 35.195 25.434 36.751 ;
     RECT  29.415 36.391 30.942 36.751 ;
     RECT  45.615 36.515 45.897 36.751 ;
     RECT  56.415 36.515 56.697 36.751 ;
     RECT  40.176 36.509 41.202 36.763 ;
     RECT  41.976 35.699 44.01 36.763 ;
     RECT  40.176 36.763 44.01 36.779 ;
     RECT  21.096 36.475 22.986 36.823 ;
     RECT  21.06 36.823 22.986 36.859 ;
     RECT  26.784 36.715 28.422 36.859 ;
     RECT  45.504 36.751 45.897 36.895 ;
     RECT  2.304 36.715 20.25 36.896 ;
     RECT  46.944 36.347 47.214 36.907 ;
     RECT  40.215 36.779 44.01 36.931 ;
     RECT  46.872 36.907 47.214 36.931 ;
     RECT  45.18 36.895 45.897 36.941 ;
     RECT  29.415 36.751 30.978 36.959 ;
     RECT  33.084 36.509 39.294 36.959 ;
     RECT  26.784 36.859 28.494 36.989 ;
     RECT  17.496 36.896 20.25 37.021 ;
     RECT  21.024 36.859 22.986 37.021 ;
     RECT  30.6 36.959 30.978 37.021 ;
     RECT  2.304 36.896 16.614 37.049 ;
     RECT  17.496 37.021 22.986 37.049 ;
     RECT  26.784 36.989 28.422 37.049 ;
     RECT  30.6 37.021 31.158 37.049 ;
     RECT  40.215 36.931 44.082 37.049 ;
     RECT  48.168 36.509 48.33 37.049 ;
     RECT  24.015 36.383 24.39 37.057 ;
     RECT  29.415 36.959 29.79 37.085 ;
     RECT  40.215 37.049 42.786 37.085 ;
     RECT  46.8 36.931 47.214 37.085 ;
     RECT  30.78 37.049 31.158 37.093 ;
     RECT  36.54 36.959 39.294 37.133 ;
     RECT  61.815 36.419 62.73 37.165 ;
     RECT  24.015 37.057 24.498 37.193 ;
     RECT  56.304 36.751 56.697 37.229 ;
     RECT  1.152 37.093 1.17 37.291 ;
     RECT  2.304 37.049 16.542 37.291 ;
     RECT  18.252 37.049 22.986 37.291 ;
     RECT  65.628 36.589 83.214 37.291 ;
     RECT  24.015 37.193 24.354 37.319 ;
     RECT  40.215 37.085 41.994 37.319 ;
     RECT  45.324 36.941 45.897 37.319 ;
     RECT  49.572 35.465 49.59 37.319 ;
     RECT  63.9 37.051 63.918 37.319 ;
     RECT  48.312 37.049 48.33 37.355 ;
     RECT  33.084 36.959 35.802 37.363 ;
     RECT  32.94 37.363 35.802 37.391 ;
     RECT  36.54 37.133 38.142 37.391 ;
     RECT  18.252 37.291 23.274 37.427 ;
     RECT  26.784 37.049 28.386 37.427 ;
     RECT  61.815 37.165 62.766 37.427 ;
     RECT  26.784 37.427 27.738 37.463 ;
     RECT  30.78 37.093 31.59 37.463 ;
     RECT  25.344 36.751 25.902 37.471 ;
     RECT  26.784 37.463 27.126 37.471 ;
     RECT  32.94 37.391 33.426 37.471 ;
     RECT  30.78 37.463 31.554 37.499 ;
     RECT  32.76 37.471 33.426 37.561 ;
     RECT  65.448 37.291 83.214 37.561 ;
     RECT  43.884 37.049 43.902 37.589 ;
     RECT  46.908 37.085 47.214 37.589 ;
     RECT  49.248 37.471 49.41 37.589 ;
     RECT  64.944 37.561 83.214 37.589 ;
     RECT  32.688 37.561 33.426 37.613 ;
     RECT  58.716 37.387 58.734 37.613 ;
     RECT  64.944 37.589 76.374 37.613 ;
     RECT  31.536 37.499 31.554 37.625 ;
     RECT  32.76 37.613 33.102 37.625 ;
     RECT  49.248 37.589 49.266 37.625 ;
     RECT  68.544 37.613 76.374 37.625 ;
     RECT  17.496 37.049 17.514 37.675 ;
     RECT  24.015 37.319 24.297 37.705 ;
     RECT  34.308 37.391 35.802 37.705 ;
     RECT  36.54 37.391 37.35 37.705 ;
     RECT  25.344 37.471 27.126 37.769 ;
     RECT  68.868 37.625 76.374 37.769 ;
     RECT  17.424 37.675 17.514 37.859 ;
     RECT  18.252 37.427 22.95 37.859 ;
     RECT  34.308 37.705 37.35 37.859 ;
     RECT  1.152 37.291 16.542 37.861 ;
     RECT  17.46 37.859 17.514 37.861 ;
     RECT  18.252 37.859 19.854 37.861 ;
     RECT  51.015 36.515 51.297 37.867 ;
     RECT  64.944 37.613 67.77 37.867 ;
     RECT  23.94 37.705 24.297 37.895 ;
     RECT  46.908 37.589 47.142 37.895 ;
     RECT  64.368 37.867 67.77 37.895 ;
     RECT  0.108 36.461 0.234 37.903 ;
     RECT  1.152 37.861 16.578 37.903 ;
     RECT  33.084 37.625 33.102 37.931 ;
     RECT  34.308 37.859 36.414 37.931 ;
     RECT  25.344 37.769 26.514 37.967 ;
     RECT  42.768 37.085 42.786 37.967 ;
     RECT  47.124 37.895 47.142 37.967 ;
     RECT  0.108 37.903 0.306 38.011 ;
     RECT  1.152 37.903 16.722 38.011 ;
     RECT  68.868 37.769 70.29 38.039 ;
     RECT  0.108 38.011 16.722 38.129 ;
     RECT  34.308 37.931 36.27 38.129 ;
     RECT  37.332 37.859 37.35 38.129 ;
     RECT  54.684 38.011 54.702 38.129 ;
     RECT  64.368 37.895 64.53 38.129 ;
     RECT  84.132 36.811 84.15 38.155 ;
     RECT  20.592 37.859 22.95 38.165 ;
     RECT  36.252 38.129 36.27 38.165 ;
     RECT  51.012 37.867 51.297 38.165 ;
     RECT  84.096 38.155 84.15 38.173 ;
     RECT  0.108 38.129 16.542 38.189 ;
     RECT  12.06 38.189 16.542 38.201 ;
     RECT  20.592 38.165 22.23 38.201 ;
     RECT  64.224 38.155 64.242 38.201 ;
     RECT  69.696 38.039 70.29 38.201 ;
     RECT  0.108 38.189 11.322 38.237 ;
     RECT  69.768 38.201 70.29 38.237 ;
     RECT  71.1 37.769 76.374 38.237 ;
     RECT  17.46 37.861 19.854 38.399 ;
     RECT  25.344 37.967 26.226 38.399 ;
     RECT  34.308 38.129 35.154 38.399 ;
     RECT  18.216 38.399 19.854 38.429 ;
     RECT  2.268 38.237 11.322 38.435 ;
     RECT  65.376 37.895 67.77 38.435 ;
     RECT  66.492 38.435 67.77 38.443 ;
     RECT  68.868 38.039 68.886 38.443 ;
     RECT  0.108 38.237 1.458 38.477 ;
     RECT  18.216 38.429 19.782 38.477 ;
     RECT  25.344 38.399 25.686 38.507 ;
     RECT  66.492 38.443 68.886 38.507 ;
     RECT  84.096 38.173 84.222 38.539 ;
     RECT  74.664 38.237 76.374 38.551 ;
     RECT  77.22 37.589 83.214 38.551 ;
     RECT  84.06 38.539 84.222 38.635 ;
     RECT  48.78 38.635 48.798 38.641 ;
     RECT  2.268 38.435 9.486 38.669 ;
     RECT  17.46 38.399 17.478 38.669 ;
     RECT  20.772 38.201 22.23 38.669 ;
     RECT  66.492 38.507 67.662 38.669 ;
     RECT  74.664 38.551 83.214 38.669 ;
     RECT  48.456 38.641 48.798 38.675 ;
     RECT  2.268 38.669 9.342 38.705 ;
     RECT  66.492 38.669 67.59 38.717 ;
     RECT  20.772 38.669 21.834 38.741 ;
     RECT  47.664 38.641 47.682 38.765 ;
     RECT  71.1 38.237 73.854 38.821 ;
     RECT  84.024 38.635 84.222 38.827 ;
     RECT  76.5 38.669 82.926 38.849 ;
     RECT  12.06 38.201 14.634 38.939 ;
     RECT  15.408 38.201 16.254 38.939 ;
     RECT  18.216 38.477 19.602 38.939 ;
     RECT  48.456 38.675 48.582 38.939 ;
     RECT  65.376 38.435 65.754 38.939 ;
     RECT  47.7 38.911 47.718 38.947 ;
     RECT  48.456 38.939 48.474 38.947 ;
     RECT  0.108 38.477 0.306 38.957 ;
     RECT  68.4 38.507 68.886 38.975 ;
     RECT  61.02 38.923 61.038 38.983 ;
     RECT  61.815 37.427 62.73 38.983 ;
     RECT  47.7 38.947 48.474 39.011 ;
     RECT  59.976 38.983 59.994 39.019 ;
     RECT  61.02 38.983 62.73 39.019 ;
     RECT  69.768 38.237 69.822 39.047 ;
     RECT  47.736 39.011 48.402 39.056 ;
     RECT  47.736 39.056 47.79 39.083 ;
     RECT  58.788 38.947 58.806 39.119 ;
     RECT  59.976 39.019 62.73 39.119 ;
     RECT  0.144 38.957 0.306 39.149 ;
     RECT  18.216 38.939 19.458 39.209 ;
     RECT  0.252 39.149 0.306 39.245 ;
     RECT  59.976 39.119 60.606 39.245 ;
     RECT  65.376 38.939 65.61 39.245 ;
     RECT  66.528 38.717 67.59 39.245 ;
     RECT  10.404 38.435 11.322 39.289 ;
     RECT  60.012 39.245 60.606 39.317 ;
     RECT  70.704 38.821 73.854 39.317 ;
     RECT  65.592 39.245 65.61 39.341 ;
     RECT  71.424 39.317 73.854 39.341 ;
     RECT  60.012 39.317 60.03 39.353 ;
     RECT  66.6 39.245 67.59 39.479 ;
     RECT  66.6 39.479 67.497 39.515 ;
     RECT  0.288 39.245 0.306 39.595 ;
     RECT  1.152 38.477 1.458 39.595 ;
     RECT  10.368 39.289 11.322 39.595 ;
     RECT  2.268 38.705 9.306 39.631 ;
     RECT  10.224 39.595 11.322 39.631 ;
     RECT  18.216 39.209 19.314 39.659 ;
     RECT  77.22 38.849 82.926 39.659 ;
     RECT  0.288 39.595 1.458 39.725 ;
     RECT  0.504 39.725 1.458 39.821 ;
     RECT  83.988 38.827 84.222 39.857 ;
     RECT  2.268 39.631 11.322 39.865 ;
     RECT  12.06 38.939 14.202 39.865 ;
     RECT  45.615 37.319 45.897 39.883 ;
     RECT  74.916 38.669 75.69 39.901 ;
     RECT  16.236 38.939 16.254 39.929 ;
     RECT  2.268 39.865 14.202 40.027 ;
     RECT  15.048 39.055 15.066 40.027 ;
     RECT  18.615 39.659 19.314 40.055 ;
     RECT  1.404 39.821 1.458 40.109 ;
     RECT  2.268 40.027 15.066 40.199 ;
     RECT  2.268 40.199 9.81 40.289 ;
     RECT  10.656 40.199 15.066 40.289 ;
     RECT  84.132 39.857 84.222 40.289 ;
     RECT  0.504 39.821 0.558 40.301 ;
     RECT  2.268 40.289 9.306 40.325 ;
     RECT  84.132 40.289 84.15 40.397 ;
     RECT  10.836 40.289 15.066 40.433 ;
     RECT  45.504 39.883 45.897 40.469 ;
     RECT  82.908 39.659 82.926 40.469 ;
     RECT  1.404 40.109 1.422 40.493 ;
     RECT  10.872 40.433 15.066 40.559 ;
     RECT  45.576 40.469 45.897 40.559 ;
     RECT  0.504 40.301 0.522 40.589 ;
     RECT  77.22 39.659 82.17 40.667 ;
     RECT  74.664 39.901 75.69 40.739 ;
     RECT  68.868 38.975 68.886 40.865 ;
     RECT  0.144 40.699 0.342 40.877 ;
     RECT  77.796 40.667 82.17 40.901 ;
     RECT  69.768 39.047 69.786 40.981 ;
     RECT  47.736 39.083 47.754 41.135 ;
     RECT  74.664 40.739 74.934 41.135 ;
     RECT  2.304 40.325 9.306 41.179 ;
     RECT  10.08 40.981 10.098 41.179 ;
     RECT  2.304 41.179 10.098 41.215 ;
     RECT  10.872 40.559 14.418 41.215 ;
     RECT  40.215 37.319 41.058 41.215 ;
     RECT  41.976 37.319 41.994 41.215 ;
     RECT  71.424 39.341 71.73 41.405 ;
     RECT  0.144 40.877 0.162 41.485 ;
     RECT  2.304 41.215 14.418 41.521 ;
     RECT  0.108 41.485 0.162 41.549 ;
     RECT  40.215 41.215 41.994 41.639 ;
     RECT  77.796 40.901 82.098 41.675 ;
     RECT  2.304 41.521 14.634 41.791 ;
     RECT  78.015 41.675 82.098 41.819 ;
     RECT  16.596 41.791 16.614 41.899 ;
     RECT  79.02 41.819 82.098 41.909 ;
     RECT  15.66 41.791 15.822 41.917 ;
     RECT  2.304 41.791 14.742 41.945 ;
     RECT  79.02 41.909 79.758 41.945 ;
     RECT  15.552 41.917 15.822 41.989 ;
     RECT  18.615 40.055 18.897 42.043 ;
     RECT  15.516 41.989 15.822 42.061 ;
     RECT  17.676 42.061 17.694 42.151 ;
     RECT  75.672 40.739 75.69 42.151 ;
     RECT  21.132 38.741 21.834 42.179 ;
     RECT  40.215 41.639 41.67 42.179 ;
     RECT  80.568 41.909 81.954 42.179 ;
     RECT  14.832 42.061 15.822 42.187 ;
     RECT  16.596 41.899 16.722 42.187 ;
     RECT  45.615 40.559 45.897 42.187 ;
     RECT  79.02 41.945 79.722 42.215 ;
     RECT  17.676 42.151 17.766 42.223 ;
     RECT  18.615 42.043 19.134 42.223 ;
     RECT  0.108 41.549 0.126 42.331 ;
     RECT  14.832 42.187 16.722 42.421 ;
     RECT  17.676 42.223 19.134 42.421 ;
     RECT  2.304 41.945 13.95 42.457 ;
     RECT  14.832 42.421 19.134 42.565 ;
     RECT  78.015 41.819 78.297 42.565 ;
     RECT  75.672 42.151 76.986 42.601 ;
     RECT  77.976 42.565 78.297 42.601 ;
     RECT  20.916 42.259 20.934 42.629 ;
     RECT  2.268 42.457 13.95 42.667 ;
     RECT  45.432 42.187 45.897 42.667 ;
     RECT  42.48 42.151 42.498 42.691 ;
     RECT  80.568 42.179 81.414 42.691 ;
     RECT  2.232 42.667 13.95 42.715 ;
     RECT  42.336 42.691 42.498 42.719 ;
     RECT  45.432 42.667 45.99 42.719 ;
     RECT  75.672 42.601 78.297 42.727 ;
     RECT  79.02 42.215 79.542 42.727 ;
     RECT  42.336 42.719 42.354 42.749 ;
     RECT  74.664 41.135 74.79 42.755 ;
     RECT  2.232 42.715 14.058 42.827 ;
     RECT  2.268 42.827 14.058 42.871 ;
     RECT  14.832 42.565 19.53 42.871 ;
     RECT  80.496 42.691 81.414 42.871 ;
     RECT  80.424 42.871 81.414 42.961 ;
     RECT  82.332 42.691 82.35 42.961 ;
     RECT  45.576 42.719 45.897 42.989 ;
     RECT  0.108 42.331 0.558 43.085 ;
     RECT  75.672 42.727 79.542 43.141 ;
     RECT  80.424 42.961 82.35 43.141 ;
     RECT  2.268 42.871 19.746 43.277 ;
     RECT  43.596 42.727 43.614 43.295 ;
     RECT  0.144 43.085 0.558 43.469 ;
     RECT  66.132 43.339 66.15 43.501 ;
     RECT  66.132 43.501 66.438 43.529 ;
     RECT  66.168 43.529 66.438 43.565 ;
     RECT  75.672 43.141 82.35 43.565 ;
     RECT  25.344 38.507 25.434 43.601 ;
     RECT  22.068 43.411 22.086 43.609 ;
     RECT  72.468 39.341 73.854 43.609 ;
     RECT  74.772 42.755 74.79 43.609 ;
     RECT  25.416 43.601 25.434 43.637 ;
     RECT  72.468 43.609 74.79 43.637 ;
     RECT  20.664 43.141 20.682 43.681 ;
     RECT  77.076 43.565 82.35 43.681 ;
     RECT  2.304 43.277 19.746 43.799 ;
     RECT  66.168 43.565 66.186 43.799 ;
     RECT  72.468 43.637 74.322 43.799 ;
     RECT  0.144 43.469 0.27 43.807 ;
     RECT  72.468 43.799 74.25 43.835 ;
     RECT  72.468 43.835 74.07 43.901 ;
     RECT  77.076 43.681 82.71 44.069 ;
     RECT  0.108 43.807 0.27 44.221 ;
     RECT  2.304 43.799 19.458 44.339 ;
     RECT  75.672 43.565 76.338 44.383 ;
     RECT  71.568 41.405 71.73 44.539 ;
     RECT  72.468 43.901 73.854 44.539 ;
     RECT  0.108 44.221 0.558 44.621 ;
     RECT  2.304 44.339 19.35 44.681 ;
     RECT  2.304 44.681 15.282 44.753 ;
     RECT  2.304 44.753 15.246 44.779 ;
     RECT  20.664 43.681 20.718 44.851 ;
     RECT  20.664 44.851 20.79 44.915 ;
     RECT  75.672 44.383 76.482 44.959 ;
     RECT  71.568 44.539 73.854 44.971 ;
     RECT  0.108 44.621 0.162 45.005 ;
     RECT  69.516 40.981 69.786 45.031 ;
     RECT  75.636 44.959 76.482 45.031 ;
     RECT  77.256 44.069 82.71 45.031 ;
     RECT  16.128 44.681 19.35 45.157 ;
     RECT  0.144 45.005 0.162 45.197 ;
     RECT  69.516 45.031 69.966 45.265 ;
     RECT  70.776 45.229 70.794 45.265 ;
     RECT  16.128 45.157 19.386 45.301 ;
     RECT  69.516 45.265 70.794 45.301 ;
     RECT  71.568 44.971 74.178 45.301 ;
     RECT  75.636 45.031 82.71 45.301 ;
     RECT  69.516 45.301 74.178 45.391 ;
     RECT  74.916 45.301 82.71 45.391 ;
     RECT  2.268 44.779 15.246 45.427 ;
     RECT  20.7 44.915 20.79 45.463 ;
     RECT  2.196 45.427 15.246 45.547 ;
     RECT  16.128 45.301 19.926 45.547 ;
     RECT  20.7 45.463 20.826 45.571 ;
     RECT  69.516 45.391 82.71 45.599 ;
     RECT  64.98 45.229 64.998 45.661 ;
     RECT  69.516 45.599 74.754 45.769 ;
     RECT  75.636 45.599 82.71 45.773 ;
     RECT  34.308 38.399 35.097 45.805 ;
     RECT  2.016 45.547 19.926 45.835 ;
     RECT  1.476 45.835 19.926 45.841 ;
     RECT  20.7 45.571 20.898 45.841 ;
     RECT  22.068 43.609 22.194 45.841 ;
     RECT  64.98 45.661 65.034 45.841 ;
     RECT  69.048 45.769 74.754 45.841 ;
     RECT  1.476 45.841 21.258 45.931 ;
     RECT  22.068 45.841 22.842 45.931 ;
     RECT  1.476 45.931 22.842 46.027 ;
     RECT  77.22 45.773 82.71 46.039 ;
     RECT  0.108 45.805 0.126 46.075 ;
     RECT  68.976 45.841 74.754 46.109 ;
     RECT  1.404 46.027 22.842 46.337 ;
     RECT  64.98 45.841 65.106 46.381 ;
     RECT  70.632 46.109 74.754 46.381 ;
     RECT  75.636 45.773 76.482 46.381 ;
     RECT  77.22 46.039 83.142 46.411 ;
     RECT  68.976 46.109 69.786 46.459 ;
     RECT  68.868 46.459 69.786 46.535 ;
     RECT  77.22 46.411 83.178 46.541 ;
     RECT  77.22 46.541 81.954 46.571 ;
     RECT  21.672 46.337 22.842 46.607 ;
     RECT  21.672 46.607 22.194 46.643 ;
     RECT  1.404 46.337 20.898 46.679 ;
     RECT  83.088 46.541 83.178 46.679 ;
     RECT  0.108 46.075 0.162 46.699 ;
     RECT  83.124 46.679 83.178 46.699 ;
     RECT  0.108 46.699 0.198 46.741 ;
     RECT  20.412 46.679 20.898 46.769 ;
     RECT  22.068 46.643 22.194 46.769 ;
     RECT  70.632 46.381 76.482 46.769 ;
     RECT  39.276 37.133 39.294 46.777 ;
     RECT  40.215 42.179 41.058 46.777 ;
     RECT  42.336 46.741 42.354 46.781 ;
     RECT  64.98 46.381 65.142 46.877 ;
     RECT  40.215 46.777 41.562 46.912 ;
     RECT  65.052 46.877 65.142 46.913 ;
     RECT  68.976 46.535 69.786 46.913 ;
     RECT  38.124 37.391 38.142 46.921 ;
     RECT  38.88 46.777 39.294 46.921 ;
     RECT  40.215 46.912 41.598 46.921 ;
     RECT  77.76 46.571 81.954 47.039 ;
     RECT  1.404 46.679 19.566 47.12 ;
     RECT  16.524 47.12 19.566 47.147 ;
     RECT  38.124 46.921 39.294 47.147 ;
     RECT  40.176 46.921 41.598 47.147 ;
     RECT  65.124 46.913 65.142 47.183 ;
     RECT  70.668 46.769 76.482 47.183 ;
     RECT  1.404 47.12 15.714 47.275 ;
     RECT  77.796 47.039 81.954 47.275 ;
     RECT  1.152 47.275 15.714 47.309 ;
     RECT  16.56 47.147 19.566 47.309 ;
     RECT  70.668 47.183 71.766 47.309 ;
     RECT  16.56 47.309 17.298 47.345 ;
     RECT  18.072 47.309 19.53 47.345 ;
     RECT  72.576 47.183 76.482 47.345 ;
     RECT  1.152 47.309 15.102 47.381 ;
     RECT  22.14 46.769 22.194 47.389 ;
     RECT  74.664 47.345 76.482 47.425 ;
     RECT  70.668 47.309 70.686 47.515 ;
     RECT  16.632 47.345 17.298 47.579 ;
     RECT  18.216 47.345 19.53 47.579 ;
     RECT  40.176 47.147 41.382 47.579 ;
     RECT  71.568 47.309 71.766 47.579 ;
     RECT  1.152 47.381 14.958 47.615 ;
     RECT  16.668 47.579 16.686 47.615 ;
     RECT  22.14 47.389 22.734 47.695 ;
     RECT  77.796 47.275 82.098 47.695 ;
     RECT  83.124 46.699 83.214 47.695 ;
     RECT  18.216 47.579 18.897 47.741 ;
     RECT  39.276 47.147 39.294 47.821 ;
     RECT  40.176 47.579 40.554 47.821 ;
     RECT  45.615 42.989 45.897 47.821 ;
     RECT  10.188 47.615 14.958 47.849 ;
     RECT  69.408 46.913 69.786 47.857 ;
     RECT  70.524 47.515 70.686 47.857 ;
     RECT  10.836 47.849 14.85 47.885 ;
     RECT  10.944 47.885 14.85 47.891 ;
     RECT  69.408 47.857 70.686 47.893 ;
     RECT  77.796 47.695 83.214 47.965 ;
     RECT  0.108 46.741 0.27 47.981 ;
     RECT  26.172 47.731 26.37 48.001 ;
     RECT  65.052 47.929 65.07 48.029 ;
     RECT  0.144 47.981 0.27 48.043 ;
     RECT  45.615 47.821 46.098 48.091 ;
     RECT  51.015 38.165 51.297 48.091 ;
     RECT  52.884 47.899 52.902 48.091 ;
     RECT  56.415 37.229 56.697 48.091 ;
     RECT  69.156 47.893 70.686 48.091 ;
     RECT  10.944 47.891 11.106 48.119 ;
     RECT  52.884 48.091 53.226 48.119 ;
     RECT  56.304 48.091 56.697 48.128 ;
     RECT  10.944 48.119 10.962 48.155 ;
     RECT  24.015 37.895 24.297 48.163 ;
     RECT  0.144 48.043 0.342 48.173 ;
     RECT  11.916 47.891 14.85 48.191 ;
     RECT  39.276 47.821 40.554 48.199 ;
     RECT  50.904 48.091 51.297 48.221 ;
     RECT  64.98 48.091 64.998 48.221 ;
     RECT  12.6 48.191 14.85 48.227 ;
     RECT  25.956 48.001 26.37 48.235 ;
     RECT  12.6 48.227 14.238 48.263 ;
     RECT  72.576 47.345 73.926 48.271 ;
     RECT  74.664 47.425 76.626 48.271 ;
     RECT  53.208 48.119 53.226 48.299 ;
     RECT  20.88 46.769 20.898 48.361 ;
     RECT  38.124 47.147 38.142 48.361 ;
     RECT  38.952 48.199 40.554 48.361 ;
     RECT  41.364 47.579 41.382 48.361 ;
     RECT  25.956 48.235 26.802 48.389 ;
     RECT  72.54 48.271 76.626 48.389 ;
     RECT  77.616 47.965 83.214 48.397 ;
     RECT  20.88 48.361 21.042 48.425 ;
     RECT  43.056 48.235 43.074 48.433 ;
     RECT  44.424 48.271 44.442 48.433 ;
     RECT  21.024 48.425 21.042 48.461 ;
     RECT  43.056 48.433 44.442 48.469 ;
     RECT  45.504 48.091 46.098 48.469 ;
     RECT  68.976 48.091 70.686 48.469 ;
     RECT  71.568 47.579 71.73 48.469 ;
     RECT  22.14 47.695 22.914 48.505 ;
     RECT  45.504 48.469 46.746 48.505 ;
     RECT  38.124 48.361 40.554 48.523 ;
     RECT  41.364 48.361 41.598 48.523 ;
     RECT  42.732 48.469 44.478 48.523 ;
     RECT  45.504 48.505 47.466 48.523 ;
     RECT  72.54 48.389 76.41 48.541 ;
     RECT  42.732 48.523 47.466 48.569 ;
     RECT  38.124 48.523 41.598 48.619 ;
     RECT  42.732 48.569 44.838 48.619 ;
     RECT  38.124 48.619 44.838 48.631 ;
     RECT  13.215 48.263 14.238 48.659 ;
     RECT  22.14 48.505 23.058 48.661 ;
     RECT  37.764 48.631 44.838 48.667 ;
     RECT  22.14 48.661 23.238 48.695 ;
     RECT  37.548 48.667 44.838 48.695 ;
     RECT  22.968 48.695 23.238 48.703 ;
     RECT  24.015 48.163 24.966 48.703 ;
     RECT  25.956 48.389 26.766 48.703 ;
     RECT  22.968 48.703 26.766 48.704 ;
     RECT  17.1 48.667 17.118 48.767 ;
     RECT  39.564 48.695 44.838 48.767 ;
     RECT  68.976 48.469 71.73 48.775 ;
     RECT  72.468 48.541 76.41 48.775 ;
     RECT  77.544 48.397 83.214 48.775 ;
     RECT  55.26 48.703 55.278 48.811 ;
     RECT  10.8 48.631 10.818 48.839 ;
     RECT  23.328 48.704 26.766 48.845 ;
     RECT  68.976 48.775 76.41 48.859 ;
     RECT  37.548 48.695 38.682 48.901 ;
     RECT  23.328 48.845 26.694 48.929 ;
     RECT  36.144 48.433 36.162 48.929 ;
     RECT  55.26 48.811 55.494 48.929 ;
     RECT  68.904 48.859 76.41 48.929 ;
     RECT  77.508 48.775 83.214 48.937 ;
     RECT  23.328 48.929 24.786 48.965 ;
     RECT  25.524 48.929 26.694 48.965 ;
     RECT  39.564 48.767 41.31 48.965 ;
     RECT  42.156 48.767 44.838 48.965 ;
     RECT  36.936 48.901 38.682 48.973 ;
     RECT  45.615 48.569 47.466 49.081 ;
     RECT  0.144 48.173 0.27 49.099 ;
     RECT  23.328 48.965 24.297 49.199 ;
     RECT  25.956 48.965 26.154 49.199 ;
     RECT  36.504 48.973 38.682 49.199 ;
     RECT  41.256 48.965 41.31 49.199 ;
     RECT  69.66 48.929 76.41 49.199 ;
     RECT  23.688 49.199 24.297 49.235 ;
     RECT  25.956 49.199 25.974 49.235 ;
     RECT  36.504 49.199 36.666 49.235 ;
     RECT  41.256 49.199 41.274 49.271 ;
     RECT  70.704 49.199 76.41 49.315 ;
     RECT  77.364 48.937 83.214 49.315 ;
     RECT  43.704 48.965 44.838 49.351 ;
     RECT  45.615 49.081 47.61 49.351 ;
     RECT  48.42 49.279 48.438 49.441 ;
     RECT  1.152 47.615 9.306 49.469 ;
     RECT  43.704 49.351 47.61 49.469 ;
     RECT  69.66 49.199 69.966 49.469 ;
     RECT  70.704 49.315 83.214 49.469 ;
     RECT  21.312 49.351 21.33 49.477 ;
     RECT  22.14 48.695 22.194 49.477 ;
     RECT  1.152 49.469 9.198 49.505 ;
     RECT  21.312 49.477 22.194 49.505 ;
     RECT  37.764 49.199 38.682 49.505 ;
     RECT  45.396 49.469 47.61 49.577 ;
     RECT  70.704 49.469 76.41 49.577 ;
     RECT  0.144 49.099 0.342 49.579 ;
     RECT  70.704 49.577 71.73 49.613 ;
     RECT  37.836 49.505 38.682 49.621 ;
     RECT  39.564 48.965 40.497 49.621 ;
     RECT  46.908 49.577 47.61 49.621 ;
     RECT  48.42 49.441 48.546 49.621 ;
     RECT  21.492 49.505 22.194 49.649 ;
     RECT  34.308 45.805 35.298 49.649 ;
     RECT  72.54 49.577 76.41 49.739 ;
     RECT  67.215 39.515 67.497 49.747 ;
     RECT  1.404 49.505 9.198 49.775 ;
     RECT  43.704 49.469 44.478 49.775 ;
     RECT  45.396 49.577 45.897 49.775 ;
     RECT  42.156 48.965 42.858 49.783 ;
     RECT  55.26 48.929 55.278 49.783 ;
     RECT  61.815 39.119 62.097 49.819 ;
     RECT  42.156 49.783 42.894 49.847 ;
     RECT  0.144 49.579 0.414 49.853 ;
     RECT  46.908 49.621 48.546 49.855 ;
     RECT  57.42 49.783 57.438 49.855 ;
     RECT  66.744 49.747 67.497 49.883 ;
     RECT  42.516 49.847 42.894 49.891 ;
     RECT  56.415 48.128 56.697 49.891 ;
     RECT  57.42 49.855 57.474 49.891 ;
     RECT  60.3 49.315 60.318 49.891 ;
     RECT  0.144 49.853 0.234 49.949 ;
     RECT  58.716 49.819 58.734 49.981 ;
     RECT  60.3 49.891 60.498 49.981 ;
     RECT  61.272 49.819 62.097 49.981 ;
     RECT  70.704 49.613 71.694 49.981 ;
     RECT  45.432 49.775 45.897 50.009 ;
     RECT  46.908 49.855 48.762 50.009 ;
     RECT  36.504 49.235 36.522 50.045 ;
     RECT  47.16 50.009 48.762 50.045 ;
     RECT  54.72 49.783 55.278 50.045 ;
     RECT  60.3 49.981 62.097 50.045 ;
     RECT  1.404 49.775 9.018 50.081 ;
     RECT  47.16 50.045 47.178 50.081 ;
     RECT  37.836 49.621 40.497 50.117 ;
     RECT  0.144 49.949 0.162 50.141 ;
     RECT  48.168 50.045 48.762 50.153 ;
     RECT  56.415 49.891 57.474 50.153 ;
     RECT  70.38 49.981 71.694 50.153 ;
     RECT  54.72 50.045 54.882 50.161 ;
     RECT  41.58 49.981 41.598 50.251 ;
     RECT  37.836 50.117 38.142 50.279 ;
     RECT  38.988 50.117 40.497 50.279 ;
     RECT  41.508 50.251 41.598 50.279 ;
     RECT  42.516 49.891 43.506 50.279 ;
     RECT  48.168 50.153 48.69 50.279 ;
     RECT  60.336 50.045 62.097 50.279 ;
     RECT  37.836 50.279 37.854 50.315 ;
     RECT  38.988 50.279 39.15 50.315 ;
     RECT  41.508 50.279 41.526 50.315 ;
     RECT  42.516 50.279 42.75 50.315 ;
     RECT  60.336 50.279 60.354 50.315 ;
     RECT  69.156 50.251 69.174 50.315 ;
     RECT  43.488 50.279 43.506 50.351 ;
     RECT  45.615 50.009 45.897 50.359 ;
     RECT  71.208 50.153 71.694 50.387 ;
     RECT  61.164 50.279 62.097 50.395 ;
     RECT  70.38 50.153 70.398 50.395 ;
     RECT  48.168 50.279 48.186 50.423 ;
     RECT  40.215 50.279 40.497 50.431 ;
     RECT  58.644 49.981 58.806 50.431 ;
     RECT  70.236 50.395 70.398 50.431 ;
     RECT  45.615 50.359 46.134 50.459 ;
     RECT  72.54 49.739 76.302 50.459 ;
     RECT  84.132 49.195 84.15 50.459 ;
     RECT  1.404 50.081 8.19 50.549 ;
     RECT  9 50.081 9.018 50.549 ;
     RECT  38.988 50.315 39.114 50.549 ;
     RECT  58.032 50.431 58.806 50.549 ;
     RECT  69.3 50.431 69.318 50.549 ;
     RECT  70.092 50.431 70.398 50.549 ;
     RECT  77.436 49.469 83.214 50.549 ;
     RECT  5.904 50.549 8.154 50.585 ;
     RECT  38.988 50.549 39.006 50.585 ;
     RECT  44.28 49.775 44.478 50.585 ;
     RECT  58.716 50.549 58.806 50.585 ;
     RECT  71.424 50.387 71.694 50.593 ;
     RECT  72.54 50.459 73.062 50.593 ;
     RECT  54.396 50.161 54.882 50.621 ;
     RECT  7.056 50.585 8.154 50.693 ;
     RECT  61.164 50.395 62.478 50.693 ;
     RECT  58.86 50.629 58.878 50.729 ;
     RECT  18.615 47.741 18.897 50.731 ;
     RECT  22.14 49.649 22.194 50.731 ;
     RECT  54.792 50.621 54.882 50.791 ;
     RECT  1.404 50.549 5.166 50.819 ;
     RECT  44.352 50.585 44.478 50.819 ;
     RECT  45.615 50.459 46.062 50.819 ;
     RECT  42.516 50.315 42.606 50.855 ;
     RECT  54.792 50.791 54.99 50.855 ;
     RECT  17.568 50.731 18.897 50.861 ;
     RECT  73.872 50.459 76.302 50.863 ;
     RECT  40.215 50.431 41.058 50.891 ;
     RECT  54.972 50.855 54.99 50.891 ;
     RECT  21.672 50.731 22.194 50.971 ;
     RECT  61.815 50.693 62.478 50.971 ;
     RECT  21.672 50.971 22.482 50.999 ;
     RECT  73.872 50.863 76.446 51.061 ;
     RECT  42.588 50.855 42.606 51.089 ;
     RECT  61.815 50.971 62.694 51.089 ;
     RECT  70.236 50.549 70.398 51.089 ;
     RECT  70.236 51.089 70.254 51.125 ;
     RECT  73.872 51.061 76.554 51.125 ;
     RECT  74.592 51.125 76.554 51.197 ;
     RECT  71.424 50.593 73.062 51.211 ;
     RECT  44.46 50.819 44.478 51.233 ;
     RECT  5.904 50.585 6.21 51.269 ;
     RECT  61.815 51.089 62.622 51.269 ;
     RECT  71.1 51.211 73.458 51.269 ;
     RECT  74.592 51.197 76.194 51.269 ;
     RECT  22.104 50.999 22.482 51.293 ;
     RECT  17.568 50.861 17.766 51.331 ;
     RECT  17.208 51.331 17.766 51.359 ;
     RECT  71.64 51.269 73.458 51.359 ;
     RECT  6.192 51.269 6.21 51.367 ;
     RECT  7.056 50.693 8.097 51.367 ;
     RECT  1.404 50.819 4.842 51.395 ;
     RECT  6.192 51.367 8.097 51.395 ;
     RECT  59.148 50.899 59.166 51.395 ;
     RECT  6.192 51.395 6.822 51.539 ;
     RECT  77.544 50.549 83.214 51.539 ;
     RECT  6.192 51.539 6.21 51.629 ;
     RECT  17.208 51.359 17.514 51.629 ;
     RECT  71.676 51.359 73.458 51.629 ;
     RECT  82.908 51.539 83.214 51.629 ;
     RECT  74.592 51.269 75.51 51.665 ;
     RECT  71.712 51.629 71.73 51.701 ;
     RECT  74.592 51.665 74.61 51.701 ;
     RECT  42.66 51.241 42.678 51.737 ;
     RECT  2.415 51.395 4.842 51.899 ;
     RECT  17.496 51.629 17.514 51.899 ;
     RECT  82.908 51.629 83.178 51.899 ;
     RECT  4.284 51.899 4.302 52.169 ;
     RECT  77.544 51.539 81.954 52.169 ;
     RECT  82.908 51.899 83.142 52.169 ;
     RECT  82.908 52.169 82.926 52.349 ;
     RECT  2.415 51.899 3.51 52.439 ;
     RECT  1.404 51.395 1.422 52.475 ;
     RECT  77.796 52.169 81.954 52.709 ;
     RECT  78.015 52.709 81.954 52.745 ;
     RECT  79.056 52.745 81.954 52.889 ;
     RECT  2.415 52.439 2.898 53.249 ;
     RECT  2.415 53.249 2.697 53.323 ;
     RECT  0.54 52.717 0.558 53.453 ;
     RECT  79.236 52.889 81.954 53.519 ;
     RECT  2.304 53.323 2.697 53.555 ;
     RECT  61.815 51.269 62.097 54.031 ;
     RECT  79.236 53.519 81.846 54.059 ;
     RECT  64.044 53.995 64.062 54.095 ;
     RECT  61.815 54.031 62.802 54.125 ;
     RECT  79.236 54.059 81.81 54.329 ;
     RECT  79.236 54.329 79.254 54.401 ;
     RECT  80.1 54.329 81.738 54.599 ;
     RECT  22.14 51.293 22.194 54.643 ;
     RECT  22.068 54.643 22.194 54.743 ;
     RECT  80.1 54.599 81.522 54.869 ;
     RECT  75.492 51.665 75.51 55.049 ;
     RECT  80.1 54.869 81.27 55.139 ;
     RECT  22.14 54.743 22.194 57.499 ;
     RECT  22.068 57.499 22.194 57.541 ;
     RECT  22.968 57.499 22.986 57.541 ;
     RECT  22.068 57.541 22.986 57.569 ;
     RECT  22.14 57.569 22.986 57.839 ;
     RECT  22.14 57.839 22.806 57.875 ;
     RECT  22.176 57.875 22.806 57.965 ;
     RECT  22.176 57.965 22.194 57.983 ;
     RECT  56.415 50.153 56.697 58.699 ;
     RECT  55.908 58.699 56.697 58.919 ;
     RECT  55.584 58.927 55.602 58.973 ;
     RECT  49.536 63.259 49.554 63.779 ;
     RECT  47.88 63.787 47.898 63.824 ;
     RECT  41.58 68.395 41.598 68.635 ;
     RECT  41.292 68.635 41.598 68.639 ;
     RECT  34.815 49.649 35.298 68.791 ;
     RECT  41.292 68.639 41.31 68.813 ;
     RECT  37.044 68.875 37.062 68.915 ;
     RECT  36.504 68.923 36.522 68.953 ;
     RECT  36.252 68.953 36.522 68.981 ;
     RECT  36.252 68.981 36.486 69.025 ;
     RECT  36.18 69.025 36.486 69.061 ;
     RECT  34.2 68.791 35.298 69.331 ;
     RECT  36.072 69.061 36.486 69.331 ;
     RECT  34.2 69.331 36.486 69.601 ;
     RECT  33.732 69.601 36.486 69.829 ;
     RECT  33.444 69.829 36.486 69.871 ;
     RECT  33.048 69.871 36.486 69.883 ;
     RECT  33.048 69.883 36.594 69.997 ;
     RECT  33.048 69.997 36.738 70.024 ;
     RECT  33.048 70.024 36.882 70.069 ;
     RECT  33.048 70.069 37.566 70.109 ;
     RECT  33.048 70.109 37.494 70.339 ;
     RECT  32.976 70.339 37.494 70.673 ;
     RECT  2.415 53.555 2.697 71.027 ;
     RECT  7.815 51.395 8.097 71.027 ;
     RECT  13.215 48.659 13.497 71.027 ;
     RECT  18.615 50.861 18.897 71.027 ;
     RECT  24.015 49.235 24.297 71.027 ;
     RECT  29.415 37.085 29.697 71.027 ;
     RECT  40.215 50.891 40.497 71.027 ;
     RECT  45.615 50.819 45.897 71.027 ;
     RECT  51.015 48.221 51.297 71.027 ;
     RECT  56.415 58.919 56.697 71.027 ;
     RECT  61.815 54.125 62.097 71.027 ;
     RECT  67.215 49.883 67.497 71.027 ;
     RECT  72.615 51.629 72.897 71.027 ;
     RECT  78.015 52.745 78.297 71.027 ;
     RECT  32.976 70.673 37.278 71.069 ;
     RECT  32.976 71.069 36.738 71.117 ;
     RECT  34.092 71.117 36.738 71.165 ;
     RECT  32.976 71.117 32.994 71.213 ;
     RECT  36.54 71.165 36.738 71.213 ;
     RECT  34.092 71.165 35.37 71.261 ;
     RECT  36.72 71.213 36.738 71.261 ;
     RECT  2.415 71.027 2.505 71.297 ;
     RECT  7.815 71.027 7.905 71.297 ;
     RECT  13.215 71.027 13.305 71.297 ;
     RECT  18.615 71.027 18.705 71.297 ;
     RECT  24.015 71.027 24.105 71.297 ;
     RECT  29.415 71.027 29.505 71.297 ;
     RECT  40.215 71.027 40.305 71.297 ;
     RECT  45.615 71.027 45.705 71.297 ;
     RECT  51.015 71.027 51.105 71.297 ;
     RECT  56.415 71.027 56.505 71.297 ;
     RECT  61.815 71.027 61.905 71.297 ;
     RECT  67.215 71.027 67.305 71.297 ;
     RECT  72.615 71.027 72.705 71.297 ;
     RECT  78.015 71.027 78.105 71.297 ;
     RECT  34.776 71.261 35.334 71.453 ;
     RECT  36.324 72.859 36.342 73.037 ;
     RECT  35.316 71.453 35.334 73.099 ;
     RECT  35.208 73.099 35.334 73.229 ;
     RECT  35.208 73.229 35.226 73.325 ;
    LAYER M4 ;
     RECT  0.06 15.888 0.137 50.376 ;
     RECT  0.137 15.984 0.173 50.376 ;
     RECT  0.173 15.984 0.569 34.152 ;
     RECT  0.173 35.184 0.569 50.376 ;
     RECT  0.06 53.328 0.569 53.448 ;
     RECT  0.569 16.56 2.408 34.152 ;
     RECT  0.569 35.376 2.408 50.376 ;
     RECT  0.569 53.328 2.408 53.352 ;
     RECT  2.408 2.148 2.512 71.292 ;
     RECT  2.512 2.418 2.704 71.022 ;
     RECT  2.704 17.904 2.765 18.264 ;
     RECT  2.765 18 2.837 18.264 ;
     RECT  2.704 46.08 2.837 50.376 ;
     RECT  2.704 20.112 2.873 44.808 ;
     RECT  2.873 21.456 2.981 44.808 ;
     RECT  2.981 21.456 3.017 23.448 ;
     RECT  2.704 16.848 3.089 16.872 ;
     RECT  2.873 20.112 3.089 20.136 ;
     RECT  3.017 21.456 3.089 22.392 ;
     RECT  3.017 23.376 3.089 23.448 ;
     RECT  2.837 46.08 3.341 49.8 ;
     RECT  2.981 24.432 3.733 44.808 ;
     RECT  3.733 24.432 3.769 44.904 ;
     RECT  3.341 46.08 3.769 48.84 ;
     RECT  2.837 18.24 3.877 18.264 ;
     RECT  3.769 24.432 3.881 48.84 ;
     RECT  3.089 23.424 3.949 23.448 ;
     RECT  3.881 24.432 3.949 47.496 ;
     RECT  3.949 23.424 4.061 47.496 ;
     RECT  3.089 21.6 4.093 22.392 ;
     RECT  3.877 17.472 4.201 18.264 ;
     RECT  3.877 15.84 4.417 15.864 ;
     RECT  4.061 24.096 4.421 47.496 ;
     RECT  4.421 24.096 4.457 45.72 ;
     RECT  3.881 48.48 4.489 48.84 ;
     RECT  4.093 21.6 4.493 22.872 ;
     RECT  4.457 40.56 4.493 45.72 ;
     RECT  4.417 15.84 4.525 16.344 ;
     RECT  4.201 17.472 4.525 18.792 ;
     RECT  4.493 45.696 4.529 45.72 ;
     RECT  4.493 40.56 4.565 44.664 ;
     RECT  4.489 48.48 4.601 49.032 ;
     RECT  4.525 15.84 4.781 18.792 ;
     RECT  4.457 24.096 4.781 39.336 ;
     RECT  4.781 24.096 4.817 29.4 ;
     RECT  4.421 46.704 4.921 47.496 ;
     RECT  4.781 30.432 4.925 39.336 ;
     RECT  4.844 15.312 4.931 15.336 ;
     RECT  4.925 30.432 4.961 32.568 ;
     RECT  4.493 22.656 5.029 22.872 ;
     RECT  4.961 31.392 5.105 32.568 ;
     RECT  4.781 16.32 5.137 18.792 ;
     RECT  4.817 25.92 5.141 29.4 ;
     RECT  4.565 40.56 5.171 43.416 ;
     RECT  5.141 27.168 5.177 29.4 ;
     RECT  4.493 21.6 5.281 21.624 ;
     RECT  5.105 31.536 5.321 32.568 ;
     RECT  5.029 22.656 5.357 23.016 ;
     RECT  4.921 46.704 5.389 48.264 ;
     RECT  5.171 40.848 5.429 43.416 ;
     RECT  5.281 21.36 5.461 21.624 ;
     RECT  5.321 31.536 5.465 32.184 ;
     RECT  4.565 44.64 5.533 44.664 ;
     RECT  5.429 40.848 5.537 43.224 ;
     RECT  5.389 46.032 5.569 48.264 ;
     RECT  5.137 16.32 5.609 19.416 ;
     RECT  5.569 45.744 5.677 48.264 ;
     RECT  5.533 44.256 5.713 44.664 ;
     RECT  5.677 45.744 5.713 48.84 ;
     RECT  4.597 50.832 5.713 50.856 ;
     RECT  5.357 22.752 5.717 23.016 ;
     RECT  5.717 22.752 5.725 22.872 ;
     RECT  5.713 44.256 5.747 48.84 ;
     RECT  4.925 33.6 5.753 39.336 ;
     RECT  5.747 44.4 5.785 48.84 ;
     RECT  5.609 19.248 5.789 19.416 ;
     RECT  5.785 44.4 5.821 49.032 ;
     RECT  5.713 50.16 5.821 50.856 ;
     RECT  5.609 16.32 5.825 17.88 ;
     RECT  5.821 44.4 6.041 50.856 ;
     RECT  6.041 44.4 6.077 45.336 ;
     RECT  6.041 46.656 6.149 50.856 ;
     RECT  5.141 25.92 6.277 26.184 ;
     RECT  5.537 40.848 6.329 42.408 ;
     RECT  6.149 46.656 6.329 50.472 ;
     RECT  5.465 31.824 6.397 32.184 ;
     RECT  5.753 33.6 6.397 38.904 ;
     RECT  6.397 31.824 6.433 38.904 ;
     RECT  4.817 24.096 6.469 24.744 ;
     RECT  6.277 25.728 6.469 26.184 ;
     RECT  6.329 46.752 6.473 50.472 ;
     RECT  5.177 27.312 6.517 29.4 ;
     RECT  6.433 30.96 6.517 38.904 ;
     RECT  6.469 24.096 6.577 26.184 ;
     RECT  5.461 21.264 6.613 21.624 ;
     RECT  6.577 24.048 6.613 26.184 ;
     RECT  6.517 27.312 6.613 38.904 ;
     RECT  6.613 24.048 6.659 38.904 ;
     RECT  6.659 28.08 6.716 38.904 ;
     RECT  6.716 28.08 6.721 39.096 ;
     RECT  6.329 40.848 6.721 41.256 ;
     RECT  5.825 16.512 6.725 17.88 ;
     RECT  5.725 22.8 6.793 22.872 ;
     RECT  6.721 28.08 6.833 41.256 ;
     RECT  6.613 21.264 7.052 21.672 ;
     RECT  6.793 22.704 7.052 22.872 ;
     RECT  6.077 44.448 7.093 45.336 ;
     RECT  7.093 44.4 7.261 45.336 ;
     RECT  7.052 21.264 7.388 22.872 ;
     RECT  6.725 16.848 7.405 17.88 ;
     RECT  5.789 19.248 7.405 19.368 ;
     RECT  6.659 24.048 7.405 26.664 ;
     RECT  6.833 28.464 7.429 41.256 ;
     RECT  6.329 42.384 7.429 42.408 ;
     RECT  7.405 16.848 7.808 19.368 ;
     RECT  7.388 20.544 7.808 22.872 ;
     RECT  7.405 23.904 7.808 26.664 ;
     RECT  7.429 28.464 7.808 42.408 ;
     RECT  7.261 43.824 7.808 45.336 ;
     RECT  6.473 46.752 7.808 47.448 ;
     RECT  6.473 48.816 7.808 50.472 ;
     RECT  7.808 2.148 7.912 71.292 ;
     RECT  7.912 2.418 8.104 71.022 ;
     RECT  8.104 24.432 8.129 24.696 ;
     RECT  8.104 28.368 8.165 32.328 ;
     RECT  8.104 48.384 8.165 48.408 ;
     RECT  8.104 16.656 8.243 19.272 ;
     RECT  8.243 16.656 8.339 17.112 ;
     RECT  8.243 18.192 8.339 19.272 ;
     RECT  8.339 16.656 8.381 16.872 ;
     RECT  8.104 42.576 8.381 45 ;
     RECT  8.165 28.368 8.579 32.04 ;
     RECT  8.579 30 8.62 32.04 ;
     RECT  8.104 41.184 8.813 41.592 ;
     RECT  8.579 28.368 8.849 28.824 ;
     RECT  8.129 24.432 8.885 24.456 ;
     RECT  8.104 33.6 8.921 39.096 ;
     RECT  8.104 21.12 9.245 21.528 ;
     RECT  8.921 33.6 9.353 38.184 ;
     RECT  9.245 21.12 9.497 21.144 ;
     RECT  8.381 43.344 9.565 43.368 ;
     RECT  8.381 44.4 9.683 45 ;
     RECT  9.313 25.632 9.713 25.656 ;
     RECT  9.629 47.328 9.713 47.352 ;
     RECT  9.353 33.6 9.925 37.896 ;
     RECT  9.133 26.976 9.961 27 ;
     RECT  9.565 42.912 10.001 43.368 ;
     RECT  9.961 46.128 10.105 46.152 ;
     RECT  8.849 28.368 10.141 28.44 ;
     RECT  9.961 26.88 10.213 27 ;
     RECT  10.105 46.128 10.289 46.584 ;
     RECT  8.62 30.624 10.357 32.04 ;
     RECT  9.925 33.072 10.357 37.896 ;
     RECT  10.357 30.624 10.405 37.896 ;
     RECT  10.405 30.624 10.433 38.232 ;
     RECT  10.433 33.6 10.501 38.232 ;
     RECT  10.001 42.912 10.717 43.032 ;
     RECT  10.433 30.624 10.825 32.472 ;
     RECT  9.683 44.4 10.825 44.472 ;
     RECT  10.141 28.368 10.837 28.488 ;
     RECT  10.825 29.664 10.837 32.472 ;
     RECT  10.213 26.88 10.861 27.384 ;
     RECT  10.501 33.6 10.861 38.424 ;
     RECT  10.501 39.456 10.861 39.48 ;
     RECT  10.861 26.544 11.077 27.384 ;
     RECT  10.837 28.368 11.077 32.472 ;
     RECT  10.861 33.6 11.081 39.48 ;
     RECT  8.339 18.48 11.123 18.504 ;
     RECT  10.289 46.512 11.257 46.584 ;
     RECT  10.213 47.856 11.257 47.88 ;
     RECT  8.381 16.848 11.363 16.872 ;
     RECT  10.825 44.064 11.365 44.472 ;
     RECT  11.257 46.512 11.365 47.88 ;
     RECT  11.077 26.544 11.441 32.472 ;
     RECT  11.365 44.064 11.449 47.88 ;
     RECT  10.717 42.72 11.545 43.032 ;
     RECT  11.449 44.064 11.545 44.76 ;
     RECT  11.545 42.72 11.617 44.76 ;
     RECT  11.441 26.544 11.651 32.424 ;
     RECT  11.449 46.224 11.665 47.88 ;
     RECT  11.651 27.84 11.729 32.424 ;
     RECT  8.813 41.184 11.749 41.208 ;
     RECT  11.617 42.192 11.749 44.76 ;
     RECT  11.729 27.84 11.795 30.936 ;
     RECT  11.729 31.92 11.843 32.424 ;
     RECT  11.749 41.184 11.869 44.76 ;
     RECT  11.651 26.544 11.977 26.76 ;
     RECT  11.795 27.84 12.017 28.968 ;
     RECT  11.795 30.192 12.017 30.936 ;
     RECT  12.017 28.416 12.053 28.968 ;
     RECT  12.053 28.416 12.197 28.776 ;
     RECT  11.081 33.6 12.229 37.128 ;
     RECT  11.081 38.16 12.229 39.48 ;
     RECT  11.869 40.464 12.229 44.76 ;
     RECT  11.665 46.224 13.201 46.536 ;
     RECT  8.104 22.752 13.208 22.776 ;
     RECT  11.977 26.352 13.208 26.76 ;
     RECT  12.197 28.464 13.208 28.776 ;
     RECT  12.017 30.384 13.208 30.936 ;
     RECT  11.843 31.92 13.208 32.04 ;
     RECT  12.229 33.6 13.208 44.76 ;
     RECT  13.201 46.224 13.208 46.824 ;
     RECT  11.665 47.856 13.208 47.88 ;
     RECT  13.045 70.272 13.208 70.296 ;
     RECT  13.208 2.148 13.312 71.292 ;
     RECT  13.312 2.418 13.504 71.022 ;
     RECT  13.504 46.08 13.619 46.824 ;
     RECT  13.504 26.352 14.497 27.336 ;
     RECT  13.619 46.08 14.573 46.536 ;
     RECT  14.573 46.08 14.605 46.248 ;
     RECT  14.497 26.352 14.821 27.96 ;
     RECT  13.504 29.616 14.821 30.408 ;
     RECT  13.504 43.92 14.821 43.992 ;
     RECT  14.605 45.984 14.821 46.248 ;
     RECT  14.821 43.92 14.861 44.088 ;
     RECT  13.504 47.856 14.867 47.88 ;
     RECT  13.504 31.92 14.933 32.04 ;
     RECT  13.504 41.184 15.077 42.744 ;
     RECT  14.933 32.016 15.145 32.04 ;
     RECT  14.861 43.968 15.145 44.088 ;
     RECT  14.821 45.888 15.541 46.248 ;
     RECT  14.821 26.352 15.577 30.408 ;
     RECT  15.145 43.968 15.577 44.424 ;
     RECT  15.541 45.888 15.649 46.776 ;
     RECT  15.577 43.968 15.721 44.472 ;
     RECT  13.504 33.6 15.971 38.808 ;
     RECT  15.577 26.352 15.973 30.84 ;
     RECT  15.145 32.016 15.973 32.472 ;
     RECT  15.973 26.352 16.009 32.472 ;
     RECT  15.971 33.6 16.009 38.472 ;
     RECT  16.009 26.352 16.057 38.472 ;
     RECT  16.057 31.824 16.067 38.472 ;
     RECT  15.077 41.184 16.081 42.216 ;
     RECT  15.649 45.552 16.081 46.776 ;
     RECT  16.067 33.072 16.093 38.472 ;
     RECT  15.721 43.968 16.189 44.52 ;
     RECT  16.081 45.552 16.189 47.112 ;
     RECT  16.189 43.968 16.301 47.112 ;
     RECT  16.057 26.352 16.373 30.408 ;
     RECT  16.373 26.352 16.625 30.264 ;
     RECT  16.625 30.24 16.841 30.264 ;
     RECT  16.625 26.352 16.913 28.92 ;
     RECT  16.301 44.064 17.125 47.112 ;
     RECT  16.081 41.184 17.228 42.6 ;
     RECT  16.913 28.464 17.453 28.92 ;
     RECT  17.413 51.6 17.525 51.624 ;
     RECT  17.125 44.064 18.181 47.64 ;
     RECT  17.228 41.184 18.205 42.744 ;
     RECT  17.453 28.896 18.529 28.92 ;
     RECT  16.913 26.352 18.565 27.336 ;
     RECT  13.504 22.752 18.608 22.776 ;
     RECT  18.565 26.304 18.608 27.336 ;
     RECT  18.529 28.8 18.608 28.92 ;
     RECT  16.067 32.016 18.608 32.04 ;
     RECT  16.093 33.6 18.608 38.472 ;
     RECT  18.205 41.184 18.608 43.032 ;
     RECT  18.181 44.064 18.608 47.736 ;
     RECT  17.557 50.736 18.608 50.856 ;
     RECT  13.504 70.272 18.608 70.296 ;
     RECT  18.608 2.148 18.712 71.292 ;
     RECT  18.712 2.418 18.904 71.022 ;
     RECT  18.904 26.304 18.965 27.192 ;
     RECT  18.904 21.984 19.037 22.776 ;
     RECT  18.904 41.184 19.073 44.088 ;
     RECT  19.073 41.184 19.145 43.368 ;
     RECT  18.904 46.224 19.217 46.872 ;
     RECT  18.904 33.6 19.469 39.192 ;
     RECT  19.145 43.008 19.613 43.368 ;
     RECT  19.613 43.344 19.757 43.368 ;
     RECT  19.469 33.6 19.826 38.472 ;
     RECT  18.965 26.352 19.957 27.192 ;
     RECT  19.957 26.352 20.005 27.816 ;
     RECT  20.005 26.208 20.044 27.816 ;
     RECT  20.044 26.208 20.435 27.336 ;
     RECT  19.217 46.224 20.657 46.44 ;
     RECT  18.904 29.232 20.869 29.256 ;
     RECT  20.869 29.232 20.909 29.64 ;
     RECT  20.435 26.256 21.085 27.336 ;
     RECT  20.657 46.224 21.349 46.248 ;
     RECT  18.904 50.832 21.349 50.856 ;
     RECT  21.349 46.128 21.395 46.248 ;
     RECT  21.395 46.128 21.436 46.152 ;
     RECT  19.037 22.752 21.553 22.776 ;
     RECT  19.145 41.184 21.593 41.208 ;
     RECT  21.349 50.736 21.701 50.856 ;
     RECT  21.085 26.256 22.021 28.248 ;
     RECT  20.909 29.616 22.021 29.64 ;
     RECT  21.553 22.656 22.025 22.776 ;
     RECT  21.701 50.832 22.076 50.856 ;
     RECT  22.057 57.504 22.117 57.528 ;
     RECT  22.076 50.832 22.133 51.288 ;
     RECT  18.904 70.272 22.453 70.296 ;
     RECT  22.133 51.264 22.499 51.288 ;
     RECT  22.117 57.504 22.777 57.576 ;
     RECT  22.777 57.504 22.997 57.96 ;
     RECT  22.025 22.752 24.008 22.776 ;
     RECT  22.021 26.256 24.008 29.64 ;
     RECT  18.904 32.016 24.008 32.04 ;
     RECT  19.826 33.6 24.008 38.424 ;
     RECT  22.957 48.672 24.008 48.696 ;
     RECT  22.997 57.936 24.008 57.96 ;
     RECT  22.453 69.744 24.008 70.296 ;
     RECT  24.008 2.148 24.112 71.292 ;
     RECT  24.112 2.418 24.304 71.022 ;
     RECT  24.304 26.352 24.761 26.568 ;
     RECT  24.304 27.936 25.265 30.216 ;
     RECT  24.304 32.016 25.621 32.04 ;
     RECT  25.265 27.936 25.625 28.776 ;
     RECT  25.265 30.192 25.667 30.216 ;
     RECT  24.304 33.6 25.697 38.424 ;
     RECT  25.621 31.68 26.348 32.04 ;
     RECT  25.697 33.6 26.348 38.136 ;
     RECT  26.348 31.68 26.435 38.136 ;
     RECT  25.625 27.936 26.629 28.488 ;
     RECT  26.413 24 26.669 24.024 ;
     RECT  26.629 27.888 26.669 28.488 ;
     RECT  26.341 48.816 26.777 48.84 ;
     RECT  26.435 31.68 27.173 32.04 ;
     RECT  26.669 27.888 27.605 28.008 ;
     RECT  27.605 27.936 27.853 28.008 ;
     RECT  27.853 27.936 28.217 28.44 ;
     RECT  24.304 22.752 29.408 22.776 ;
     RECT  24.761 26.352 29.408 26.424 ;
     RECT  28.217 27.936 29.408 27.96 ;
     RECT  27.173 32.016 29.408 32.04 ;
     RECT  26.435 33.6 29.408 38.136 ;
     RECT  24.304 57.936 29.408 57.96 ;
     RECT  24.304 69.744 29.408 70.296 ;
     RECT  29.408 2.148 29.512 71.292 ;
     RECT  29.512 2.418 29.704 71.022 ;
     RECT  29.704 33.6 30.659 37.992 ;
     RECT  29.704 26.352 30.805 26.424 ;
     RECT  30.805 23.904 30.841 24.072 ;
     RECT  30.841 23.904 31.061 24.312 ;
     RECT  31.061 23.904 31.097 24.168 ;
     RECT  30.805 26.352 31.477 26.52 ;
     RECT  29.704 27.936 31.477 27.96 ;
     RECT  31.477 26.352 31.523 27.96 ;
     RECT  30.659 33.6 31.529 37.464 ;
     RECT  29.704 22.752 31.741 22.776 ;
     RECT  31.523 26.352 31.781 27.768 ;
     RECT  31.529 33.6 32.677 37.416 ;
     RECT  32.209 24.48 32.749 24.504 ;
     RECT  31.781 26.352 32.857 26.52 ;
     RECT  31.781 27.744 32.857 27.768 ;
     RECT  31.741 22.752 32.867 23.496 ;
     RECT  32.749 24.48 32.867 24.552 ;
     RECT  32.857 26.352 32.897 27.768 ;
     RECT  32.867 22.8 33.361 23.496 ;
     RECT  32.867 24.48 33.361 24.504 ;
     RECT  33.361 22.8 33.388 24.504 ;
     RECT  32.677 33.6 33.437 37.608 ;
     RECT  32.821 20.352 33.452 20.376 ;
     RECT  33.452 20.352 33.539 20.76 ;
     RECT  33.388 22.8 33.553 24.36 ;
     RECT  29.704 69.744 33.613 70.296 ;
     RECT  33.613 69.744 34.081 71.112 ;
     RECT  34.021 68.688 34.309 68.712 ;
     RECT  34.081 69.744 34.309 71.256 ;
     RECT  32.897 26.352 34.441 27.336 ;
     RECT  33.437 33.6 34.441 37.416 ;
     RECT  33.553 22.944 34.657 24.36 ;
     RECT  34.309 68.688 34.765 71.256 ;
     RECT  33.539 20.352 34.801 20.376 ;
     RECT  34.765 17.712 34.808 17.736 ;
     RECT  34.801 20.352 34.808 21.24 ;
     RECT  34.657 22.944 34.808 24.648 ;
     RECT  34.441 26.352 34.808 28.296 ;
     RECT  29.704 32.016 34.808 32.04 ;
     RECT  34.441 33.6 34.808 37.608 ;
     RECT  29.704 57.936 34.808 57.96 ;
     RECT  34.765 68.688 34.808 71.448 ;
     RECT  34.808 2.148 34.849 71.448 ;
     RECT  34.849 2.148 34.912 71.292 ;
     RECT  34.885 73.056 34.981 73.08 ;
     RECT  34.981 73.008 35.077 73.08 ;
     RECT  34.912 2.418 35.104 71.256 ;
     RECT  35.077 73.008 35.153 73.176 ;
     RECT  35.104 20.352 35.219 21.24 ;
     RECT  35.153 73.008 35.237 73.32 ;
     RECT  35.104 23.28 35.273 24.312 ;
     RECT  35.273 23.664 35.309 24.312 ;
     RECT  35.237 73.008 35.345 73.224 ;
     RECT  35.309 23.664 35.381 24.168 ;
     RECT  35.345 73.008 35.459 73.176 ;
     RECT  35.104 17.616 35.741 17.64 ;
     RECT  35.104 25.584 35.993 29.256 ;
     RECT  35.993 25.584 36.065 28.68 ;
     RECT  35.459 73.008 36.277 73.032 ;
     RECT  35.381 23.664 36.281 23.976 ;
     RECT  35.104 30.816 36.281 30.84 ;
     RECT  36.277 72.864 36.325 73.032 ;
     RECT  36.281 23.664 36.353 23.688 ;
     RECT  36.325 72.768 36.397 73.032 ;
     RECT  36.397 72.768 36.467 72.792 ;
     RECT  35.104 68.688 36.533 71.256 ;
     RECT  36.533 69.888 36.605 71.256 ;
     RECT  36.605 70.032 36.749 71.256 ;
     RECT  36.749 70.032 36.893 70.92 ;
     RECT  35.104 32.016 36.925 32.04 ;
     RECT  36.065 26.352 36.965 28.68 ;
     RECT  36.601 22.08 36.997 22.104 ;
     RECT  35.104 33.6 37.001 37.608 ;
     RECT  36.533 68.688 37.073 68.904 ;
     RECT  36.965 26.352 37.141 28.296 ;
     RECT  36.893 70.08 37.289 70.92 ;
     RECT  37.289 70.08 37.571 70.728 ;
     RECT  36.997 21.504 37.609 22.104 ;
     RECT  37.571 70.08 37.612 70.104 ;
     RECT  36.925 31.872 37.621 32.04 ;
     RECT  37.001 33.6 37.621 37.416 ;
     RECT  37.141 25.584 37.649 28.296 ;
     RECT  37.609 21.504 37.793 22.296 ;
     RECT  36.925 48.912 37.82 48.936 ;
     RECT  37.82 48.912 37.861 49.752 ;
     RECT  35.219 20.352 37.868 20.376 ;
     RECT  37.793 21.504 37.868 22.2 ;
     RECT  37.861 48.384 37.907 49.752 ;
     RECT  37.868 20.352 37.955 22.2 ;
     RECT  37.649 25.584 37.964 27.432 ;
     RECT  37.964 25.056 38.051 27.432 ;
     RECT  37.609 23.616 38.113 23.64 ;
     RECT  37.621 31.872 38.125 37.416 ;
     RECT  38.125 32.736 38.189 37.416 ;
     RECT  37.321 29.616 38.725 29.64 ;
     RECT  38.051 25.68 38.797 27.432 ;
     RECT  37.907 48.384 38.801 48.408 ;
     RECT  37.955 21.408 38.869 22.2 ;
     RECT  38.113 23.616 38.869 24.552 ;
     RECT  37.955 20.352 39.02 20.376 ;
     RECT  39.02 19.68 39.049 20.376 ;
     RECT  38.869 21.408 39.049 24.552 ;
     RECT  39.049 19.68 39.085 24.552 ;
     RECT  38.797 25.68 39.085 27.912 ;
     RECT  39.085 19.68 39.229 28.248 ;
     RECT  38.725 29.616 39.229 30.408 ;
     RECT  39.229 19.68 39.445 30.408 ;
     RECT  39.445 19.392 39.829 30.408 ;
     RECT  39.596 31.536 39.829 31.56 ;
     RECT  36.889 17.088 40.208 17.112 ;
     RECT  39.445 18.192 40.208 18.216 ;
     RECT  39.829 19.392 40.208 31.56 ;
     RECT  38.189 33.6 40.208 37.416 ;
     RECT  40.069 40.656 40.208 40.68 ;
     RECT  38.053 44.64 40.208 44.664 ;
     RECT  39.973 46.704 40.208 46.92 ;
     RECT  39.085 48.336 40.208 48.36 ;
     RECT  39.925 50.208 40.208 50.232 ;
     RECT  35.104 57.936 40.208 57.96 ;
     RECT  37.073 68.688 40.208 68.712 ;
     RECT  40.208 2.148 40.312 71.292 ;
     RECT  40.312 2.418 40.504 71.022 ;
     RECT  40.504 24.144 40.889 28.68 ;
     RECT  40.889 24.144 40.925 27.432 ;
     RECT  40.504 40.656 40.925 41.592 ;
     RECT  40.925 24.24 40.997 27.432 ;
     RECT  40.504 17.088 41.075 22.584 ;
     RECT  41.075 17.664 41.116 22.584 ;
     RECT  40.997 24.432 41.285 27.432 ;
     RECT  40.504 68.64 41.321 68.808 ;
     RECT  40.504 57.936 41.363 57.96 ;
     RECT  40.925 41.568 41.365 41.592 ;
     RECT  40.889 28.464 41.429 28.68 ;
     RECT  40.504 46.896 41.429 46.92 ;
     RECT  41.321 68.64 41.525 68.664 ;
     RECT  41.468 50.256 41.555 50.28 ;
     RECT  41.429 28.512 41.564 28.68 ;
     RECT  40.504 29.76 41.564 30.696 ;
     RECT  41.564 28.512 41.605 30.696 ;
     RECT  41.525 68.4 41.609 68.664 ;
     RECT  41.605 28.512 41.651 30.84 ;
     RECT  41.609 68.64 41.939 68.664 ;
     RECT  41.651 30.576 41.969 30.84 ;
     RECT  41.116 19.248 42.035 22.584 ;
     RECT  42.035 19.248 42.077 19.368 ;
     RECT  40.504 48.096 42.145 49.224 ;
     RECT  42.077 19.344 42.179 19.368 ;
     RECT  42.284 46.752 42.371 46.776 ;
     RECT  42.325 42.72 42.409 42.744 ;
     RECT  41.969 30.576 42.509 30.792 ;
     RECT  41.116 17.664 42.541 18.024 ;
     RECT  41.285 24.432 42.613 27.336 ;
     RECT  41.651 28.512 42.617 28.968 ;
     RECT  42.613 24.288 42.725 27.336 ;
     RECT  42.145 48.096 42.833 49.56 ;
     RECT  42.035 20.448 42.865 22.584 ;
     RECT  42.865 20.448 43.013 22.728 ;
     RECT  42.725 24.288 43.045 24.504 ;
     RECT  43.013 20.448 43.049 22.584 ;
     RECT  43.045 24.048 43.049 24.504 ;
     RECT  43.049 20.88 43.121 22.584 ;
     RECT  43.121 20.88 43.265 21.816 ;
     RECT  42.509 30.576 43.285 30.6 ;
     RECT  43.285 30.192 43.331 30.6 ;
     RECT  43.049 24.048 43.373 24.312 ;
     RECT  42.725 25.536 43.409 27.336 ;
     RECT  43.373 24.048 43.445 24.072 ;
     RECT  42.617 28.512 43.445 28.536 ;
     RECT  42.541 17.664 43.549 18.12 ;
     RECT  43.265 20.928 43.589 21.816 ;
     RECT  43.331 30.192 43.625 30.216 ;
     RECT  43.589 20.928 44.269 21.48 ;
     RECT  43.549 17.568 44.345 18.12 ;
     RECT  44.269 20.64 44.449 21.48 ;
     RECT  42.833 48.096 44.809 49.224 ;
     RECT  43.409 26.208 44.953 27.336 ;
     RECT  45.445 40.416 45.452 40.44 ;
     RECT  44.953 25.296 45.457 27.336 ;
     RECT  43.693 28.944 45.457 28.968 ;
     RECT  44.345 18.096 45.529 18.12 ;
     RECT  45.529 18.096 45.608 18.264 ;
     RECT  44.449 20.592 45.608 21.48 ;
     RECT  45.205 23.952 45.608 23.976 ;
     RECT  45.457 25.296 45.608 28.968 ;
     RECT  40.504 33.6 45.608 37.416 ;
     RECT  45.493 38.688 45.608 38.712 ;
     RECT  45.452 39.888 45.608 40.44 ;
     RECT  45.421 42.192 45.608 42.216 ;
     RECT  40.504 44.64 45.608 44.664 ;
     RECT  44.809 48.096 45.608 49.32 ;
     RECT  41.557 63.792 45.608 63.816 ;
     RECT  45.608 2.148 45.712 71.292 ;
     RECT  45.712 2.418 45.904 71.022 ;
     RECT  45.904 32.4 46.019 37.608 ;
     RECT  45.904 42.672 46.019 42.696 ;
     RECT  45.904 48.096 46.019 49.512 ;
     RECT  45.904 40.416 46.163 40.44 ;
     RECT  46.019 32.4 46.181 37.416 ;
     RECT  45.904 20.304 46.307 21.672 ;
     RECT  46.019 49.44 46.397 49.512 ;
     RECT  45.904 25.824 46.691 28.872 ;
     RECT  46.181 32.4 46.787 32.904 ;
     RECT  45.904 18.192 46.981 18.264 ;
     RECT  45.904 22.848 47.005 24.504 ;
     RECT  46.981 17.472 47.027 18.264 ;
     RECT  46.181 34.032 47.045 37.416 ;
     RECT  47.027 17.472 47.068 18.216 ;
     RECT  46.307 20.544 47.075 21.672 ;
     RECT  47.045 34.128 47.123 37.416 ;
     RECT  47.005 22.8 47.173 24.504 ;
     RECT  46.691 25.824 47.269 26.424 ;
     RECT  47.173 22.752 47.297 24.504 ;
     RECT  47.075 20.544 47.441 21.528 ;
     RECT  46.397 49.488 47.477 49.512 ;
     RECT  46.787 32.88 47.545 32.904 ;
     RECT  47.068 18.192 47.555 18.216 ;
     RECT  45.904 38.688 47.653 38.712 ;
     RECT  47.441 20.592 47.693 21.528 ;
     RECT  47.297 23.04 47.725 24.504 ;
     RECT  47.269 25.632 47.725 26.424 ;
     RECT  47.693 20.688 47.729 21.528 ;
     RECT  45.904 63.792 47.909 63.816 ;
     RECT  47.725 23.04 47.941 26.424 ;
     RECT  46.691 27.936 47.941 28.536 ;
     RECT  47.941 23.04 48.157 28.536 ;
     RECT  48.157 23.04 48.161 29.208 ;
     RECT  47.545 32.88 48.301 33 ;
     RECT  47.123 34.416 48.301 37.416 ;
     RECT  47.653 38.688 48.373 38.76 ;
     RECT  48.301 32.88 48.445 37.416 ;
     RECT  48.445 32.352 48.469 37.416 ;
     RECT  48.469 32.16 48.515 37.416 ;
     RECT  47.729 21.36 48.697 21.528 ;
     RECT  48.161 23.04 48.697 26.424 ;
     RECT  48.373 38.688 48.764 39.048 ;
     RECT  48.161 27.936 48.851 29.208 ;
     RECT  48.515 32.16 48.851 33.288 ;
     RECT  48.764 38.64 48.851 39.048 ;
     RECT  48.697 21.36 49.061 26.424 ;
     RECT  49.061 21.36 49.313 23.064 ;
     RECT  49.525 63.264 49.609 63.288 ;
     RECT  48.851 33.264 49.741 33.288 ;
     RECT  48.515 34.416 49.741 37.416 ;
     RECT  48.851 27.936 49.997 29.064 ;
     RECT  49.741 33.264 50.137 37.416 ;
     RECT  49.313 21.456 50.425 23.064 ;
     RECT  49.061 24.144 50.425 26.424 ;
     RECT  46.019 48.096 50.893 48.12 ;
     RECT  50.353 18.528 51.008 18.552 ;
     RECT  50.425 21.456 51.008 26.424 ;
     RECT  49.997 28.272 51.008 29.064 ;
     RECT  50.137 33.12 51.008 37.416 ;
     RECT  48.851 39.024 51.008 39.048 ;
     RECT  45.904 44.64 51.008 44.664 ;
     RECT  50.893 48.096 51.008 48.216 ;
     RECT  49.525 58.944 51.008 58.968 ;
     RECT  51.008 2.148 51.112 71.292 ;
     RECT  51.112 2.418 51.304 71.022 ;
     RECT  51.304 33.12 51.689 37.416 ;
     RECT  51.304 21.456 51.82 23.352 ;
     RECT  51.304 24.672 51.977 26.424 ;
     RECT  51.82 21.456 52.381 23.064 ;
     RECT  52.381 22.8 52.589 23.064 ;
     RECT  52.589 22.8 52.697 23.016 ;
     RECT  51.977 26.256 52.739 26.424 ;
     RECT  51.304 48.192 52.873 48.216 ;
     RECT  52.873 47.904 52.957 48.216 ;
     RECT  51.689 33.936 53.084 37.416 ;
     RECT  53.084 33.456 53.171 37.416 ;
     RECT  52.957 48.096 53.237 48.216 ;
     RECT  51.977 24.672 54.709 24.696 ;
     RECT  52.739 26.352 54.709 26.424 ;
     RECT  54.709 24.672 54.749 26.424 ;
     RECT  54.749 24.672 55.289 26.376 ;
     RECT  51.304 58.944 55.897 58.968 ;
     RECT  52.381 21.456 56.408 21.528 ;
     RECT  52.697 22.848 56.408 23.016 ;
     RECT  55.289 24.672 56.408 24.696 ;
     RECT  55.289 26.304 56.408 26.376 ;
     RECT  54.709 30.672 56.408 30.696 ;
     RECT  53.171 34.32 56.408 37.416 ;
     RECT  51.304 39.024 56.408 39.048 ;
     RECT  51.304 44.64 56.408 44.664 ;
     RECT  53.237 48.096 56.408 48.12 ;
     RECT  55.909 54.096 56.408 54.12 ;
     RECT  55.897 58.704 56.408 58.968 ;
     RECT  56.408 2.148 56.512 71.292 ;
     RECT  56.512 2.418 56.704 71.022 ;
     RECT  56.704 30.576 57.769 30.6 ;
     RECT  57.769 30.576 58.061 30.744 ;
     RECT  58.061 30.576 58.097 30.6 ;
     RECT  56.704 22.8 58.489 22.872 ;
     RECT  58.489 22.752 58.601 22.872 ;
     RECT  56.704 34.368 58.705 37.416 ;
     RECT  58.601 22.8 58.745 22.872 ;
     RECT  56.704 21.456 59.533 21.528 ;
     RECT  59.533 20.976 59.753 21.528 ;
     RECT  56.704 24.672 59.797 24.696 ;
     RECT  58.745 22.8 59.843 22.824 ;
     RECT  59.797 24.288 60.365 24.696 ;
     RECT  60.365 24.48 60.401 24.696 ;
     RECT  56.704 38.928 61.009 39.048 ;
     RECT  59.753 21.456 61.808 21.528 ;
     RECT  60.401 24.48 61.808 24.504 ;
     RECT  56.704 26.352 61.808 26.424 ;
     RECT  58.705 34.368 61.808 37.608 ;
     RECT  61.009 38.928 61.808 39.096 ;
     RECT  56.704 44.64 61.808 44.664 ;
     RECT  56.704 48.096 61.808 48.12 ;
     RECT  56.704 54.096 61.808 54.12 ;
     RECT  61.808 2.148 61.912 71.292 ;
     RECT  61.912 2.418 62.104 71.022 ;
     RECT  62.104 34.368 62.165 37.608 ;
     RECT  62.104 26.304 62.741 26.424 ;
     RECT  62.104 54.096 62.813 54.12 ;
     RECT  62.104 24.48 63.065 24.504 ;
     RECT  62.165 34.368 63.925 37.416 ;
     RECT  62.741 26.304 64.069 26.376 ;
     RECT  63.925 54 64.073 54.024 ;
     RECT  63.925 34.224 64.115 37.416 ;
     RECT  64.115 34.896 64.213 37.416 ;
     RECT  62.104 38.928 64.213 38.952 ;
     RECT  62.104 48.096 64.969 48.12 ;
     RECT  64.969 48.096 65.009 48.216 ;
     RECT  64.213 34.896 65.513 38.952 ;
     RECT  65.513 38.928 65.581 38.952 ;
     RECT  65.513 34.896 66.013 37.608 ;
     RECT  65.605 43.536 66.121 43.56 ;
     RECT  66.121 43.344 66.205 43.56 ;
     RECT  65.581 38.928 66.481 39.336 ;
     RECT  66.481 38.688 66.545 39.336 ;
     RECT  63.817 24.336 66.757 24.36 ;
     RECT  66.757 23.904 66.805 24.36 ;
     RECT  66.013 34.752 66.812 37.608 ;
     RECT  62.104 21.456 67.208 21.528 ;
     RECT  66.805 23.376 67.208 24.36 ;
     RECT  64.069 26.304 67.208 26.664 ;
     RECT  66.841 32.016 67.208 32.04 ;
     RECT  66.841 33.024 67.208 33.048 ;
     RECT  66.812 34.32 67.208 37.608 ;
     RECT  66.545 38.688 67.208 39.384 ;
     RECT  66.205 43.536 67.208 43.56 ;
     RECT  62.104 44.64 67.208 44.664 ;
     RECT  65.009 48.192 67.208 48.216 ;
     RECT  63.925 49.248 67.208 49.272 ;
     RECT  67.208 2.148 67.312 71.292 ;
     RECT  67.312 2.418 67.504 71.022 ;
     RECT  67.504 34.752 67.781 37.608 ;
     RECT  67.781 34.8 68.069 37.608 ;
     RECT  68.069 34.848 68.177 37.608 ;
     RECT  67.504 21.456 68.605 21.528 ;
     RECT  67.504 32.016 68.675 32.04 ;
     RECT  67.504 48.192 68.856 48.216 ;
     RECT  67.504 49.248 68.856 49.272 ;
     RECT  67.504 26.352 68.869 26.76 ;
     RECT  68.828 28.464 68.915 28.488 ;
     RECT  67.504 23.376 68.917 23.4 ;
     RECT  68.856 48.192 68.917 49.272 ;
     RECT  68.869 26.352 68.929 27.336 ;
     RECT  68.929 26.208 68.956 27.336 ;
     RECT  68.605 21.456 68.963 22.2 ;
     RECT  68.917 23.376 68.963 23.832 ;
     RECT  67.504 43.536 68.963 43.56 ;
     RECT  68.857 46.464 68.963 46.488 ;
     RECT  68.956 26.208 68.965 26.76 ;
     RECT  68.965 26.112 69.005 26.76 ;
     RECT  68.963 23.808 69.041 23.832 ;
     RECT  68.629 29.616 69.073 29.64 ;
     RECT  68.965 32.976 69.077 33 ;
     RECT  69.073 28.752 69.113 29.64 ;
     RECT  69.109 50.256 69.196 50.28 ;
     RECT  69.005 26.112 69.257 26.664 ;
     RECT  68.963 21.456 69.361 21.528 ;
     RECT  68.917 48.096 69.405 49.272 ;
     RECT  69.404 46.128 69.491 46.152 ;
     RECT  69.405 47.28 69.977 49.272 ;
     RECT  69.361 21.072 70.009 21.528 ;
     RECT  69.113 28.752 70.009 28.776 ;
     RECT  68.177 34.944 70.045 37.608 ;
     RECT  69.257 26.256 70.117 26.664 ;
     RECT  70.009 28.128 70.117 28.776 ;
     RECT  70.045 34.704 70.117 37.608 ;
     RECT  70.009 21.072 70.225 22.2 ;
     RECT  70.117 34.704 70.225 38.232 ;
     RECT  70.081 25.152 70.333 25.176 ;
     RECT  69.977 47.28 70.345 49.08 ;
     RECT  69.613 23.904 70.445 23.928 ;
     RECT  70.333 25.104 70.445 25.176 ;
     RECT  70.225 20.976 70.477 22.2 ;
     RECT  70.445 25.104 70.693 25.128 ;
     RECT  70.225 34.608 70.693 38.232 ;
     RECT  70.117 26.256 70.765 26.904 ;
     RECT  70.477 46.08 70.873 46.104 ;
     RECT  70.345 47.28 70.873 48.984 ;
     RECT  70.225 50.832 71.089 50.856 ;
     RECT  70.117 28.128 71.233 28.968 ;
     RECT  70.261 30.144 71.233 30.168 ;
     RECT  70.693 34.224 71.237 38.232 ;
     RECT  70.873 46.08 71.237 48.984 ;
     RECT  70.765 26.112 71.269 26.904 ;
     RECT  71.233 28.128 71.269 30.168 ;
     RECT  70.693 24.912 71.305 25.128 ;
     RECT  70.477 20.88 71.341 22.2 ;
     RECT  71.341 20.592 71.413 22.2 ;
     RECT  71.269 26.112 71.413 30.168 ;
     RECT  70.117 31.392 71.413 31.416 ;
     RECT  71.305 23.952 71.459 25.128 ;
     RECT  71.089 50.832 71.557 51.24 ;
     RECT  71.519 49.2 71.585 49.224 ;
     RECT  71.557 50.832 71.585 51.336 ;
     RECT  71.237 46.08 71.653 48.216 ;
     RECT  67.504 44.64 72.037 44.664 ;
     RECT  71.237 34.224 72.061 37.416 ;
     RECT  71.413 20.592 72.133 22.776 ;
     RECT  72.037 44.544 72.205 44.664 ;
     RECT  71.653 45.696 72.205 48.216 ;
     RECT  71.413 26.112 72.277 30.216 ;
     RECT  71.413 31.344 72.277 31.416 ;
     RECT  72.277 26.112 72.325 31.416 ;
     RECT  71.459 24.48 72.469 25.128 ;
     RECT  71.989 39.312 72.469 39.336 ;
     RECT  72.133 20.592 72.608 23.4 ;
     RECT  72.469 24.384 72.608 25.128 ;
     RECT  72.325 26.112 72.608 32.328 ;
     RECT  72.061 34.176 72.608 37.416 ;
     RECT  72.469 39.072 72.608 39.336 ;
     RECT  70.261 42.72 72.608 42.744 ;
     RECT  72.205 44.544 72.608 48.216 ;
     RECT  71.585 49.2 72.608 51.336 ;
     RECT  72.608 2.148 72.712 71.292 ;
     RECT  72.712 2.418 72.904 71.022 ;
     RECT  72.904 26.112 73.001 27.144 ;
     RECT  72.904 29.376 73.073 30.456 ;
     RECT  73.001 26.112 73.325 26.664 ;
     RECT  72.904 50.832 73.469 51.24 ;
     RECT  72.904 20.112 73.505 23.688 ;
     RECT  73.505 20.352 73.577 23.688 ;
     RECT  72.904 48.192 73.811 49.752 ;
     RECT  73.325 26.256 74.012 26.664 ;
     RECT  73.811 48.672 74.045 49.752 ;
     RECT  72.904 24.912 74.077 25.032 ;
     RECT  74.005 33.024 74.089 33.048 ;
     RECT  72.904 34.32 74.092 38.232 ;
     RECT  74.012 26.256 74.099 26.76 ;
     RECT  73.577 21.408 74.113 23.688 ;
     RECT  74.077 24.864 74.113 25.032 ;
     RECT  72.904 43.728 74.333 46.056 ;
     RECT  73.577 20.352 74.441 20.376 ;
     RECT  74.333 44.64 74.509 46.056 ;
     RECT  74.005 47.28 74.509 47.304 ;
     RECT  74.045 48.912 74.509 49.752 ;
     RECT  73.469 50.832 74.509 50.856 ;
     RECT  74.092 35.184 74.585 38.232 ;
     RECT  73.073 29.376 74.689 29.784 ;
     RECT  74.113 21.408 74.765 25.032 ;
     RECT  72.904 28.368 74.833 28.392 ;
     RECT  74.689 29.376 74.833 30.264 ;
     RECT  74.765 21.408 74.941 23.208 ;
     RECT  74.509 44.64 74.941 47.304 ;
     RECT  74.833 28.368 74.972 30.264 ;
     RECT  74.365 31.248 74.972 31.272 ;
     RECT  74.972 28.368 75.013 31.272 ;
     RECT  75.013 28.368 75.085 31.368 ;
     RECT  74.585 35.184 75.085 37.08 ;
     RECT  75.085 28.128 75.109 31.368 ;
     RECT  74.509 48.912 75.121 50.856 ;
     RECT  74.585 38.208 75.125 38.232 ;
     RECT  75.121 48.912 75.341 51.288 ;
     RECT  75.085 34.368 75.373 37.08 ;
     RECT  75.341 48.912 75.449 51.192 ;
     RECT  75.109 27.888 75.517 31.368 ;
     RECT  75.449 48.912 75.593 49.032 ;
     RECT  75.517 27.888 75.665 31.656 ;
     RECT  74.941 44.64 75.665 47.352 ;
     RECT  74.099 26.256 75.697 26.52 ;
     RECT  75.665 28.128 75.701 31.656 ;
     RECT  75.665 44.64 75.773 46.92 ;
     RECT  75.701 28.128 75.809 29.112 ;
     RECT  75.373 34.128 75.809 37.08 ;
     RECT  75.809 34.128 75.877 34.2 ;
     RECT  75.809 35.184 75.881 37.08 ;
     RECT  75.773 44.832 75.923 46.92 ;
     RECT  74.941 20.736 75.949 23.208 ;
     RECT  74.765 24.336 75.949 25.032 ;
     RECT  75.697 26.256 75.989 26.664 ;
     RECT  75.449 50.736 76.025 51.192 ;
     RECT  75.877 33.552 76.033 34.2 ;
     RECT  75.949 20.736 76.061 25.032 ;
     RECT  75.701 30.384 76.097 31.656 ;
     RECT  76.033 33.552 76.097 33.576 ;
     RECT  75.923 45.504 76.097 46.92 ;
     RECT  76.061 21.408 76.133 25.032 ;
     RECT  76.133 21.408 76.205 23.688 ;
     RECT  75.881 35.28 76.205 37.08 ;
     RECT  76.133 25.008 76.277 25.032 ;
     RECT  75.809 28.992 76.277 29.112 ;
     RECT  76.097 31.632 76.277 31.656 ;
     RECT  76.205 35.472 76.313 37.08 ;
     RECT  76.313 36.912 76.385 37.08 ;
     RECT  76.205 21.648 76.421 23.688 ;
     RECT  76.277 29.088 76.421 29.112 ;
     RECT  76.097 30.384 76.493 30.408 ;
     RECT  75.989 26.496 76.529 26.664 ;
     RECT  76.025 51.168 76.565 51.192 ;
     RECT  76.313 35.472 76.637 35.736 ;
     RECT  76.529 26.64 76.853 26.664 ;
     RECT  76.385 36.912 76.889 36.936 ;
     RECT  72.904 42.72 76.921 42.744 ;
     RECT  76.421 23.424 77.033 23.448 ;
     RECT  76.921 42.576 77.173 42.744 ;
     RECT  77.173 42.576 77.372 42.84 ;
     RECT  77.137 43.92 77.372 43.944 ;
     RECT  76.097 45.504 77.389 46.2 ;
     RECT  77.372 42.576 77.413 43.944 ;
     RECT  76.421 21.648 77.461 22.2 ;
     RECT  77.413 42.576 77.569 44.136 ;
     RECT  77.389 45.504 77.569 46.248 ;
     RECT  77.461 20.736 77.965 22.2 ;
     RECT  77.965 20.736 78.008 22.776 ;
     RECT  77.965 30.864 78.008 30.888 ;
     RECT  76.637 35.472 78.008 35.496 ;
     RECT  75.877 38.688 78.008 38.712 ;
     RECT  77.569 42.576 78.008 46.248 ;
     RECT  75.593 49.008 78.008 49.032 ;
     RECT  78.008 2.148 78.112 71.292 ;
     RECT  78.112 2.418 78.304 71.022 ;
     RECT  78.304 30.576 78.653 30.888 ;
     RECT  78.304 45.552 78.653 46.728 ;
     RECT  78.304 26.352 78.761 29.544 ;
     RECT  78.653 45.552 78.761 46.008 ;
     RECT  78.761 45.552 78.905 45.576 ;
     RECT  78.761 29.184 78.977 29.544 ;
     RECT  78.304 20.112 79.517 20.136 ;
     RECT  78.761 26.352 79.625 28.2 ;
     RECT  78.977 29.52 79.625 29.544 ;
     RECT  78.304 22.512 79.657 24.36 ;
     RECT  79.693 36.192 79.841 36.216 ;
     RECT  79.549 35.136 79.949 35.16 ;
     RECT  78.653 30.576 80.165 30.84 ;
     RECT  79.765 32.448 80.237 32.76 ;
     RECT  79.945 38.784 80.309 38.808 ;
     RECT  80.237 32.544 80.341 32.76 ;
     RECT  79.657 21.696 80.489 24.36 ;
     RECT  80.341 32.544 80.525 33.576 ;
     RECT  80.165 30.816 80.665 30.84 ;
     RECT  80.525 32.736 80.665 33.576 ;
     RECT  79.657 37.584 80.705 37.608 ;
     RECT  80.089 25.44 80.741 25.464 ;
     RECT  80.489 21.696 80.809 23.976 ;
     RECT  80.665 30.816 80.957 30.984 ;
     RECT  80.957 30.864 81.241 30.984 ;
     RECT  80.845 46.224 81.313 46.248 ;
     RECT  79.625 26.736 81.389 28.2 ;
     RECT  80.377 36.48 81.457 36.504 ;
     RECT  81.457 20.592 81.493 20.616 ;
     RECT  80.809 21.648 81.493 23.976 ;
     RECT  80.665 32.736 81.493 34.2 ;
     RECT  81.313 45.36 81.493 46.248 ;
     RECT  80.881 47.76 81.493 47.784 ;
     RECT  81.493 20.592 81.601 23.976 ;
     RECT  81.493 25.008 81.601 25.032 ;
     RECT  81.241 30.864 81.601 31.176 ;
     RECT  81.493 32.208 81.601 34.2 ;
     RECT  81.601 18.768 81.637 18.792 ;
     RECT  81.601 20.592 81.637 25.032 ;
     RECT  81.389 27.6 81.709 28.2 ;
     RECT  81.637 18.672 81.713 18.792 ;
     RECT  81.637 35.472 81.745 35.496 ;
     RECT  81.457 36.48 81.745 37.416 ;
     RECT  81.713 18.672 81.785 18.696 ;
     RECT  81.745 35.472 81.853 37.416 ;
     RECT  81.637 20.112 81.925 25.032 ;
     RECT  81.709 27.6 82.069 29.16 ;
     RECT  81.601 30.864 82.069 34.2 ;
     RECT  81.853 35.472 82.069 37.608 ;
     RECT  81.493 45.36 82.069 48.36 ;
     RECT  80.989 49.488 82.069 49.512 ;
     RECT  82.069 27.6 82.573 37.608 ;
     RECT  82.537 38.736 82.573 38.76 ;
     RECT  82.069 45.264 82.573 49.704 ;
     RECT  81.925 50.928 82.573 50.952 ;
     RECT  81.925 19.92 82.645 26.568 ;
     RECT  82.573 27.6 82.645 38.76 ;
     RECT  82.573 45.264 83.077 50.952 ;
     RECT  82.645 19.92 83.977 38.76 ;
     RECT  83.977 19.92 84.204 38.856 ;
     RECT  83.077 45.264 84.204 51.336 ;
    LAYER M5 ;
     RECT  2.4 2.137 2.52 2.151 ;
     RECT  7.8 2.137 7.92 2.151 ;
     RECT  13.2 2.137 13.32 2.151 ;
     RECT  18.6 2.137 18.72 2.151 ;
     RECT  24 2.137 24.12 2.151 ;
     RECT  29.4 2.137 29.52 2.151 ;
     RECT  34.8 2.137 34.92 2.151 ;
     RECT  40.2 2.137 40.32 2.151 ;
     RECT  45.6 2.137 45.72 2.151 ;
     RECT  51 2.137 51.12 2.151 ;
     RECT  56.4 2.137 56.52 2.151 ;
     RECT  61.8 2.137 61.92 2.151 ;
     RECT  67.2 2.137 67.32 2.151 ;
     RECT  72.6 2.137 72.72 2.151 ;
     RECT  78 2.137 78.12 2.151 ;
     RECT  4.896 15.301 4.92 16.501 ;
     RECT  4.896 16.501 5.16 16.547 ;
     RECT  7.8 2.151 8.112 16.645 ;
     RECT  0.144 16.597 0.168 16.883 ;
     RECT  7.8 16.645 8.232 17.077 ;
     RECT  40.2 2.151 40.512 17.077 ;
     RECT  34.8 2.151 35.112 17.605 ;
     RECT  5.136 16.547 5.16 18.181 ;
     RECT  45.6 2.151 45.912 18.181 ;
     RECT  46.992 17.461 47.016 18.181 ;
     RECT  5.136 18.181 5.496 18.227 ;
     RECT  3.888 15.829 3.912 18.275 ;
     RECT  45.6 18.181 47.544 18.275 ;
     RECT  11.328 16.837 11.352 18.469 ;
     RECT  39.456 17.077 41.064 19.237 ;
     RECT  5.472 18.227 5.496 19.283 ;
     RECT  7.8 17.077 8.328 19.333 ;
     RECT  39.456 19.237 42.024 19.333 ;
     RECT  39.456 19.333 42.168 19.379 ;
     RECT  39.456 19.379 40.512 19.427 ;
     RECT  0.24 18.949 0.264 20.101 ;
     RECT  45.6 18.275 46.296 20.339 ;
     RECT  0.144 20.101 0.264 20.387 ;
     RECT  72.6 2.151 72.912 20.437 ;
     RECT  42 19.379 42.168 20.723 ;
     RECT  32.832 20.341 32.856 20.725 ;
     RECT  78 2.151 78.312 20.725 ;
     RECT  72.6 20.437 73.416 20.773 ;
     RECT  39.072 19.669 39.096 21.155 ;
     RECT  42 20.723 42.024 21.155 ;
     RECT  72.48 20.773 73.416 21.155 ;
     RECT  47.52 18.275 47.544 21.395 ;
     RECT  51 2.151 51.312 21.541 ;
     RECT  45.6 20.339 46.2 21.637 ;
     RECT  45.6 21.637 47.064 21.683 ;
     RECT  77.472 20.725 78.312 21.683 ;
     RECT  7.44 19.333 8.328 21.781 ;
     RECT  37.92 21.301 37.944 22.115 ;
     RECT  50.88 21.541 51.312 22.499 ;
     RECT  47.04 21.683 47.064 22.741 ;
     RECT  51 22.499 51.312 22.789 ;
     RECT  52.32 22.165 52.344 22.789 ;
     RECT  32.832 20.725 33.528 22.835 ;
     RECT  45.6 21.683 45.912 22.837 ;
     RECT  47.04 22.741 47.208 22.837 ;
     RECT  51 22.789 52.344 23.027 ;
     RECT  72.48 21.155 72.912 23.173 ;
     RECT  45.6 22.837 47.208 23.363 ;
     RECT  34.8 17.605 35.208 23.699 ;
     RECT  68.928 22.165 68.952 23.843 ;
     RECT  38.592 23.605 38.616 23.893 ;
     RECT  67.2 2.151 67.512 23.893 ;
     RECT  71.424 22.741 71.448 23.987 ;
     RECT  59.808 22.789 59.832 24.323 ;
     RECT  66.768 23.893 67.512 24.371 ;
     RECT  75.888 21.541 75.912 24.371 ;
     RECT  40.2 19.427 40.512 24.469 ;
     RECT  42.192 24.421 42.216 24.469 ;
     RECT  45.6 23.363 47.016 24.469 ;
     RECT  32.832 22.835 33.336 24.563 ;
     RECT  38.592 23.893 39.144 24.563 ;
     RECT  72.432 23.173 72.912 24.563 ;
     RECT  2.4 2.151 2.712 24.613 ;
     RECT  5.664 22.741 5.688 24.613 ;
     RECT  7.104 21.781 8.328 24.613 ;
     RECT  51 23.027 51.768 24.707 ;
     RECT  5.664 24.613 8.328 24.755 ;
     RECT  39.12 24.563 39.144 24.853 ;
     RECT  2.4 24.613 2.808 24.949 ;
     RECT  39.12 24.853 39.192 25.091 ;
     RECT  40.2 24.469 42.216 25.139 ;
     RECT  2.4 24.949 3.48 25.141 ;
     RECT  34.8 23.699 35.112 25.573 ;
     RECT  6.288 24.755 8.328 25.715 ;
     RECT  38.016 25.045 38.04 25.715 ;
     RECT  39.12 25.091 39.144 25.715 ;
     RECT  6.288 25.715 6.792 25.763 ;
     RECT  40.2 25.139 41.736 25.811 ;
     RECT  2.304 25.141 3.48 25.859 ;
     RECT  48.72 25.093 48.744 25.955 ;
     RECT  6.624 25.763 6.792 26.243 ;
     RECT  45.6 24.469 47.304 26.243 ;
     RECT  45.6 26.243 46.728 26.339 ;
     RECT  11.088 18.469 11.352 26.725 ;
     RECT  14.784 26.677 14.808 26.773 ;
     RECT  33.312 24.563 33.336 26.819 ;
     RECT  14.688 26.773 14.808 27.301 ;
     RECT  45.6 26.339 45.912 27.301 ;
     RECT  14.688 27.301 14.904 27.347 ;
     RECT  20.4 26.197 20.424 27.347 ;
     RECT  2.4 25.859 3.48 27.397 ;
     RECT  2.4 27.397 4.152 27.779 ;
     RECT  11.088 26.725 11.64 27.875 ;
     RECT  14.88 27.347 14.904 27.971 ;
     RECT  31.488 27.205 31.512 27.971 ;
     RECT  2.4 27.779 3.48 28.115 ;
     RECT  6.624 26.243 6.648 28.115 ;
     RECT  22.752 26.245 22.776 28.115 ;
     RECT  72.6 24.563 72.912 28.117 ;
     RECT  21.696 22.741 21.72 28.261 ;
     RECT  7.8 25.715 8.328 28.453 ;
     RECT  15.984 27.205 16.008 28.499 ;
     RECT  34.8 25.573 35.976 28.643 ;
     RECT  11.328 27.875 11.64 28.645 ;
     RECT  13.2 2.151 13.512 28.741 ;
     RECT  7.392 28.453 8.328 28.789 ;
     RECT  24 2.151 24.312 28.789 ;
     RECT  11.328 28.645 11.784 28.933 ;
     RECT  40.2 25.811 41.256 28.933 ;
     RECT  19.968 27.781 19.992 29.267 ;
     RECT  71.856 28.117 72.912 29.461 ;
     RECT  75.12 27.877 75.144 29.461 ;
     RECT  15.792 28.693 15.816 29.605 ;
     RECT  68.88 27.301 68.904 29.605 ;
     RECT  21.696 28.261 22.536 29.651 ;
     RECT  24 28.789 25.128 29.651 ;
     RECT  68.64 29.605 68.904 29.651 ;
     RECT  10.848 28.933 11.784 29.699 ;
     RECT  74.064 23.029 74.088 29.795 ;
     RECT  7.392 28.789 8.568 30.035 ;
     RECT  40.2 28.933 41.64 30.035 ;
     RECT  7.392 30.035 8.112 30.181 ;
     RECT  11.424 29.699 11.784 30.181 ;
     RECT  39.12 27.877 39.144 30.275 ;
     RECT  40.2 30.035 40.512 30.469 ;
     RECT  75.12 29.461 75.576 30.565 ;
     RECT  43.296 30.181 43.32 30.611 ;
     RECT  11.424 30.181 11.832 30.709 ;
     RECT  13.056 28.741 13.512 30.709 ;
     RECT  0.144 20.387 0.168 30.757 ;
     RECT  11.424 30.709 13.512 30.803 ;
     RECT  15.792 29.605 16.008 30.851 ;
     RECT  41.616 30.035 41.64 30.851 ;
     RECT  0.144 30.757 0.216 30.947 ;
     RECT  11.76 30.803 13.512 30.947 ;
     RECT  75.024 30.565 75.576 30.949 ;
     RECT  15.984 30.851 16.008 31.091 ;
     RECT  75.024 30.949 76.008 31.379 ;
     RECT  71.808 29.461 72.912 31.427 ;
     RECT  39.84 30.469 40.512 31.525 ;
     RECT  75.984 31.379 76.008 31.667 ;
     RECT  25.632 30.181 25.656 31.669 ;
     RECT  25.632 31.669 26.424 31.715 ;
     RECT  6.528 30.181 8.112 31.859 ;
     RECT  10.368 31.285 10.392 31.861 ;
     RECT  6.816 31.859 8.112 31.955 ;
     RECT  0.144 30.947 0.168 32.005 ;
     RECT  13.056 30.947 13.512 32.005 ;
     RECT  68.64 29.651 68.664 32.051 ;
     RECT  48.816 28.981 48.84 32.149 ;
     RECT  0.144 32.005 0.312 32.195 ;
     RECT  10.368 31.861 10.44 32.195 ;
     RECT  72.336 31.427 72.912 32.339 ;
     RECT  45.6 27.301 46.68 32.389 ;
     RECT  11.76 30.947 11.832 32.435 ;
     RECT  26.4 31.715 26.424 32.771 ;
     RECT  67.2 24.371 67.512 33.013 ;
     RECT  16.032 31.813 16.056 33.107 ;
     RECT  52.704 26.245 52.728 33.445 ;
     RECT  0.144 33.397 0.168 33.587 ;
     RECT  48.48 32.149 48.84 33.635 ;
     RECT  37.632 31.861 38.088 33.779 ;
     RECT  13.056 32.005 14.184 33.827 ;
     RECT  45.6 32.389 46.776 34.067 ;
     RECT  72.6 32.339 72.912 34.165 ;
     RECT  64.08 26.629 64.104 34.213 ;
     RECT  52.704 33.445 53.16 34.259 ;
     RECT  74.016 33.013 74.04 34.355 ;
     RECT  5.856 34.357 5.88 34.693 ;
     RECT  7.056 31.955 8.112 34.693 ;
     RECT  4.224 33.589 4.248 34.741 ;
     RECT  66.864 33.013 67.512 34.741 ;
     RECT  47.088 34.117 47.112 34.835 ;
     RECT  11.76 32.435 11.784 34.837 ;
     RECT  63.936 34.213 64.104 34.885 ;
     RECT  52.896 34.259 53.16 34.931 ;
     RECT  34.8 28.643 35.112 35.029 ;
     RECT  42.72 34.405 42.744 35.029 ;
     RECT  13.056 33.827 13.512 35.077 ;
     RECT  72.096 34.165 72.912 35.125 ;
     RECT  70.512 34.933 70.536 35.219 ;
     RECT  72.048 35.125 72.912 35.269 ;
     RECT  5.856 34.693 8.112 35.317 ;
     RECT  56.4 2.151 56.712 35.317 ;
     RECT  13.056 35.077 13.608 35.459 ;
     RECT  42.72 35.029 42.792 35.461 ;
     RECT  42 35.461 42.792 35.653 ;
     RECT  27.024 34.165 27.048 35.701 ;
     RECT  75.984 34.165 76.008 35.701 ;
     RECT  39.648 31.525 40.512 35.747 ;
     RECT  63.936 34.885 64.536 35.747 ;
     RECT  45.6 34.067 45.912 35.749 ;
     RECT  47.04 35.269 47.064 35.749 ;
     RECT  75.6 35.701 76.008 35.843 ;
     RECT  10.416 32.195 10.44 35.845 ;
     RECT  11.568 34.837 11.784 35.845 ;
     RECT  71.808 35.269 72.912 35.845 ;
     RECT  74.208 35.317 74.232 35.845 ;
     RECT  75.984 35.843 76.008 35.939 ;
     RECT  40.08 35.747 40.512 35.941 ;
     RECT  41.904 35.653 42.792 35.941 ;
     RECT  40.08 35.941 42.792 35.987 ;
     RECT  5.856 35.317 8.232 36.035 ;
     RECT  10.416 35.845 11.784 36.421 ;
     RECT  13.056 35.459 13.512 36.421 ;
     RECT  10.416 36.421 13.512 36.515 ;
     RECT  5.856 36.035 8.112 36.563 ;
     RECT  33.6 34.693 33.624 36.563 ;
     RECT  34.8 35.029 35.352 36.613 ;
     RECT  69.024 36.517 69.048 36.613 ;
     RECT  68.928 36.613 69.048 36.659 ;
     RECT  18.6 2.151 18.912 36.757 ;
     RECT  26.784 35.701 27.048 36.803 ;
     RECT  40.08 35.987 41.928 36.803 ;
     RECT  29.4 2.151 29.712 36.805 ;
     RECT  22.8 36.421 22.92 36.851 ;
     RECT  33.168 36.613 33.192 36.851 ;
     RECT  34.8 36.613 35.976 36.851 ;
     RECT  22.8 36.851 22.824 36.899 ;
     RECT  68.928 36.659 68.952 36.899 ;
     RECT  4.224 34.741 4.872 36.901 ;
     RECT  5.856 36.563 6.12 36.901 ;
     RECT  29.4 36.805 30.504 36.997 ;
     RECT  26.784 36.803 26.808 37.091 ;
     RECT  45.6 35.749 47.064 37.091 ;
     RECT  63.936 35.747 63.96 37.091 ;
     RECT  71.808 35.845 74.232 37.091 ;
     RECT  37.056 36.469 37.08 37.283 ;
     RECT  71.808 37.091 72.912 37.331 ;
     RECT  66.384 34.741 67.512 37.525 ;
     RECT  66.144 37.525 67.512 37.571 ;
     RECT  74.208 37.091 74.232 37.571 ;
     RECT  18.6 36.757 19.992 37.619 ;
     RECT  15.936 35.845 15.96 37.861 ;
     RECT  29.4 36.997 30.648 38.003 ;
     RECT  10.416 36.515 10.44 38.197 ;
     RECT  4.224 36.901 6.12 38.243 ;
     RECT  10.416 38.197 10.536 38.243 ;
     RECT  2.4 28.115 2.712 38.341 ;
     RECT  15.072 37.861 15.96 38.341 ;
     RECT  21.696 29.651 21.72 38.387 ;
     RECT  24 29.651 24.408 38.435 ;
     RECT  48.816 33.635 48.84 38.675 ;
     RECT  45.6 37.091 46.152 38.677 ;
     RECT  66.144 37.571 66.168 38.677 ;
     RECT  67.2 37.571 67.512 38.677 ;
     RECT  7.8 36.563 8.112 38.725 ;
     RECT  18.6 37.619 19.176 38.725 ;
     RECT  14.832 38.341 15.96 38.819 ;
     RECT  56.4 35.317 57.624 38.963 ;
     RECT  7.8 38.725 8.424 39.013 ;
     RECT  60.624 37.381 60.648 39.059 ;
     RECT  5.712 38.243 6.12 39.061 ;
     RECT  7.44 39.013 8.424 39.061 ;
     RECT  72.6 37.331 72.912 39.061 ;
     RECT  5.712 39.061 8.424 39.107 ;
     RECT  18.6 38.725 19.368 39.203 ;
     RECT  2.4 38.341 3.192 39.251 ;
     RECT  4.224 38.243 4.248 39.301 ;
     RECT  5.712 39.107 8.112 39.301 ;
     RECT  66.144 38.677 67.512 39.301 ;
     RECT  72.48 39.061 72.912 39.301 ;
     RECT  65.616 39.301 67.512 39.395 ;
     RECT  11.76 36.515 13.512 39.923 ;
     RECT  4.224 39.301 8.112 40.115 ;
     RECT  45.504 38.677 46.152 40.405 ;
     RECT  45.456 40.405 46.152 40.451 ;
     RECT  4.224 40.115 6.12 40.595 ;
     RECT  4.224 40.595 4.248 40.885 ;
     RECT  40.08 36.803 40.512 41.557 ;
     RECT  41.904 36.803 41.928 41.557 ;
     RECT  3.888 40.885 4.248 41.795 ;
     RECT  14.832 38.819 15.768 41.939 ;
     RECT  11.76 39.923 11.784 41.987 ;
     RECT  18.6 39.203 18.912 42.133 ;
     RECT  45.456 40.451 46.008 42.227 ;
     RECT  40.08 41.557 41.928 42.709 ;
     RECT  78 21.683 78.312 42.709 ;
     RECT  77.184 42.709 78.312 42.851 ;
     RECT  10.512 38.243 10.536 42.997 ;
     RECT  12 42.277 12.024 42.997 ;
     RECT  10.512 42.997 12.024 43.379 ;
     RECT  18.6 42.133 19.032 43.379 ;
     RECT  65.616 39.395 66.168 43.379 ;
     RECT  65.616 43.379 65.64 43.571 ;
     RECT  2.4 39.251 2.712 43.573 ;
     RECT  2.208 43.573 2.712 43.859 ;
     RECT  72.048 39.301 72.912 43.909 ;
     RECT  74.064 43.861 74.088 43.909 ;
     RECT  77.28 42.851 78.312 43.955 ;
     RECT  10.512 43.379 11.352 44.099 ;
     RECT  5.808 40.595 6.12 44.245 ;
     RECT  17.28 42.709 17.304 44.339 ;
     RECT  7.296 40.115 8.112 44.389 ;
     RECT  10.512 44.099 10.536 44.483 ;
     RECT  15.744 41.939 15.768 44.531 ;
     RECT  72.048 43.909 74.088 44.579 ;
     RECT  38.064 33.779 38.088 44.675 ;
     RECT  75.888 38.677 75.912 44.867 ;
     RECT  72.336 44.579 74.088 45.011 ;
     RECT  17.04 44.437 17.064 45.541 ;
     RECT  72.336 45.011 73.8 45.685 ;
     RECT  14.832 45.877 14.856 45.973 ;
     RECT  13.056 39.923 13.512 46.069 ;
     RECT  17.04 45.541 17.16 46.069 ;
     RECT  18.6 43.379 18.912 46.069 ;
     RECT  68.928 43.525 68.952 46.117 ;
     RECT  70.272 42.709 70.296 46.117 ;
     RECT  17.04 46.069 18.912 46.211 ;
     RECT  77.424 43.955 78.312 46.259 ;
     RECT  9.648 44.965 9.672 46.405 ;
     RECT  11.376 45.541 11.4 46.501 ;
     RECT  2.4 43.859 2.712 46.549 ;
     RECT  2.4 46.549 3.24 46.691 ;
     RECT  40.08 42.709 42.36 46.693 ;
     RECT  14.832 45.973 15.576 46.787 ;
     RECT  75.216 46.165 75.24 46.787 ;
     RECT  13.056 46.069 13.608 46.835 ;
     RECT  39.984 46.693 42.36 46.931 ;
     RECT  5.712 44.245 6.12 47.123 ;
     RECT  68.928 46.117 70.296 47.315 ;
     RECT  9.648 46.405 10.248 47.363 ;
     RECT  11.376 46.501 11.64 47.363 ;
     RECT  71.664 45.685 73.8 47.555 ;
     RECT  17.136 46.211 18.912 47.651 ;
     RECT  10.224 47.363 10.248 47.891 ;
     RECT  14.832 46.787 14.856 47.891 ;
     RECT  52.896 34.931 52.92 47.939 ;
     RECT  70.08 47.315 70.296 48.083 ;
     RECT  5.808 47.123 6.12 48.229 ;
     RECT  40.2 46.931 42.36 48.325 ;
     RECT  4.224 41.795 4.248 48.515 ;
     RECT  39.936 48.325 42.36 48.659 ;
     RECT  68.928 47.315 68.952 48.853 ;
     RECT  68.928 48.853 69.144 48.899 ;
     RECT  70.272 48.083 70.296 49.091 ;
     RECT  45.6 42.227 46.008 49.475 ;
     RECT  5.712 48.229 6.12 49.619 ;
     RECT  72.6 47.555 73.8 49.619 ;
     RECT  37.872 48.373 37.896 49.763 ;
     RECT  71.568 49.189 71.592 50.101 ;
     RECT  72.6 49.619 72.912 50.101 ;
     RECT  5.712 49.619 5.88 50.195 ;
     RECT  7.104 44.389 8.112 50.195 ;
     RECT  39.936 48.659 41.928 50.243 ;
     RECT  69.12 48.899 69.144 50.291 ;
     RECT  17.424 47.651 18.912 50.771 ;
     RECT  21.36 46.117 21.384 50.771 ;
     RECT  5.712 50.195 5.736 50.867 ;
     RECT  71.568 50.101 72.912 50.867 ;
     RECT  71.568 50.867 71.592 51.347 ;
     RECT  17.424 50.771 17.448 51.635 ;
     RECT  63.936 49.237 63.96 54.035 ;
     RECT  56.4 38.963 56.712 54.085 ;
     RECT  22.128 51.253 22.488 57.587 ;
     RECT  40.2 50.243 41.928 57.971 ;
     RECT  55.92 54.085 56.712 58.739 ;
     RECT  49.536 58.933 49.56 63.299 ;
     RECT  41.904 57.971 41.928 63.781 ;
     RECT  41.568 63.781 41.928 68.435 ;
     RECT  41.904 68.435 41.928 68.675 ;
     RECT  34.8 36.851 35.112 68.677 ;
     RECT  40.2 57.971 40.512 68.677 ;
     RECT  40.2 68.677 40.632 68.819 ;
     RECT  34.032 68.677 35.112 68.869 ;
     RECT  34.032 68.869 35.88 68.917 ;
     RECT  22.464 57.587 22.488 69.779 ;
     RECT  34.032 68.917 36.072 69.973 ;
     RECT  34.032 69.973 36.312 70.021 ;
     RECT  34.032 70.021 36.648 70.069 ;
     RECT  13.056 46.835 13.512 70.307 ;
     RECT  34.032 70.069 37.56 70.739 ;
     RECT  2.4 46.691 2.712 71.289 ;
     RECT  7.8 50.195 8.112 71.289 ;
     RECT  13.2 70.307 13.512 71.289 ;
     RECT  18.6 50.771 18.912 71.289 ;
     RECT  24 38.435 24.312 71.289 ;
     RECT  29.4 38.003 29.712 71.289 ;
     RECT  40.2 68.819 40.512 71.289 ;
     RECT  45.6 49.475 45.912 71.289 ;
     RECT  51 24.707 51.312 71.289 ;
     RECT  56.4 58.739 56.712 71.289 ;
     RECT  61.8 2.151 62.112 71.289 ;
     RECT  67.2 39.395 67.512 71.289 ;
     RECT  72.6 50.867 72.912 71.289 ;
     RECT  78 46.259 78.312 71.289 ;
     RECT  2.4 71.289 2.52 71.303 ;
     RECT  7.8 71.289 7.92 71.303 ;
     RECT  13.2 71.289 13.32 71.303 ;
     RECT  18.6 71.289 18.72 71.303 ;
     RECT  24 71.289 24.12 71.303 ;
     RECT  29.4 71.289 29.52 71.303 ;
     RECT  40.2 71.289 40.32 71.303 ;
     RECT  45.6 71.289 45.72 71.303 ;
     RECT  51 71.289 51.12 71.303 ;
     RECT  56.4 71.289 56.52 71.303 ;
     RECT  61.8 71.289 61.92 71.303 ;
     RECT  67.2 71.289 67.32 71.303 ;
     RECT  72.6 71.289 72.72 71.303 ;
     RECT  78 71.289 78.12 71.303 ;
     RECT  34.032 70.739 36.744 73.424 ;
     RECT  2.712 15.829 3.888 18.275 ;
     RECT  3.912 15.829 4.896 16.547 ;
     RECT  3.912 16.547 5.136 18.227 ;
     RECT  45.912 17.461 46.992 18.181 ;
     RECT  46.296 18.275 47.52 20.339 ;
     RECT  40.512 19.379 42 21.155 ;
     RECT  39.456 19.427 40.2 19.669 ;
     RECT  39.096 19.669 40.2 21.155 ;
     RECT  46.2 20.339 47.52 21.395 ;
     RECT  33.528 20.725 34.8 22.835 ;
     RECT  46.2 21.395 47.208 21.637 ;
     RECT  47.064 21.637 47.208 22.741 ;
     RECT  45.912 21.683 47.04 22.837 ;
     RECT  51.312 22.165 52.32 22.789 ;
     RECT  67.512 22.165 68.928 23.843 ;
     RECT  5.688 22.741 7.104 24.613 ;
     RECT  71.448 22.741 72.48 23.173 ;
     RECT  33.336 22.835 34.8 26.819 ;
     RECT  72.912 23.029 74.064 29.795 ;
     RECT  71.448 23.173 72.432 23.987 ;
     RECT  47.016 23.363 47.208 24.469 ;
     RECT  39.144 23.893 40.2 24.853 ;
     RECT  38.592 24.563 39.12 25.045 ;
     RECT  39.192 24.853 40.2 25.091 ;
     RECT  38.04 25.045 39.12 25.715 ;
     RECT  39.144 25.091 40.2 25.715 ;
     RECT  47.304 25.093 48.72 25.955 ;
     RECT  6.792 25.715 7.8 26.243 ;
     RECT  18.912 26.197 20.4 27.347 ;
     RECT  20.424 26.197 21.696 27.347 ;
     RECT  6.648 26.243 7.8 28.115 ;
     RECT  21.72 26.245 22.752 28.115 ;
     RECT  22.776 26.245 24 28.115 ;
     RECT  51.312 26.245 52.704 34.259 ;
     RECT  45.912 26.339 46.68 27.301 ;
     RECT  13.512 26.677 14.784 26.773 ;
     RECT  13.512 26.773 14.688 27.347 ;
     RECT  14.808 27.205 15.984 27.301 ;
     RECT  14.904 27.301 15.984 27.971 ;
     RECT  67.512 27.301 68.88 29.605 ;
     RECT  13.512 27.347 14.88 27.971 ;
     RECT  18.912 27.347 19.992 27.781 ;
     RECT  18.912 27.781 19.968 29.267 ;
     RECT  11.088 27.875 11.328 28.933 ;
     RECT  39.144 27.877 40.2 30.275 ;
     RECT  74.088 27.877 75.12 29.795 ;
     RECT  15.792 27.971 15.984 28.499 ;
     RECT  7.392 28.115 7.8 28.453 ;
     RECT  21.72 28.115 24 28.261 ;
     RECT  22.536 28.261 24 29.651 ;
     RECT  15.792 28.499 16.008 28.693 ;
     RECT  11.784 28.645 13.2 28.741 ;
     RECT  15.816 28.693 16.008 29.605 ;
     RECT  11.784 28.741 13.056 30.181 ;
     RECT  67.512 29.605 68.64 32.051 ;
     RECT  24.408 29.651 25.128 30.181 ;
     RECT  75.024 29.795 75.12 30.565 ;
     RECT  40.512 30.035 41.616 30.851 ;
     RECT  11.832 30.181 13.056 30.709 ;
     RECT  24.408 30.181 25.632 31.715 ;
     RECT  39.648 30.275 40.2 30.469 ;
     RECT  39.648 30.469 39.84 31.525 ;
     RECT  11.424 30.803 11.76 31.285 ;
     RECT  0.168 30.947 0.216 32.005 ;
     RECT  11.832 30.947 13.056 32.435 ;
     RECT  10.392 31.285 11.76 31.861 ;
     RECT  10.44 31.861 11.76 34.837 ;
     RECT  0.144 32.195 0.168 33.397 ;
     RECT  11.784 32.435 13.056 36.421 ;
     RECT  72.912 33.013 74.016 34.355 ;
     RECT  2.712 33.589 4.224 38.341 ;
     RECT  13.512 33.827 13.608 35.077 ;
     RECT  45.912 34.067 46.776 34.117 ;
     RECT  45.912 34.117 47.088 34.835 ;
     RECT  72.912 34.355 74.04 35.317 ;
     RECT  5.88 34.357 7.056 34.693 ;
     RECT  33.624 34.693 34.8 36.563 ;
     RECT  4.872 34.741 5.856 36.901 ;
     RECT  45.912 34.835 47.064 35.269 ;
     RECT  10.44 34.837 11.568 35.845 ;
     RECT  70.536 35.125 72.048 35.219 ;
     RECT  71.808 35.219 72.048 35.269 ;
     RECT  45.912 35.269 47.04 35.749 ;
     RECT  72.912 35.317 74.208 35.845 ;
     RECT  40.512 35.461 42 35.653 ;
     RECT  40.512 35.653 41.904 35.941 ;
     RECT  74.232 35.701 75.6 35.843 ;
     RECT  21.72 36.421 22.8 36.899 ;
     RECT  22.92 36.421 24 36.851 ;
     RECT  37.08 36.469 38.064 37.283 ;
     RECT  10.44 36.515 11.76 38.197 ;
     RECT  67.512 36.517 69.024 36.613 ;
     RECT  35.976 36.613 37.056 36.851 ;
     RECT  67.512 36.613 68.928 36.899 ;
     RECT  40.512 36.803 41.904 41.557 ;
     RECT  22.824 36.851 24 36.899 ;
     RECT  72.912 37.091 74.208 37.571 ;
     RECT  60.648 37.381 61.8 39.059 ;
     RECT  66.168 37.571 67.2 38.677 ;
     RECT  19.176 37.619 19.368 38.725 ;
     RECT  10.536 38.197 11.76 41.987 ;
     RECT  4.248 38.243 5.712 39.301 ;
     RECT  3.192 38.341 4.224 39.251 ;
     RECT  13.512 38.341 14.832 41.939 ;
     RECT  6.12 39.013 7.44 39.061 ;
     RECT  2.712 39.251 4.224 40.885 ;
     RECT  66.168 39.395 67.2 43.379 ;
     RECT  11.784 39.923 13.056 41.987 ;
     RECT  6.12 40.115 7.296 44.389 ;
     RECT  2.712 40.885 3.888 41.795 ;
     RECT  2.712 41.795 4.224 46.549 ;
     RECT  10.536 41.987 13.056 42.277 ;
     RECT  10.536 42.277 12 42.997 ;
     RECT  12.024 42.277 13.056 43.379 ;
     RECT  15.768 42.709 17.28 44.339 ;
     RECT  17.304 42.709 18.6 44.339 ;
     RECT  75.912 42.709 77.184 42.851 ;
     RECT  75.912 42.851 77.28 43.955 ;
     RECT  67.512 43.525 68.928 48.899 ;
     RECT  68.952 43.525 70.272 46.117 ;
     RECT  72.912 43.861 74.064 43.909 ;
     RECT  75.912 43.955 77.424 44.867 ;
     RECT  4.248 44.245 5.712 47.123 ;
     RECT  15.768 44.339 18.6 44.437 ;
     RECT  6.12 44.389 7.104 49.619 ;
     RECT  15.768 44.437 17.04 44.531 ;
     RECT  17.064 44.437 18.6 45.541 ;
     RECT  15.744 44.531 17.04 45.877 ;
     RECT  72.048 44.579 72.336 45.685 ;
     RECT  73.8 45.011 74.088 46.165 ;
     RECT  17.16 45.541 18.6 46.069 ;
     RECT  70.296 45.685 71.664 47.555 ;
     RECT  13.512 45.877 14.832 46.069 ;
     RECT  14.856 45.877 17.04 45.973 ;
     RECT  15.576 45.973 17.04 46.211 ;
     RECT  13.608 46.069 14.832 46.835 ;
     RECT  73.8 46.165 75.216 46.787 ;
     RECT  10.248 46.405 11.376 47.363 ;
     RECT  11.64 46.501 13.056 47.363 ;
     RECT  3.24 46.549 4.224 46.691 ;
     RECT  2.712 46.691 4.224 48.515 ;
     RECT  13.512 46.835 14.832 47.891 ;
     RECT  39.984 46.931 40.2 48.325 ;
     RECT  4.248 47.123 5.808 48.229 ;
     RECT  68.952 47.315 70.08 48.083 ;
     RECT  68.952 48.083 70.272 48.853 ;
     RECT  4.248 48.229 5.712 48.515 ;
     RECT  69.144 48.853 70.272 49.091 ;
     RECT  71.592 49.189 72.6 50.101 ;
     RECT  5.88 49.619 7.104 50.195 ;
     RECT  17.448 50.771 18.6 51.635 ;
     RECT  71.592 50.867 72.6 51.347 ;
     RECT  22.488 51.253 24 69.779 ;
     RECT  40.512 57.971 41.904 63.781 ;
     RECT  49.56 58.933 51 63.299 ;
     RECT  40.512 63.781 41.568 68.435 ;
     RECT  40.512 68.435 41.904 68.675 ;
     RECT  40.512 68.675 40.632 68.677 ;
  END
END ot_smh_own_local_icg_eg
END LIBRARY
